VERSION 5.8 ;
BUSBITCHARS "[]" ;
DIVIDERCHAR "/" ;
UNITS
    DATABASE MICRONS 1000 ;
END UNITS

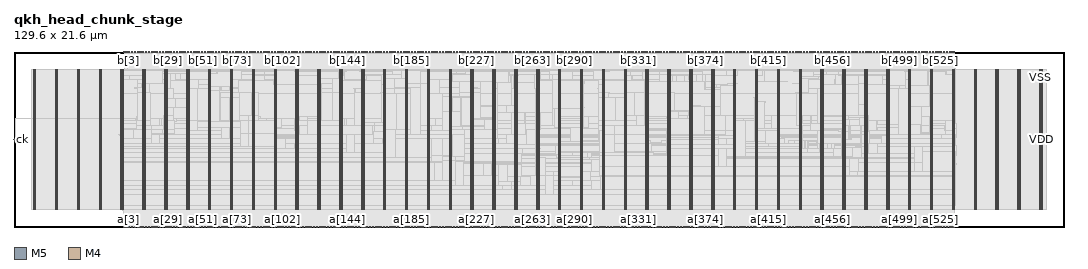
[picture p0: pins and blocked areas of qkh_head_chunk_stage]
MACRO qkh_head_chunk_stage
  FOREIGN qkh_head_chunk_stage 0 0 ;
  CLASS BLOCK ;
  SIZE 129.6 BY 21.6 ;
  PIN a[0]
    DIRECTION INPUT ;
    USE SIGNAL ;
    PORT
      LAYER M5 ;
        RECT  13.488 -0.072 13.512 0.072 ;
    END
  END a[0]
  PIN a[100]
    DIRECTION INPUT ;
    USE SIGNAL ;
    PORT
      LAYER M5 ;
        RECT  32.688 -0.072 32.712 0.072 ;
    END
  END a[100]
  PIN a[101]
    DIRECTION INPUT ;
    USE SIGNAL ;
    PORT
      LAYER M5 ;
        RECT  32.88 -0.072 32.904 0.072 ;
    END
  END a[101]
  PIN a[102]
    DIRECTION INPUT ;
    USE SIGNAL ;
    PORT
      LAYER M5 ;
        RECT  33.072 -0.072 33.096 0.072 ;
    END
  END a[102]
  PIN a[103]
    DIRECTION INPUT ;
    USE SIGNAL ;
    PORT
      LAYER M5 ;
        RECT  33.264 -0.072 33.288 0.072 ;
    END
  END a[103]
  PIN a[104]
    DIRECTION INPUT ;
    USE SIGNAL ;
    PORT
      LAYER M5 ;
        RECT  33.456 -0.072 33.48 0.072 ;
    END
  END a[104]
  PIN a[105]
    DIRECTION INPUT ;
    USE SIGNAL ;
    PORT
      LAYER M5 ;
        RECT  33.648 -0.072 33.672 0.072 ;
    END
  END a[105]
  PIN a[106]
    DIRECTION INPUT ;
    USE SIGNAL ;
    PORT
      LAYER M5 ;
        RECT  33.84 -0.072 33.864 0.072 ;
    END
  END a[106]
  PIN a[107]
    DIRECTION INPUT ;
    USE SIGNAL ;
    PORT
      LAYER M5 ;
        RECT  34.032 -0.072 34.056 0.072 ;
    END
  END a[107]
  PIN a[108]
    DIRECTION INPUT ;
    USE SIGNAL ;
    PORT
      LAYER M5 ;
        RECT  34.224 -0.072 34.248 0.072 ;
    END
  END a[108]
  PIN a[109]
    DIRECTION INPUT ;
    USE SIGNAL ;
    PORT
      LAYER M5 ;
        RECT  34.416 -0.072 34.44 0.072 ;
    END
  END a[109]
  PIN a[10]
    DIRECTION INPUT ;
    USE SIGNAL ;
    PORT
      LAYER M5 ;
        RECT  15.408 -0.072 15.432 0.072 ;
    END
  END a[10]
  PIN a[110]
    DIRECTION INPUT ;
    USE SIGNAL ;
    PORT
      LAYER M5 ;
        RECT  34.608 -0.072 34.632 0.072 ;
    END
  END a[110]
  PIN a[111]
    DIRECTION INPUT ;
    USE SIGNAL ;
    PORT
      LAYER M5 ;
        RECT  34.8 -0.072 34.824 0.072 ;
    END
  END a[111]
  PIN a[112]
    DIRECTION INPUT ;
    USE SIGNAL ;
    PORT
      LAYER M5 ;
        RECT  34.992 -0.072 35.016 0.072 ;
    END
  END a[112]
  PIN a[113]
    DIRECTION INPUT ;
    USE SIGNAL ;
    PORT
      LAYER M5 ;
        RECT  35.184 -0.072 35.208 0.072 ;
    END
  END a[113]
  PIN a[114]
    DIRECTION INPUT ;
    USE SIGNAL ;
    PORT
      LAYER M5 ;
        RECT  35.376 -0.072 35.4 0.072 ;
    END
  END a[114]
  PIN a[115]
    DIRECTION INPUT ;
    USE SIGNAL ;
    PORT
      LAYER M5 ;
        RECT  35.568 -0.072 35.592 0.072 ;
    END
  END a[115]
  PIN a[116]
    DIRECTION INPUT ;
    USE SIGNAL ;
    PORT
      LAYER M5 ;
        RECT  35.76 -0.072 35.784 0.072 ;
    END
  END a[116]
  PIN a[117]
    DIRECTION INPUT ;
    USE SIGNAL ;
    PORT
      LAYER M5 ;
        RECT  35.952 -0.072 35.976 0.072 ;
    END
  END a[117]
  PIN a[118]
    DIRECTION INPUT ;
    USE SIGNAL ;
    PORT
      LAYER M5 ;
        RECT  36.144 -0.072 36.168 0.072 ;
    END
  END a[118]
  PIN a[119]
    DIRECTION INPUT ;
    USE SIGNAL ;
    PORT
      LAYER M5 ;
        RECT  36.336 -0.072 36.36 0.072 ;
    END
  END a[119]
  PIN a[11]
    DIRECTION INPUT ;
    USE SIGNAL ;
    PORT
      LAYER M5 ;
        RECT  15.6 -0.072 15.624 0.072 ;
    END
  END a[11]
  PIN a[120]
    DIRECTION INPUT ;
    USE SIGNAL ;
    PORT
      LAYER M5 ;
        RECT  36.528 -0.072 36.552 0.072 ;
    END
  END a[120]
  PIN a[121]
    DIRECTION INPUT ;
    USE SIGNAL ;
    PORT
      LAYER M5 ;
        RECT  36.72 -0.072 36.744 0.072 ;
    END
  END a[121]
  PIN a[122]
    DIRECTION INPUT ;
    USE SIGNAL ;
    PORT
      LAYER M5 ;
        RECT  36.912 -0.072 36.936 0.072 ;
    END
  END a[122]
  PIN a[123]
    DIRECTION INPUT ;
    USE SIGNAL ;
    PORT
      LAYER M5 ;
        RECT  37.104 -0.072 37.128 0.072 ;
    END
  END a[123]
  PIN a[124]
    DIRECTION INPUT ;
    USE SIGNAL ;
    PORT
      LAYER M5 ;
        RECT  37.296 -0.072 37.32 0.072 ;
    END
  END a[124]
  PIN a[125]
    DIRECTION INPUT ;
    USE SIGNAL ;
    PORT
      LAYER M5 ;
        RECT  37.488 -0.072 37.512 0.072 ;
    END
  END a[125]
  PIN a[126]
    DIRECTION INPUT ;
    USE SIGNAL ;
    PORT
      LAYER M5 ;
        RECT  37.68 -0.072 37.704 0.072 ;
    END
  END a[126]
  PIN a[127]
    DIRECTION INPUT ;
    USE SIGNAL ;
    PORT
      LAYER M5 ;
        RECT  37.872 -0.072 37.896 0.072 ;
    END
  END a[127]
  PIN a[128]
    DIRECTION INPUT ;
    USE SIGNAL ;
    PORT
      LAYER M5 ;
        RECT  38.064 -0.072 38.088 0.072 ;
    END
  END a[128]
  PIN a[129]
    DIRECTION INPUT ;
    USE SIGNAL ;
    PORT
      LAYER M5 ;
        RECT  38.256 -0.072 38.28 0.072 ;
    END
  END a[129]
  PIN a[12]
    DIRECTION INPUT ;
    USE SIGNAL ;
    PORT
      LAYER M5 ;
        RECT  15.792 -0.072 15.816 0.072 ;
    END
  END a[12]
  PIN a[130]
    DIRECTION INPUT ;
    USE SIGNAL ;
    PORT
      LAYER M5 ;
        RECT  38.448 -0.072 38.472 0.072 ;
    END
  END a[130]
  PIN a[131]
    DIRECTION INPUT ;
    USE SIGNAL ;
    PORT
      LAYER M5 ;
        RECT  38.64 -0.072 38.664 0.072 ;
    END
  END a[131]
  PIN a[132]
    DIRECTION INPUT ;
    USE SIGNAL ;
    PORT
      LAYER M5 ;
        RECT  38.832 -0.072 38.856 0.072 ;
    END
  END a[132]
  PIN a[133]
    DIRECTION INPUT ;
    USE SIGNAL ;
    PORT
      LAYER M5 ;
        RECT  39.024 -0.072 39.048 0.072 ;
    END
  END a[133]
  PIN a[134]
    DIRECTION INPUT ;
    USE SIGNAL ;
    PORT
      LAYER M5 ;
        RECT  39.216 -0.072 39.24 0.072 ;
    END
  END a[134]
  PIN a[135]
    DIRECTION INPUT ;
    USE SIGNAL ;
    PORT
      LAYER M5 ;
        RECT  39.408 -0.072 39.432 0.072 ;
    END
  END a[135]
  PIN a[136]
    DIRECTION INPUT ;
    USE SIGNAL ;
    PORT
      LAYER M5 ;
        RECT  39.6 -0.072 39.624 0.072 ;
    END
  END a[136]
  PIN a[137]
    DIRECTION INPUT ;
    USE SIGNAL ;
    PORT
      LAYER M5 ;
        RECT  39.792 -0.072 39.816 0.072 ;
    END
  END a[137]
  PIN a[138]
    DIRECTION INPUT ;
    USE SIGNAL ;
    PORT
      LAYER M5 ;
        RECT  39.984 -0.072 40.008 0.072 ;
    END
  END a[138]
  PIN a[139]
    DIRECTION INPUT ;
    USE SIGNAL ;
    PORT
      LAYER M5 ;
        RECT  40.176 -0.072 40.2 0.072 ;
    END
  END a[139]
  PIN a[13]
    DIRECTION INPUT ;
    USE SIGNAL ;
    PORT
      LAYER M5 ;
        RECT  15.984 -0.072 16.008 0.072 ;
    END
  END a[13]
  PIN a[140]
    DIRECTION INPUT ;
    USE SIGNAL ;
    PORT
      LAYER M5 ;
        RECT  40.368 -0.072 40.392 0.072 ;
    END
  END a[140]
  PIN a[141]
    DIRECTION INPUT ;
    USE SIGNAL ;
    PORT
      LAYER M5 ;
        RECT  40.56 -0.072 40.584 0.072 ;
    END
  END a[141]
  PIN a[142]
    DIRECTION INPUT ;
    USE SIGNAL ;
    PORT
      LAYER M5 ;
        RECT  40.752 -0.072 40.776 0.072 ;
    END
  END a[142]
  PIN a[143]
    DIRECTION INPUT ;
    USE SIGNAL ;
    PORT
      LAYER M5 ;
        RECT  40.944 -0.072 40.968 0.072 ;
    END
  END a[143]
  PIN a[144]
    DIRECTION INPUT ;
    USE SIGNAL ;
    PORT
      LAYER M5 ;
        RECT  41.136 -0.072 41.16 0.072 ;
    END
  END a[144]
  PIN a[145]
    DIRECTION INPUT ;
    USE SIGNAL ;
    PORT
      LAYER M5 ;
        RECT  41.328 -0.072 41.352 0.072 ;
    END
  END a[145]
  PIN a[146]
    DIRECTION INPUT ;
    USE SIGNAL ;
    PORT
      LAYER M5 ;
        RECT  41.52 -0.072 41.544 0.072 ;
    END
  END a[146]
  PIN a[147]
    DIRECTION INPUT ;
    USE SIGNAL ;
    PORT
      LAYER M5 ;
        RECT  41.712 -0.072 41.736 0.072 ;
    END
  END a[147]
  PIN a[148]
    DIRECTION INPUT ;
    USE SIGNAL ;
    PORT
      LAYER M5 ;
        RECT  41.904 -0.072 41.928 0.072 ;
    END
  END a[148]
  PIN a[149]
    DIRECTION INPUT ;
    USE SIGNAL ;
    PORT
      LAYER M5 ;
        RECT  42.096 -0.072 42.12 0.072 ;
    END
  END a[149]
  PIN a[14]
    DIRECTION INPUT ;
    USE SIGNAL ;
    PORT
      LAYER M5 ;
        RECT  16.176 -0.072 16.2 0.072 ;
    END
  END a[14]
  PIN a[150]
    DIRECTION INPUT ;
    USE SIGNAL ;
    PORT
      LAYER M5 ;
        RECT  42.288 -0.072 42.312 0.072 ;
    END
  END a[150]
  PIN a[151]
    DIRECTION INPUT ;
    USE SIGNAL ;
    PORT
      LAYER M5 ;
        RECT  42.48 -0.072 42.504 0.072 ;
    END
  END a[151]
  PIN a[152]
    DIRECTION INPUT ;
    USE SIGNAL ;
    PORT
      LAYER M5 ;
        RECT  42.672 -0.072 42.696 0.072 ;
    END
  END a[152]
  PIN a[153]
    DIRECTION INPUT ;
    USE SIGNAL ;
    PORT
      LAYER M5 ;
        RECT  42.864 -0.072 42.888 0.072 ;
    END
  END a[153]
  PIN a[154]
    DIRECTION INPUT ;
    USE SIGNAL ;
    PORT
      LAYER M5 ;
        RECT  43.056 -0.072 43.08 0.072 ;
    END
  END a[154]
  PIN a[155]
    DIRECTION INPUT ;
    USE SIGNAL ;
    PORT
      LAYER M5 ;
        RECT  43.248 -0.072 43.272 0.072 ;
    END
  END a[155]
  PIN a[156]
    DIRECTION INPUT ;
    USE SIGNAL ;
    PORT
      LAYER M5 ;
        RECT  43.44 -0.072 43.464 0.072 ;
    END
  END a[156]
  PIN a[157]
    DIRECTION INPUT ;
    USE SIGNAL ;
    PORT
      LAYER M5 ;
        RECT  43.632 -0.072 43.656 0.072 ;
    END
  END a[157]
  PIN a[158]
    DIRECTION INPUT ;
    USE SIGNAL ;
    PORT
      LAYER M5 ;
        RECT  43.824 -0.072 43.848 0.072 ;
    END
  END a[158]
  PIN a[159]
    DIRECTION INPUT ;
    USE SIGNAL ;
    PORT
      LAYER M5 ;
        RECT  44.016 -0.072 44.04 0.072 ;
    END
  END a[159]
  PIN a[15]
    DIRECTION INPUT ;
    USE SIGNAL ;
    PORT
      LAYER M5 ;
        RECT  16.368 -0.072 16.392 0.072 ;
    END
  END a[15]
  PIN a[160]
    DIRECTION INPUT ;
    USE SIGNAL ;
    PORT
      LAYER M5 ;
        RECT  44.208 -0.072 44.232 0.072 ;
    END
  END a[160]
  PIN a[161]
    DIRECTION INPUT ;
    USE SIGNAL ;
    PORT
      LAYER M5 ;
        RECT  44.4 -0.072 44.424 0.072 ;
    END
  END a[161]
  PIN a[162]
    DIRECTION INPUT ;
    USE SIGNAL ;
    PORT
      LAYER M5 ;
        RECT  44.592 -0.072 44.616 0.072 ;
    END
  END a[162]
  PIN a[163]
    DIRECTION INPUT ;
    USE SIGNAL ;
    PORT
      LAYER M5 ;
        RECT  44.784 -0.072 44.808 0.072 ;
    END
  END a[163]
  PIN a[164]
    DIRECTION INPUT ;
    USE SIGNAL ;
    PORT
      LAYER M5 ;
        RECT  44.976 -0.072 45 0.072 ;
    END
  END a[164]
  PIN a[165]
    DIRECTION INPUT ;
    USE SIGNAL ;
    PORT
      LAYER M5 ;
        RECT  45.168 -0.072 45.192 0.072 ;
    END
  END a[165]
  PIN a[166]
    DIRECTION INPUT ;
    USE SIGNAL ;
    PORT
      LAYER M5 ;
        RECT  45.36 -0.072 45.384 0.072 ;
    END
  END a[166]
  PIN a[167]
    DIRECTION INPUT ;
    USE SIGNAL ;
    PORT
      LAYER M5 ;
        RECT  45.552 -0.072 45.576 0.072 ;
    END
  END a[167]
  PIN a[168]
    DIRECTION INPUT ;
    USE SIGNAL ;
    PORT
      LAYER M5 ;
        RECT  45.744 -0.072 45.768 0.072 ;
    END
  END a[168]
  PIN a[169]
    DIRECTION INPUT ;
    USE SIGNAL ;
    PORT
      LAYER M5 ;
        RECT  45.936 -0.072 45.96 0.072 ;
    END
  END a[169]
  PIN a[16]
    DIRECTION INPUT ;
    USE SIGNAL ;
    PORT
      LAYER M5 ;
        RECT  16.56 -0.072 16.584 0.072 ;
    END
  END a[16]
  PIN a[170]
    DIRECTION INPUT ;
    USE SIGNAL ;
    PORT
      LAYER M5 ;
        RECT  46.128 -0.072 46.152 0.072 ;
    END
  END a[170]
  PIN a[171]
    DIRECTION INPUT ;
    USE SIGNAL ;
    PORT
      LAYER M5 ;
        RECT  46.32 -0.072 46.344 0.072 ;
    END
  END a[171]
  PIN a[172]
    DIRECTION INPUT ;
    USE SIGNAL ;
    PORT
      LAYER M5 ;
        RECT  46.512 -0.072 46.536 0.072 ;
    END
  END a[172]
  PIN a[173]
    DIRECTION INPUT ;
    USE SIGNAL ;
    PORT
      LAYER M5 ;
        RECT  46.704 -0.072 46.728 0.072 ;
    END
  END a[173]
  PIN a[174]
    DIRECTION INPUT ;
    USE SIGNAL ;
    PORT
      LAYER M5 ;
        RECT  46.896 -0.072 46.92 0.072 ;
    END
  END a[174]
  PIN a[175]
    DIRECTION INPUT ;
    USE SIGNAL ;
    PORT
      LAYER M5 ;
        RECT  47.088 -0.072 47.112 0.072 ;
    END
  END a[175]
  PIN a[176]
    DIRECTION INPUT ;
    USE SIGNAL ;
    PORT
      LAYER M5 ;
        RECT  47.28 -0.072 47.304 0.072 ;
    END
  END a[176]
  PIN a[177]
    DIRECTION INPUT ;
    USE SIGNAL ;
    PORT
      LAYER M5 ;
        RECT  47.472 -0.072 47.496 0.072 ;
    END
  END a[177]
  PIN a[178]
    DIRECTION INPUT ;
    USE SIGNAL ;
    PORT
      LAYER M5 ;
        RECT  47.664 -0.072 47.688 0.072 ;
    END
  END a[178]
  PIN a[179]
    DIRECTION INPUT ;
    USE SIGNAL ;
    PORT
      LAYER M5 ;
        RECT  47.856 -0.072 47.88 0.072 ;
    END
  END a[179]
  PIN a[17]
    DIRECTION INPUT ;
    USE SIGNAL ;
    PORT
      LAYER M5 ;
        RECT  16.752 -0.072 16.776 0.072 ;
    END
  END a[17]
  PIN a[180]
    DIRECTION INPUT ;
    USE SIGNAL ;
    PORT
      LAYER M5 ;
        RECT  48.048 -0.072 48.072 0.072 ;
    END
  END a[180]
  PIN a[181]
    DIRECTION INPUT ;
    USE SIGNAL ;
    PORT
      LAYER M5 ;
        RECT  48.24 -0.072 48.264 0.072 ;
    END
  END a[181]
  PIN a[182]
    DIRECTION INPUT ;
    USE SIGNAL ;
    PORT
      LAYER M5 ;
        RECT  48.432 -0.072 48.456 0.072 ;
    END
  END a[182]
  PIN a[183]
    DIRECTION INPUT ;
    USE SIGNAL ;
    PORT
      LAYER M5 ;
        RECT  48.624 -0.072 48.648 0.072 ;
    END
  END a[183]
  PIN a[184]
    DIRECTION INPUT ;
    USE SIGNAL ;
    PORT
      LAYER M5 ;
        RECT  48.816 -0.072 48.84 0.072 ;
    END
  END a[184]
  PIN a[185]
    DIRECTION INPUT ;
    USE SIGNAL ;
    PORT
      LAYER M5 ;
        RECT  49.008 -0.072 49.032 0.072 ;
    END
  END a[185]
  PIN a[186]
    DIRECTION INPUT ;
    USE SIGNAL ;
    PORT
      LAYER M5 ;
        RECT  49.2 -0.072 49.224 0.072 ;
    END
  END a[186]
  PIN a[187]
    DIRECTION INPUT ;
    USE SIGNAL ;
    PORT
      LAYER M5 ;
        RECT  49.392 -0.072 49.416 0.072 ;
    END
  END a[187]
  PIN a[188]
    DIRECTION INPUT ;
    USE SIGNAL ;
    PORT
      LAYER M5 ;
        RECT  49.584 -0.072 49.608 0.072 ;
    END
  END a[188]
  PIN a[189]
    DIRECTION INPUT ;
    USE SIGNAL ;
    PORT
      LAYER M5 ;
        RECT  49.776 -0.072 49.8 0.072 ;
    END
  END a[189]
  PIN a[18]
    DIRECTION INPUT ;
    USE SIGNAL ;
    PORT
      LAYER M5 ;
        RECT  16.944 -0.072 16.968 0.072 ;
    END
  END a[18]
  PIN a[190]
    DIRECTION INPUT ;
    USE SIGNAL ;
    PORT
      LAYER M5 ;
        RECT  49.968 -0.072 49.992 0.072 ;
    END
  END a[190]
  PIN a[191]
    DIRECTION INPUT ;
    USE SIGNAL ;
    PORT
      LAYER M5 ;
        RECT  50.16 -0.072 50.184 0.072 ;
    END
  END a[191]
  PIN a[192]
    DIRECTION INPUT ;
    USE SIGNAL ;
    PORT
      LAYER M5 ;
        RECT  50.352 -0.072 50.376 0.072 ;
    END
  END a[192]
  PIN a[193]
    DIRECTION INPUT ;
    USE SIGNAL ;
    PORT
      LAYER M5 ;
        RECT  50.544 -0.072 50.568 0.072 ;
    END
  END a[193]
  PIN a[194]
    DIRECTION INPUT ;
    USE SIGNAL ;
    PORT
      LAYER M5 ;
        RECT  50.736 -0.072 50.76 0.072 ;
    END
  END a[194]
  PIN a[195]
    DIRECTION INPUT ;
    USE SIGNAL ;
    PORT
      LAYER M5 ;
        RECT  50.928 -0.072 50.952 0.072 ;
    END
  END a[195]
  PIN a[196]
    DIRECTION INPUT ;
    USE SIGNAL ;
    PORT
      LAYER M5 ;
        RECT  51.12 -0.072 51.144 0.072 ;
    END
  END a[196]
  PIN a[197]
    DIRECTION INPUT ;
    USE SIGNAL ;
    PORT
      LAYER M5 ;
        RECT  51.312 -0.072 51.336 0.072 ;
    END
  END a[197]
  PIN a[198]
    DIRECTION INPUT ;
    USE SIGNAL ;
    PORT
      LAYER M5 ;
        RECT  51.504 -0.072 51.528 0.072 ;
    END
  END a[198]
  PIN a[199]
    DIRECTION INPUT ;
    USE SIGNAL ;
    PORT
      LAYER M5 ;
        RECT  51.696 -0.072 51.72 0.072 ;
    END
  END a[199]
  PIN a[19]
    DIRECTION INPUT ;
    USE SIGNAL ;
    PORT
      LAYER M5 ;
        RECT  17.136 -0.072 17.16 0.072 ;
    END
  END a[19]
  PIN a[1]
    DIRECTION INPUT ;
    USE SIGNAL ;
    PORT
      LAYER M5 ;
        RECT  13.68 -0.072 13.704 0.072 ;
    END
  END a[1]
  PIN a[200]
    DIRECTION INPUT ;
    USE SIGNAL ;
    PORT
      LAYER M5 ;
        RECT  51.888 -0.072 51.912 0.072 ;
    END
  END a[200]
  PIN a[201]
    DIRECTION INPUT ;
    USE SIGNAL ;
    PORT
      LAYER M5 ;
        RECT  52.08 -0.072 52.104 0.072 ;
    END
  END a[201]
  PIN a[202]
    DIRECTION INPUT ;
    USE SIGNAL ;
    PORT
      LAYER M5 ;
        RECT  52.272 -0.072 52.296 0.072 ;
    END
  END a[202]
  PIN a[203]
    DIRECTION INPUT ;
    USE SIGNAL ;
    PORT
      LAYER M5 ;
        RECT  52.464 -0.072 52.488 0.072 ;
    END
  END a[203]
  PIN a[204]
    DIRECTION INPUT ;
    USE SIGNAL ;
    PORT
      LAYER M5 ;
        RECT  52.656 -0.072 52.68 0.072 ;
    END
  END a[204]
  PIN a[205]
    DIRECTION INPUT ;
    USE SIGNAL ;
    PORT
      LAYER M5 ;
        RECT  52.848 -0.072 52.872 0.072 ;
    END
  END a[205]
  PIN a[206]
    DIRECTION INPUT ;
    USE SIGNAL ;
    PORT
      LAYER M5 ;
        RECT  53.04 -0.072 53.064 0.072 ;
    END
  END a[206]
  PIN a[207]
    DIRECTION INPUT ;
    USE SIGNAL ;
    PORT
      LAYER M5 ;
        RECT  53.232 -0.072 53.256 0.072 ;
    END
  END a[207]
  PIN a[208]
    DIRECTION INPUT ;
    USE SIGNAL ;
    PORT
      LAYER M5 ;
        RECT  53.424 -0.072 53.448 0.072 ;
    END
  END a[208]
  PIN a[209]
    DIRECTION INPUT ;
    USE SIGNAL ;
    PORT
      LAYER M5 ;
        RECT  53.616 -0.072 53.64 0.072 ;
    END
  END a[209]
  PIN a[20]
    DIRECTION INPUT ;
    USE SIGNAL ;
    PORT
      LAYER M5 ;
        RECT  17.328 -0.072 17.352 0.072 ;
    END
  END a[20]
  PIN a[210]
    DIRECTION INPUT ;
    USE SIGNAL ;
    PORT
      LAYER M5 ;
        RECT  53.808 -0.072 53.832 0.072 ;
    END
  END a[210]
  PIN a[211]
    DIRECTION INPUT ;
    USE SIGNAL ;
    PORT
      LAYER M5 ;
        RECT  54 -0.072 54.024 0.072 ;
    END
  END a[211]
  PIN a[212]
    DIRECTION INPUT ;
    USE SIGNAL ;
    PORT
      LAYER M5 ;
        RECT  54.192 -0.072 54.216 0.072 ;
    END
  END a[212]
  PIN a[213]
    DIRECTION INPUT ;
    USE SIGNAL ;
    PORT
      LAYER M5 ;
        RECT  54.384 -0.072 54.408 0.072 ;
    END
  END a[213]
  PIN a[214]
    DIRECTION INPUT ;
    USE SIGNAL ;
    PORT
      LAYER M5 ;
        RECT  54.576 -0.072 54.6 0.072 ;
    END
  END a[214]
  PIN a[215]
    DIRECTION INPUT ;
    USE SIGNAL ;
    PORT
      LAYER M5 ;
        RECT  54.768 -0.072 54.792 0.072 ;
    END
  END a[215]
  PIN a[216]
    DIRECTION INPUT ;
    USE SIGNAL ;
    PORT
      LAYER M5 ;
        RECT  54.96 -0.072 54.984 0.072 ;
    END
  END a[216]
  PIN a[217]
    DIRECTION INPUT ;
    USE SIGNAL ;
    PORT
      LAYER M5 ;
        RECT  55.152 -0.072 55.176 0.072 ;
    END
  END a[217]
  PIN a[218]
    DIRECTION INPUT ;
    USE SIGNAL ;
    PORT
      LAYER M5 ;
        RECT  55.344 -0.072 55.368 0.072 ;
    END
  END a[218]
  PIN a[219]
    DIRECTION INPUT ;
    USE SIGNAL ;
    PORT
      LAYER M5 ;
        RECT  55.536 -0.072 55.56 0.072 ;
    END
  END a[219]
  PIN a[21]
    DIRECTION INPUT ;
    USE SIGNAL ;
    PORT
      LAYER M5 ;
        RECT  17.52 -0.072 17.544 0.072 ;
    END
  END a[21]
  PIN a[220]
    DIRECTION INPUT ;
    USE SIGNAL ;
    PORT
      LAYER M5 ;
        RECT  55.728 -0.072 55.752 0.072 ;
    END
  END a[220]
  PIN a[221]
    DIRECTION INPUT ;
    USE SIGNAL ;
    PORT
      LAYER M5 ;
        RECT  55.92 -0.072 55.944 0.072 ;
    END
  END a[221]
  PIN a[222]
    DIRECTION INPUT ;
    USE SIGNAL ;
    PORT
      LAYER M5 ;
        RECT  56.112 -0.072 56.136 0.072 ;
    END
  END a[222]
  PIN a[223]
    DIRECTION INPUT ;
    USE SIGNAL ;
    PORT
      LAYER M5 ;
        RECT  56.304 -0.072 56.328 0.072 ;
    END
  END a[223]
  PIN a[224]
    DIRECTION INPUT ;
    USE SIGNAL ;
    PORT
      LAYER M5 ;
        RECT  56.496 -0.072 56.52 0.072 ;
    END
  END a[224]
  PIN a[225]
    DIRECTION INPUT ;
    USE SIGNAL ;
    PORT
      LAYER M5 ;
        RECT  56.688 -0.072 56.712 0.072 ;
    END
  END a[225]
  PIN a[226]
    DIRECTION INPUT ;
    USE SIGNAL ;
    PORT
      LAYER M5 ;
        RECT  56.88 -0.072 56.904 0.072 ;
    END
  END a[226]
  PIN a[227]
    DIRECTION INPUT ;
    USE SIGNAL ;
    PORT
      LAYER M5 ;
        RECT  57.072 -0.072 57.096 0.072 ;
    END
  END a[227]
  PIN a[228]
    DIRECTION INPUT ;
    USE SIGNAL ;
    PORT
      LAYER M5 ;
        RECT  57.264 -0.072 57.288 0.072 ;
    END
  END a[228]
  PIN a[229]
    DIRECTION INPUT ;
    USE SIGNAL ;
    PORT
      LAYER M5 ;
        RECT  57.456 -0.072 57.48 0.072 ;
    END
  END a[229]
  PIN a[22]
    DIRECTION INPUT ;
    USE SIGNAL ;
    PORT
      LAYER M5 ;
        RECT  17.712 -0.072 17.736 0.072 ;
    END
  END a[22]
  PIN a[230]
    DIRECTION INPUT ;
    USE SIGNAL ;
    PORT
      LAYER M5 ;
        RECT  57.648 -0.072 57.672 0.072 ;
    END
  END a[230]
  PIN a[231]
    DIRECTION INPUT ;
    USE SIGNAL ;
    PORT
      LAYER M5 ;
        RECT  57.84 -0.072 57.864 0.072 ;
    END
  END a[231]
  PIN a[232]
    DIRECTION INPUT ;
    USE SIGNAL ;
    PORT
      LAYER M5 ;
        RECT  58.032 -0.072 58.056 0.072 ;
    END
  END a[232]
  PIN a[233]
    DIRECTION INPUT ;
    USE SIGNAL ;
    PORT
      LAYER M5 ;
        RECT  58.224 -0.072 58.248 0.072 ;
    END
  END a[233]
  PIN a[234]
    DIRECTION INPUT ;
    USE SIGNAL ;
    PORT
      LAYER M5 ;
        RECT  58.416 -0.072 58.44 0.072 ;
    END
  END a[234]
  PIN a[235]
    DIRECTION INPUT ;
    USE SIGNAL ;
    PORT
      LAYER M5 ;
        RECT  58.608 -0.072 58.632 0.072 ;
    END
  END a[235]
  PIN a[236]
    DIRECTION INPUT ;
    USE SIGNAL ;
    PORT
      LAYER M5 ;
        RECT  58.8 -0.072 58.824 0.072 ;
    END
  END a[236]
  PIN a[237]
    DIRECTION INPUT ;
    USE SIGNAL ;
    PORT
      LAYER M5 ;
        RECT  58.992 -0.072 59.016 0.072 ;
    END
  END a[237]
  PIN a[238]
    DIRECTION INPUT ;
    USE SIGNAL ;
    PORT
      LAYER M5 ;
        RECT  59.184 -0.072 59.208 0.072 ;
    END
  END a[238]
  PIN a[239]
    DIRECTION INPUT ;
    USE SIGNAL ;
    PORT
      LAYER M5 ;
        RECT  59.376 -0.072 59.4 0.072 ;
    END
  END a[239]
  PIN a[23]
    DIRECTION INPUT ;
    USE SIGNAL ;
    PORT
      LAYER M5 ;
        RECT  17.904 -0.072 17.928 0.072 ;
    END
  END a[23]
  PIN a[240]
    DIRECTION INPUT ;
    USE SIGNAL ;
    PORT
      LAYER M5 ;
        RECT  59.568 -0.072 59.592 0.072 ;
    END
  END a[240]
  PIN a[241]
    DIRECTION INPUT ;
    USE SIGNAL ;
    PORT
      LAYER M5 ;
        RECT  59.76 -0.072 59.784 0.072 ;
    END
  END a[241]
  PIN a[242]
    DIRECTION INPUT ;
    USE SIGNAL ;
    PORT
      LAYER M5 ;
        RECT  59.952 -0.072 59.976 0.072 ;
    END
  END a[242]
  PIN a[243]
    DIRECTION INPUT ;
    USE SIGNAL ;
    PORT
      LAYER M5 ;
        RECT  60.144 -0.072 60.168 0.072 ;
    END
  END a[243]
  PIN a[244]
    DIRECTION INPUT ;
    USE SIGNAL ;
    PORT
      LAYER M5 ;
        RECT  60.336 -0.072 60.36 0.072 ;
    END
  END a[244]
  PIN a[245]
    DIRECTION INPUT ;
    USE SIGNAL ;
    PORT
      LAYER M5 ;
        RECT  60.528 -0.072 60.552 0.072 ;
    END
  END a[245]
  PIN a[246]
    DIRECTION INPUT ;
    USE SIGNAL ;
    PORT
      LAYER M5 ;
        RECT  60.72 -0.072 60.744 0.072 ;
    END
  END a[246]
  PIN a[247]
    DIRECTION INPUT ;
    USE SIGNAL ;
    PORT
      LAYER M5 ;
        RECT  60.912 -0.072 60.936 0.072 ;
    END
  END a[247]
  PIN a[248]
    DIRECTION INPUT ;
    USE SIGNAL ;
    PORT
      LAYER M5 ;
        RECT  61.104 -0.072 61.128 0.072 ;
    END
  END a[248]
  PIN a[249]
    DIRECTION INPUT ;
    USE SIGNAL ;
    PORT
      LAYER M5 ;
        RECT  61.296 -0.072 61.32 0.072 ;
    END
  END a[249]
  PIN a[24]
    DIRECTION INPUT ;
    USE SIGNAL ;
    PORT
      LAYER M5 ;
        RECT  18.096 -0.072 18.12 0.072 ;
    END
  END a[24]
  PIN a[250]
    DIRECTION INPUT ;
    USE SIGNAL ;
    PORT
      LAYER M5 ;
        RECT  61.488 -0.072 61.512 0.072 ;
    END
  END a[250]
  PIN a[251]
    DIRECTION INPUT ;
    USE SIGNAL ;
    PORT
      LAYER M5 ;
        RECT  61.68 -0.072 61.704 0.072 ;
    END
  END a[251]
  PIN a[252]
    DIRECTION INPUT ;
    USE SIGNAL ;
    PORT
      LAYER M5 ;
        RECT  61.872 -0.072 61.896 0.072 ;
    END
  END a[252]
  PIN a[253]
    DIRECTION INPUT ;
    USE SIGNAL ;
    PORT
      LAYER M5 ;
        RECT  62.064 -0.072 62.088 0.072 ;
    END
  END a[253]
  PIN a[254]
    DIRECTION INPUT ;
    USE SIGNAL ;
    PORT
      LAYER M5 ;
        RECT  62.256 -0.072 62.28 0.072 ;
    END
  END a[254]
  PIN a[255]
    DIRECTION INPUT ;
    USE SIGNAL ;
    PORT
      LAYER M5 ;
        RECT  62.448 -0.072 62.472 0.072 ;
    END
  END a[255]
  PIN a[256]
    DIRECTION INPUT ;
    USE SIGNAL ;
    PORT
      LAYER M5 ;
        RECT  62.64 -0.072 62.664 0.072 ;
    END
  END a[256]
  PIN a[257]
    DIRECTION INPUT ;
    USE SIGNAL ;
    PORT
      LAYER M5 ;
        RECT  62.832 -0.072 62.856 0.072 ;
    END
  END a[257]
  PIN a[258]
    DIRECTION INPUT ;
    USE SIGNAL ;
    PORT
      LAYER M5 ;
        RECT  63.024 -0.072 63.048 0.072 ;
    END
  END a[258]
  PIN a[259]
    DIRECTION INPUT ;
    USE SIGNAL ;
    PORT
      LAYER M5 ;
        RECT  63.216 -0.072 63.24 0.072 ;
    END
  END a[259]
  PIN a[25]
    DIRECTION INPUT ;
    USE SIGNAL ;
    PORT
      LAYER M5 ;
        RECT  18.288 -0.072 18.312 0.072 ;
    END
  END a[25]
  PIN a[260]
    DIRECTION INPUT ;
    USE SIGNAL ;
    PORT
      LAYER M5 ;
        RECT  63.408 -0.072 63.432 0.072 ;
    END
  END a[260]
  PIN a[261]
    DIRECTION INPUT ;
    USE SIGNAL ;
    PORT
      LAYER M5 ;
        RECT  63.6 -0.072 63.624 0.072 ;
    END
  END a[261]
  PIN a[262]
    DIRECTION INPUT ;
    USE SIGNAL ;
    PORT
      LAYER M5 ;
        RECT  63.792 -0.072 63.816 0.072 ;
    END
  END a[262]
  PIN a[263]
    DIRECTION INPUT ;
    USE SIGNAL ;
    PORT
      LAYER M5 ;
        RECT  63.984 -0.072 64.008 0.072 ;
    END
  END a[263]
  PIN a[264]
    DIRECTION INPUT ;
    USE SIGNAL ;
    PORT
      LAYER M5 ;
        RECT  64.176 -0.072 64.2 0.072 ;
    END
  END a[264]
  PIN a[265]
    DIRECTION INPUT ;
    USE SIGNAL ;
    PORT
      LAYER M5 ;
        RECT  64.368 -0.072 64.392 0.072 ;
    END
  END a[265]
  PIN a[266]
    DIRECTION INPUT ;
    USE SIGNAL ;
    PORT
      LAYER M5 ;
        RECT  64.56 -0.072 64.584 0.072 ;
    END
  END a[266]
  PIN a[267]
    DIRECTION INPUT ;
    USE SIGNAL ;
    PORT
      LAYER M5 ;
        RECT  64.752 -0.072 64.776 0.072 ;
    END
  END a[267]
  PIN a[268]
    DIRECTION INPUT ;
    USE SIGNAL ;
    PORT
      LAYER M5 ;
        RECT  64.944 -0.072 64.968 0.072 ;
    END
  END a[268]
  PIN a[269]
    DIRECTION INPUT ;
    USE SIGNAL ;
    PORT
      LAYER M5 ;
        RECT  65.136 -0.072 65.16 0.072 ;
    END
  END a[269]
  PIN a[26]
    DIRECTION INPUT ;
    USE SIGNAL ;
    PORT
      LAYER M5 ;
        RECT  18.48 -0.072 18.504 0.072 ;
    END
  END a[26]
  PIN a[270]
    DIRECTION INPUT ;
    USE SIGNAL ;
    PORT
      LAYER M5 ;
        RECT  65.328 -0.072 65.352 0.072 ;
    END
  END a[270]
  PIN a[271]
    DIRECTION INPUT ;
    USE SIGNAL ;
    PORT
      LAYER M5 ;
        RECT  65.52 -0.072 65.544 0.072 ;
    END
  END a[271]
  PIN a[272]
    DIRECTION INPUT ;
    USE SIGNAL ;
    PORT
      LAYER M5 ;
        RECT  65.712 -0.072 65.736 0.072 ;
    END
  END a[272]
  PIN a[273]
    DIRECTION INPUT ;
    USE SIGNAL ;
    PORT
      LAYER M5 ;
        RECT  65.904 -0.072 65.928 0.072 ;
    END
  END a[273]
  PIN a[274]
    DIRECTION INPUT ;
    USE SIGNAL ;
    PORT
      LAYER M5 ;
        RECT  66.096 -0.072 66.12 0.072 ;
    END
  END a[274]
  PIN a[275]
    DIRECTION INPUT ;
    USE SIGNAL ;
    PORT
      LAYER M5 ;
        RECT  66.288 -0.072 66.312 0.072 ;
    END
  END a[275]
  PIN a[276]
    DIRECTION INPUT ;
    USE SIGNAL ;
    PORT
      LAYER M5 ;
        RECT  66.48 -0.072 66.504 0.072 ;
    END
  END a[276]
  PIN a[277]
    DIRECTION INPUT ;
    USE SIGNAL ;
    PORT
      LAYER M5 ;
        RECT  66.672 -0.072 66.696 0.072 ;
    END
  END a[277]
  PIN a[278]
    DIRECTION INPUT ;
    USE SIGNAL ;
    PORT
      LAYER M5 ;
        RECT  66.864 -0.072 66.888 0.072 ;
    END
  END a[278]
  PIN a[279]
    DIRECTION INPUT ;
    USE SIGNAL ;
    PORT
      LAYER M5 ;
        RECT  67.056 -0.072 67.08 0.072 ;
    END
  END a[279]
  PIN a[27]
    DIRECTION INPUT ;
    USE SIGNAL ;
    PORT
      LAYER M5 ;
        RECT  18.672 -0.072 18.696 0.072 ;
    END
  END a[27]
  PIN a[280]
    DIRECTION INPUT ;
    USE SIGNAL ;
    PORT
      LAYER M5 ;
        RECT  67.248 -0.072 67.272 0.072 ;
    END
  END a[280]
  PIN a[281]
    DIRECTION INPUT ;
    USE SIGNAL ;
    PORT
      LAYER M5 ;
        RECT  67.44 -0.072 67.464 0.072 ;
    END
  END a[281]
  PIN a[282]
    DIRECTION INPUT ;
    USE SIGNAL ;
    PORT
      LAYER M5 ;
        RECT  67.632 -0.072 67.656 0.072 ;
    END
  END a[282]
  PIN a[283]
    DIRECTION INPUT ;
    USE SIGNAL ;
    PORT
      LAYER M5 ;
        RECT  67.824 -0.072 67.848 0.072 ;
    END
  END a[283]
  PIN a[284]
    DIRECTION INPUT ;
    USE SIGNAL ;
    PORT
      LAYER M5 ;
        RECT  68.016 -0.072 68.04 0.072 ;
    END
  END a[284]
  PIN a[285]
    DIRECTION INPUT ;
    USE SIGNAL ;
    PORT
      LAYER M5 ;
        RECT  68.208 -0.072 68.232 0.072 ;
    END
  END a[285]
  PIN a[286]
    DIRECTION INPUT ;
    USE SIGNAL ;
    PORT
      LAYER M5 ;
        RECT  68.4 -0.072 68.424 0.072 ;
    END
  END a[286]
  PIN a[287]
    DIRECTION INPUT ;
    USE SIGNAL ;
    PORT
      LAYER M5 ;
        RECT  68.592 -0.072 68.616 0.072 ;
    END
  END a[287]
  PIN a[288]
    DIRECTION INPUT ;
    USE SIGNAL ;
    PORT
      LAYER M5 ;
        RECT  68.784 -0.072 68.808 0.072 ;
    END
  END a[288]
  PIN a[289]
    DIRECTION INPUT ;
    USE SIGNAL ;
    PORT
      LAYER M5 ;
        RECT  68.976 -0.072 69 0.072 ;
    END
  END a[289]
  PIN a[28]
    DIRECTION INPUT ;
    USE SIGNAL ;
    PORT
      LAYER M5 ;
        RECT  18.864 -0.072 18.888 0.072 ;
    END
  END a[28]
  PIN a[290]
    DIRECTION INPUT ;
    USE SIGNAL ;
    PORT
      LAYER M5 ;
        RECT  69.168 -0.072 69.192 0.072 ;
    END
  END a[290]
  PIN a[291]
    DIRECTION INPUT ;
    USE SIGNAL ;
    PORT
      LAYER M5 ;
        RECT  69.36 -0.072 69.384 0.072 ;
    END
  END a[291]
  PIN a[292]
    DIRECTION INPUT ;
    USE SIGNAL ;
    PORT
      LAYER M5 ;
        RECT  69.552 -0.072 69.576 0.072 ;
    END
  END a[292]
  PIN a[293]
    DIRECTION INPUT ;
    USE SIGNAL ;
    PORT
      LAYER M5 ;
        RECT  69.744 -0.072 69.768 0.072 ;
    END
  END a[293]
  PIN a[294]
    DIRECTION INPUT ;
    USE SIGNAL ;
    PORT
      LAYER M5 ;
        RECT  69.936 -0.072 69.96 0.072 ;
    END
  END a[294]
  PIN a[295]
    DIRECTION INPUT ;
    USE SIGNAL ;
    PORT
      LAYER M5 ;
        RECT  70.128 -0.072 70.152 0.072 ;
    END
  END a[295]
  PIN a[296]
    DIRECTION INPUT ;
    USE SIGNAL ;
    PORT
      LAYER M5 ;
        RECT  70.32 -0.072 70.344 0.072 ;
    END
  END a[296]
  PIN a[297]
    DIRECTION INPUT ;
    USE SIGNAL ;
    PORT
      LAYER M5 ;
        RECT  70.512 -0.072 70.536 0.072 ;
    END
  END a[297]
  PIN a[298]
    DIRECTION INPUT ;
    USE SIGNAL ;
    PORT
      LAYER M5 ;
        RECT  70.704 -0.072 70.728 0.072 ;
    END
  END a[298]
  PIN a[299]
    DIRECTION INPUT ;
    USE SIGNAL ;
    PORT
      LAYER M5 ;
        RECT  70.896 -0.072 70.92 0.072 ;
    END
  END a[299]
  PIN a[29]
    DIRECTION INPUT ;
    USE SIGNAL ;
    PORT
      LAYER M5 ;
        RECT  19.056 -0.072 19.08 0.072 ;
    END
  END a[29]
  PIN a[2]
    DIRECTION INPUT ;
    USE SIGNAL ;
    PORT
      LAYER M5 ;
        RECT  13.872 -0.072 13.896 0.072 ;
    END
  END a[2]
  PIN a[300]
    DIRECTION INPUT ;
    USE SIGNAL ;
    PORT
      LAYER M5 ;
        RECT  71.088 -0.072 71.112 0.072 ;
    END
  END a[300]
  PIN a[301]
    DIRECTION INPUT ;
    USE SIGNAL ;
    PORT
      LAYER M5 ;
        RECT  71.28 -0.072 71.304 0.072 ;
    END
  END a[301]
  PIN a[302]
    DIRECTION INPUT ;
    USE SIGNAL ;
    PORT
      LAYER M5 ;
        RECT  71.472 -0.072 71.496 0.072 ;
    END
  END a[302]
  PIN a[303]
    DIRECTION INPUT ;
    USE SIGNAL ;
    PORT
      LAYER M5 ;
        RECT  71.664 -0.072 71.688 0.072 ;
    END
  END a[303]
  PIN a[304]
    DIRECTION INPUT ;
    USE SIGNAL ;
    PORT
      LAYER M5 ;
        RECT  71.856 -0.072 71.88 0.072 ;
    END
  END a[304]
  PIN a[305]
    DIRECTION INPUT ;
    USE SIGNAL ;
    PORT
      LAYER M5 ;
        RECT  72.048 -0.072 72.072 0.072 ;
    END
  END a[305]
  PIN a[306]
    DIRECTION INPUT ;
    USE SIGNAL ;
    PORT
      LAYER M5 ;
        RECT  72.24 -0.072 72.264 0.072 ;
    END
  END a[306]
  PIN a[307]
    DIRECTION INPUT ;
    USE SIGNAL ;
    PORT
      LAYER M5 ;
        RECT  72.432 -0.072 72.456 0.072 ;
    END
  END a[307]
  PIN a[308]
    DIRECTION INPUT ;
    USE SIGNAL ;
    PORT
      LAYER M5 ;
        RECT  72.624 -0.072 72.648 0.072 ;
    END
  END a[308]
  PIN a[309]
    DIRECTION INPUT ;
    USE SIGNAL ;
    PORT
      LAYER M5 ;
        RECT  72.816 -0.072 72.84 0.072 ;
    END
  END a[309]
  PIN a[30]
    DIRECTION INPUT ;
    USE SIGNAL ;
    PORT
      LAYER M5 ;
        RECT  19.248 -0.072 19.272 0.072 ;
    END
  END a[30]
  PIN a[310]
    DIRECTION INPUT ;
    USE SIGNAL ;
    PORT
      LAYER M5 ;
        RECT  73.008 -0.072 73.032 0.072 ;
    END
  END a[310]
  PIN a[311]
    DIRECTION INPUT ;
    USE SIGNAL ;
    PORT
      LAYER M5 ;
        RECT  73.2 -0.072 73.224 0.072 ;
    END
  END a[311]
  PIN a[312]
    DIRECTION INPUT ;
    USE SIGNAL ;
    PORT
      LAYER M5 ;
        RECT  73.392 -0.072 73.416 0.072 ;
    END
  END a[312]
  PIN a[313]
    DIRECTION INPUT ;
    USE SIGNAL ;
    PORT
      LAYER M5 ;
        RECT  73.584 -0.072 73.608 0.072 ;
    END
  END a[313]
  PIN a[314]
    DIRECTION INPUT ;
    USE SIGNAL ;
    PORT
      LAYER M5 ;
        RECT  73.776 -0.072 73.8 0.072 ;
    END
  END a[314]
  PIN a[315]
    DIRECTION INPUT ;
    USE SIGNAL ;
    PORT
      LAYER M5 ;
        RECT  73.968 -0.072 73.992 0.072 ;
    END
  END a[315]
  PIN a[316]
    DIRECTION INPUT ;
    USE SIGNAL ;
    PORT
      LAYER M5 ;
        RECT  74.16 -0.072 74.184 0.072 ;
    END
  END a[316]
  PIN a[317]
    DIRECTION INPUT ;
    USE SIGNAL ;
    PORT
      LAYER M5 ;
        RECT  74.352 -0.072 74.376 0.072 ;
    END
  END a[317]
  PIN a[318]
    DIRECTION INPUT ;
    USE SIGNAL ;
    PORT
      LAYER M5 ;
        RECT  74.544 -0.072 74.568 0.072 ;
    END
  END a[318]
  PIN a[319]
    DIRECTION INPUT ;
    USE SIGNAL ;
    PORT
      LAYER M5 ;
        RECT  74.736 -0.072 74.76 0.072 ;
    END
  END a[319]
  PIN a[31]
    DIRECTION INPUT ;
    USE SIGNAL ;
    PORT
      LAYER M5 ;
        RECT  19.44 -0.072 19.464 0.072 ;
    END
  END a[31]
  PIN a[320]
    DIRECTION INPUT ;
    USE SIGNAL ;
    PORT
      LAYER M5 ;
        RECT  74.928 -0.072 74.952 0.072 ;
    END
  END a[320]
  PIN a[321]
    DIRECTION INPUT ;
    USE SIGNAL ;
    PORT
      LAYER M5 ;
        RECT  75.12 -0.072 75.144 0.072 ;
    END
  END a[321]
  PIN a[322]
    DIRECTION INPUT ;
    USE SIGNAL ;
    PORT
      LAYER M5 ;
        RECT  75.312 -0.072 75.336 0.072 ;
    END
  END a[322]
  PIN a[323]
    DIRECTION INPUT ;
    USE SIGNAL ;
    PORT
      LAYER M5 ;
        RECT  75.504 -0.072 75.528 0.072 ;
    END
  END a[323]
  PIN a[324]
    DIRECTION INPUT ;
    USE SIGNAL ;
    PORT
      LAYER M5 ;
        RECT  75.696 -0.072 75.72 0.072 ;
    END
  END a[324]
  PIN a[325]
    DIRECTION INPUT ;
    USE SIGNAL ;
    PORT
      LAYER M5 ;
        RECT  75.888 -0.072 75.912 0.072 ;
    END
  END a[325]
  PIN a[326]
    DIRECTION INPUT ;
    USE SIGNAL ;
    PORT
      LAYER M5 ;
        RECT  76.08 -0.072 76.104 0.072 ;
    END
  END a[326]
  PIN a[327]
    DIRECTION INPUT ;
    USE SIGNAL ;
    PORT
      LAYER M5 ;
        RECT  76.272 -0.072 76.296 0.072 ;
    END
  END a[327]
  PIN a[328]
    DIRECTION INPUT ;
    USE SIGNAL ;
    PORT
      LAYER M5 ;
        RECT  76.464 -0.072 76.488 0.072 ;
    END
  END a[328]
  PIN a[329]
    DIRECTION INPUT ;
    USE SIGNAL ;
    PORT
      LAYER M5 ;
        RECT  76.656 -0.072 76.68 0.072 ;
    END
  END a[329]
  PIN a[32]
    DIRECTION INPUT ;
    USE SIGNAL ;
    PORT
      LAYER M5 ;
        RECT  19.632 -0.072 19.656 0.072 ;
    END
  END a[32]
  PIN a[330]
    DIRECTION INPUT ;
    USE SIGNAL ;
    PORT
      LAYER M5 ;
        RECT  76.848 -0.072 76.872 0.072 ;
    END
  END a[330]
  PIN a[331]
    DIRECTION INPUT ;
    USE SIGNAL ;
    PORT
      LAYER M5 ;
        RECT  77.04 -0.072 77.064 0.072 ;
    END
  END a[331]
  PIN a[332]
    DIRECTION INPUT ;
    USE SIGNAL ;
    PORT
      LAYER M5 ;
        RECT  77.232 -0.072 77.256 0.072 ;
    END
  END a[332]
  PIN a[333]
    DIRECTION INPUT ;
    USE SIGNAL ;
    PORT
      LAYER M5 ;
        RECT  77.424 -0.072 77.448 0.072 ;
    END
  END a[333]
  PIN a[334]
    DIRECTION INPUT ;
    USE SIGNAL ;
    PORT
      LAYER M5 ;
        RECT  77.616 -0.072 77.64 0.072 ;
    END
  END a[334]
  PIN a[335]
    DIRECTION INPUT ;
    USE SIGNAL ;
    PORT
      LAYER M5 ;
        RECT  77.808 -0.072 77.832 0.072 ;
    END
  END a[335]
  PIN a[336]
    DIRECTION INPUT ;
    USE SIGNAL ;
    PORT
      LAYER M5 ;
        RECT  78 -0.072 78.024 0.072 ;
    END
  END a[336]
  PIN a[337]
    DIRECTION INPUT ;
    USE SIGNAL ;
    PORT
      LAYER M5 ;
        RECT  78.192 -0.072 78.216 0.072 ;
    END
  END a[337]
  PIN a[338]
    DIRECTION INPUT ;
    USE SIGNAL ;
    PORT
      LAYER M5 ;
        RECT  78.384 -0.072 78.408 0.072 ;
    END
  END a[338]
  PIN a[339]
    DIRECTION INPUT ;
    USE SIGNAL ;
    PORT
      LAYER M5 ;
        RECT  78.576 -0.072 78.6 0.072 ;
    END
  END a[339]
  PIN a[33]
    DIRECTION INPUT ;
    USE SIGNAL ;
    PORT
      LAYER M5 ;
        RECT  19.824 -0.072 19.848 0.072 ;
    END
  END a[33]
  PIN a[340]
    DIRECTION INPUT ;
    USE SIGNAL ;
    PORT
      LAYER M5 ;
        RECT  78.768 -0.072 78.792 0.072 ;
    END
  END a[340]
  PIN a[341]
    DIRECTION INPUT ;
    USE SIGNAL ;
    PORT
      LAYER M5 ;
        RECT  78.96 -0.072 78.984 0.072 ;
    END
  END a[341]
  PIN a[342]
    DIRECTION INPUT ;
    USE SIGNAL ;
    PORT
      LAYER M5 ;
        RECT  79.152 -0.072 79.176 0.072 ;
    END
  END a[342]
  PIN a[343]
    DIRECTION INPUT ;
    USE SIGNAL ;
    PORT
      LAYER M5 ;
        RECT  79.344 -0.072 79.368 0.072 ;
    END
  END a[343]
  PIN a[344]
    DIRECTION INPUT ;
    USE SIGNAL ;
    PORT
      LAYER M5 ;
        RECT  79.536 -0.072 79.56 0.072 ;
    END
  END a[344]
  PIN a[345]
    DIRECTION INPUT ;
    USE SIGNAL ;
    PORT
      LAYER M5 ;
        RECT  79.728 -0.072 79.752 0.072 ;
    END
  END a[345]
  PIN a[346]
    DIRECTION INPUT ;
    USE SIGNAL ;
    PORT
      LAYER M5 ;
        RECT  79.92 -0.072 79.944 0.072 ;
    END
  END a[346]
  PIN a[347]
    DIRECTION INPUT ;
    USE SIGNAL ;
    PORT
      LAYER M5 ;
        RECT  80.112 -0.072 80.136 0.072 ;
    END
  END a[347]
  PIN a[348]
    DIRECTION INPUT ;
    USE SIGNAL ;
    PORT
      LAYER M5 ;
        RECT  80.304 -0.072 80.328 0.072 ;
    END
  END a[348]
  PIN a[349]
    DIRECTION INPUT ;
    USE SIGNAL ;
    PORT
      LAYER M5 ;
        RECT  80.496 -0.072 80.52 0.072 ;
    END
  END a[349]
  PIN a[34]
    DIRECTION INPUT ;
    USE SIGNAL ;
    PORT
      LAYER M5 ;
        RECT  20.016 -0.072 20.04 0.072 ;
    END
  END a[34]
  PIN a[350]
    DIRECTION INPUT ;
    USE SIGNAL ;
    PORT
      LAYER M5 ;
        RECT  80.688 -0.072 80.712 0.072 ;
    END
  END a[350]
  PIN a[351]
    DIRECTION INPUT ;
    USE SIGNAL ;
    PORT
      LAYER M5 ;
        RECT  80.88 -0.072 80.904 0.072 ;
    END
  END a[351]
  PIN a[352]
    DIRECTION INPUT ;
    USE SIGNAL ;
    PORT
      LAYER M5 ;
        RECT  81.072 -0.072 81.096 0.072 ;
    END
  END a[352]
  PIN a[353]
    DIRECTION INPUT ;
    USE SIGNAL ;
    PORT
      LAYER M5 ;
        RECT  81.264 -0.072 81.288 0.072 ;
    END
  END a[353]
  PIN a[354]
    DIRECTION INPUT ;
    USE SIGNAL ;
    PORT
      LAYER M5 ;
        RECT  81.456 -0.072 81.48 0.072 ;
    END
  END a[354]
  PIN a[355]
    DIRECTION INPUT ;
    USE SIGNAL ;
    PORT
      LAYER M5 ;
        RECT  81.648 -0.072 81.672 0.072 ;
    END
  END a[355]
  PIN a[356]
    DIRECTION INPUT ;
    USE SIGNAL ;
    PORT
      LAYER M5 ;
        RECT  81.84 -0.072 81.864 0.072 ;
    END
  END a[356]
  PIN a[357]
    DIRECTION INPUT ;
    USE SIGNAL ;
    PORT
      LAYER M5 ;
        RECT  82.032 -0.072 82.056 0.072 ;
    END
  END a[357]
  PIN a[358]
    DIRECTION INPUT ;
    USE SIGNAL ;
    PORT
      LAYER M5 ;
        RECT  82.224 -0.072 82.248 0.072 ;
    END
  END a[358]
  PIN a[359]
    DIRECTION INPUT ;
    USE SIGNAL ;
    PORT
      LAYER M5 ;
        RECT  82.416 -0.072 82.44 0.072 ;
    END
  END a[359]
  PIN a[35]
    DIRECTION INPUT ;
    USE SIGNAL ;
    PORT
      LAYER M5 ;
        RECT  20.208 -0.072 20.232 0.072 ;
    END
  END a[35]
  PIN a[360]
    DIRECTION INPUT ;
    USE SIGNAL ;
    PORT
      LAYER M5 ;
        RECT  82.608 -0.072 82.632 0.072 ;
    END
  END a[360]
  PIN a[361]
    DIRECTION INPUT ;
    USE SIGNAL ;
    PORT
      LAYER M5 ;
        RECT  82.8 -0.072 82.824 0.072 ;
    END
  END a[361]
  PIN a[362]
    DIRECTION INPUT ;
    USE SIGNAL ;
    PORT
      LAYER M5 ;
        RECT  82.992 -0.072 83.016 0.072 ;
    END
  END a[362]
  PIN a[363]
    DIRECTION INPUT ;
    USE SIGNAL ;
    PORT
      LAYER M5 ;
        RECT  83.184 -0.072 83.208 0.072 ;
    END
  END a[363]
  PIN a[364]
    DIRECTION INPUT ;
    USE SIGNAL ;
    PORT
      LAYER M5 ;
        RECT  83.376 -0.072 83.4 0.072 ;
    END
  END a[364]
  PIN a[365]
    DIRECTION INPUT ;
    USE SIGNAL ;
    PORT
      LAYER M5 ;
        RECT  83.568 -0.072 83.592 0.072 ;
    END
  END a[365]
  PIN a[366]
    DIRECTION INPUT ;
    USE SIGNAL ;
    PORT
      LAYER M5 ;
        RECT  83.76 -0.072 83.784 0.072 ;
    END
  END a[366]
  PIN a[367]
    DIRECTION INPUT ;
    USE SIGNAL ;
    PORT
      LAYER M5 ;
        RECT  83.952 -0.072 83.976 0.072 ;
    END
  END a[367]
  PIN a[368]
    DIRECTION INPUT ;
    USE SIGNAL ;
    PORT
      LAYER M5 ;
        RECT  84.144 -0.072 84.168 0.072 ;
    END
  END a[368]
  PIN a[369]
    DIRECTION INPUT ;
    USE SIGNAL ;
    PORT
      LAYER M5 ;
        RECT  84.336 -0.072 84.36 0.072 ;
    END
  END a[369]
  PIN a[36]
    DIRECTION INPUT ;
    USE SIGNAL ;
    PORT
      LAYER M5 ;
        RECT  20.4 -0.072 20.424 0.072 ;
    END
  END a[36]
  PIN a[370]
    DIRECTION INPUT ;
    USE SIGNAL ;
    PORT
      LAYER M5 ;
        RECT  84.528 -0.072 84.552 0.072 ;
    END
  END a[370]
  PIN a[371]
    DIRECTION INPUT ;
    USE SIGNAL ;
    PORT
      LAYER M5 ;
        RECT  84.72 -0.072 84.744 0.072 ;
    END
  END a[371]
  PIN a[372]
    DIRECTION INPUT ;
    USE SIGNAL ;
    PORT
      LAYER M5 ;
        RECT  84.912 -0.072 84.936 0.072 ;
    END
  END a[372]
  PIN a[373]
    DIRECTION INPUT ;
    USE SIGNAL ;
    PORT
      LAYER M5 ;
        RECT  85.104 -0.072 85.128 0.072 ;
    END
  END a[373]
  PIN a[374]
    DIRECTION INPUT ;
    USE SIGNAL ;
    PORT
      LAYER M5 ;
        RECT  85.296 -0.072 85.32 0.072 ;
    END
  END a[374]
  PIN a[375]
    DIRECTION INPUT ;
    USE SIGNAL ;
    PORT
      LAYER M5 ;
        RECT  85.488 -0.072 85.512 0.072 ;
    END
  END a[375]
  PIN a[376]
    DIRECTION INPUT ;
    USE SIGNAL ;
    PORT
      LAYER M5 ;
        RECT  85.68 -0.072 85.704 0.072 ;
    END
  END a[376]
  PIN a[377]
    DIRECTION INPUT ;
    USE SIGNAL ;
    PORT
      LAYER M5 ;
        RECT  85.872 -0.072 85.896 0.072 ;
    END
  END a[377]
  PIN a[378]
    DIRECTION INPUT ;
    USE SIGNAL ;
    PORT
      LAYER M5 ;
        RECT  86.064 -0.072 86.088 0.072 ;
    END
  END a[378]
  PIN a[379]
    DIRECTION INPUT ;
    USE SIGNAL ;
    PORT
      LAYER M5 ;
        RECT  86.256 -0.072 86.28 0.072 ;
    END
  END a[379]
  PIN a[37]
    DIRECTION INPUT ;
    USE SIGNAL ;
    PORT
      LAYER M5 ;
        RECT  20.592 -0.072 20.616 0.072 ;
    END
  END a[37]
  PIN a[380]
    DIRECTION INPUT ;
    USE SIGNAL ;
    PORT
      LAYER M5 ;
        RECT  86.448 -0.072 86.472 0.072 ;
    END
  END a[380]
  PIN a[381]
    DIRECTION INPUT ;
    USE SIGNAL ;
    PORT
      LAYER M5 ;
        RECT  86.64 -0.072 86.664 0.072 ;
    END
  END a[381]
  PIN a[382]
    DIRECTION INPUT ;
    USE SIGNAL ;
    PORT
      LAYER M5 ;
        RECT  86.832 -0.072 86.856 0.072 ;
    END
  END a[382]
  PIN a[383]
    DIRECTION INPUT ;
    USE SIGNAL ;
    PORT
      LAYER M5 ;
        RECT  87.024 -0.072 87.048 0.072 ;
    END
  END a[383]
  PIN a[384]
    DIRECTION INPUT ;
    USE SIGNAL ;
    PORT
      LAYER M5 ;
        RECT  87.216 -0.072 87.24 0.072 ;
    END
  END a[384]
  PIN a[385]
    DIRECTION INPUT ;
    USE SIGNAL ;
    PORT
      LAYER M5 ;
        RECT  87.408 -0.072 87.432 0.072 ;
    END
  END a[385]
  PIN a[386]
    DIRECTION INPUT ;
    USE SIGNAL ;
    PORT
      LAYER M5 ;
        RECT  87.6 -0.072 87.624 0.072 ;
    END
  END a[386]
  PIN a[387]
    DIRECTION INPUT ;
    USE SIGNAL ;
    PORT
      LAYER M5 ;
        RECT  87.792 -0.072 87.816 0.072 ;
    END
  END a[387]
  PIN a[388]
    DIRECTION INPUT ;
    USE SIGNAL ;
    PORT
      LAYER M5 ;
        RECT  87.984 -0.072 88.008 0.072 ;
    END
  END a[388]
  PIN a[389]
    DIRECTION INPUT ;
    USE SIGNAL ;
    PORT
      LAYER M5 ;
        RECT  88.176 -0.072 88.2 0.072 ;
    END
  END a[389]
  PIN a[38]
    DIRECTION INPUT ;
    USE SIGNAL ;
    PORT
      LAYER M5 ;
        RECT  20.784 -0.072 20.808 0.072 ;
    END
  END a[38]
  PIN a[390]
    DIRECTION INPUT ;
    USE SIGNAL ;
    PORT
      LAYER M5 ;
        RECT  88.368 -0.072 88.392 0.072 ;
    END
  END a[390]
  PIN a[391]
    DIRECTION INPUT ;
    USE SIGNAL ;
    PORT
      LAYER M5 ;
        RECT  88.56 -0.072 88.584 0.072 ;
    END
  END a[391]
  PIN a[392]
    DIRECTION INPUT ;
    USE SIGNAL ;
    PORT
      LAYER M5 ;
        RECT  88.752 -0.072 88.776 0.072 ;
    END
  END a[392]
  PIN a[393]
    DIRECTION INPUT ;
    USE SIGNAL ;
    PORT
      LAYER M5 ;
        RECT  88.944 -0.072 88.968 0.072 ;
    END
  END a[393]
  PIN a[394]
    DIRECTION INPUT ;
    USE SIGNAL ;
    PORT
      LAYER M5 ;
        RECT  89.136 -0.072 89.16 0.072 ;
    END
  END a[394]
  PIN a[395]
    DIRECTION INPUT ;
    USE SIGNAL ;
    PORT
      LAYER M5 ;
        RECT  89.328 -0.072 89.352 0.072 ;
    END
  END a[395]
  PIN a[396]
    DIRECTION INPUT ;
    USE SIGNAL ;
    PORT
      LAYER M5 ;
        RECT  89.52 -0.072 89.544 0.072 ;
    END
  END a[396]
  PIN a[397]
    DIRECTION INPUT ;
    USE SIGNAL ;
    PORT
      LAYER M5 ;
        RECT  89.712 -0.072 89.736 0.072 ;
    END
  END a[397]
  PIN a[398]
    DIRECTION INPUT ;
    USE SIGNAL ;
    PORT
      LAYER M5 ;
        RECT  89.904 -0.072 89.928 0.072 ;
    END
  END a[398]
  PIN a[399]
    DIRECTION INPUT ;
    USE SIGNAL ;
    PORT
      LAYER M5 ;
        RECT  90.096 -0.072 90.12 0.072 ;
    END
  END a[399]
  PIN a[39]
    DIRECTION INPUT ;
    USE SIGNAL ;
    PORT
      LAYER M5 ;
        RECT  20.976 -0.072 21 0.072 ;
    END
  END a[39]
  PIN a[3]
    DIRECTION INPUT ;
    USE SIGNAL ;
    PORT
      LAYER M5 ;
        RECT  14.064 -0.072 14.088 0.072 ;
    END
  END a[3]
  PIN a[400]
    DIRECTION INPUT ;
    USE SIGNAL ;
    PORT
      LAYER M5 ;
        RECT  90.288 -0.072 90.312 0.072 ;
    END
  END a[400]
  PIN a[401]
    DIRECTION INPUT ;
    USE SIGNAL ;
    PORT
      LAYER M5 ;
        RECT  90.48 -0.072 90.504 0.072 ;
    END
  END a[401]
  PIN a[402]
    DIRECTION INPUT ;
    USE SIGNAL ;
    PORT
      LAYER M5 ;
        RECT  90.672 -0.072 90.696 0.072 ;
    END
  END a[402]
  PIN a[403]
    DIRECTION INPUT ;
    USE SIGNAL ;
    PORT
      LAYER M5 ;
        RECT  90.864 -0.072 90.888 0.072 ;
    END
  END a[403]
  PIN a[404]
    DIRECTION INPUT ;
    USE SIGNAL ;
    PORT
      LAYER M5 ;
        RECT  91.056 -0.072 91.08 0.072 ;
    END
  END a[404]
  PIN a[405]
    DIRECTION INPUT ;
    USE SIGNAL ;
    PORT
      LAYER M5 ;
        RECT  91.248 -0.072 91.272 0.072 ;
    END
  END a[405]
  PIN a[406]
    DIRECTION INPUT ;
    USE SIGNAL ;
    PORT
      LAYER M5 ;
        RECT  91.44 -0.072 91.464 0.072 ;
    END
  END a[406]
  PIN a[407]
    DIRECTION INPUT ;
    USE SIGNAL ;
    PORT
      LAYER M5 ;
        RECT  91.632 -0.072 91.656 0.072 ;
    END
  END a[407]
  PIN a[408]
    DIRECTION INPUT ;
    USE SIGNAL ;
    PORT
      LAYER M5 ;
        RECT  91.824 -0.072 91.848 0.072 ;
    END
  END a[408]
  PIN a[409]
    DIRECTION INPUT ;
    USE SIGNAL ;
    PORT
      LAYER M5 ;
        RECT  92.016 -0.072 92.04 0.072 ;
    END
  END a[409]
  PIN a[40]
    DIRECTION INPUT ;
    USE SIGNAL ;
    PORT
      LAYER M5 ;
        RECT  21.168 -0.072 21.192 0.072 ;
    END
  END a[40]
  PIN a[410]
    DIRECTION INPUT ;
    USE SIGNAL ;
    PORT
      LAYER M5 ;
        RECT  92.208 -0.072 92.232 0.072 ;
    END
  END a[410]
  PIN a[411]
    DIRECTION INPUT ;
    USE SIGNAL ;
    PORT
      LAYER M5 ;
        RECT  92.4 -0.072 92.424 0.072 ;
    END
  END a[411]
  PIN a[412]
    DIRECTION INPUT ;
    USE SIGNAL ;
    PORT
      LAYER M5 ;
        RECT  92.592 -0.072 92.616 0.072 ;
    END
  END a[412]
  PIN a[413]
    DIRECTION INPUT ;
    USE SIGNAL ;
    PORT
      LAYER M5 ;
        RECT  92.784 -0.072 92.808 0.072 ;
    END
  END a[413]
  PIN a[414]
    DIRECTION INPUT ;
    USE SIGNAL ;
    PORT
      LAYER M5 ;
        RECT  92.976 -0.072 93 0.072 ;
    END
  END a[414]
  PIN a[415]
    DIRECTION INPUT ;
    USE SIGNAL ;
    PORT
      LAYER M5 ;
        RECT  93.168 -0.072 93.192 0.072 ;
    END
  END a[415]
  PIN a[416]
    DIRECTION INPUT ;
    USE SIGNAL ;
    PORT
      LAYER M5 ;
        RECT  93.36 -0.072 93.384 0.072 ;
    END
  END a[416]
  PIN a[417]
    DIRECTION INPUT ;
    USE SIGNAL ;
    PORT
      LAYER M5 ;
        RECT  93.552 -0.072 93.576 0.072 ;
    END
  END a[417]
  PIN a[418]
    DIRECTION INPUT ;
    USE SIGNAL ;
    PORT
      LAYER M5 ;
        RECT  93.744 -0.072 93.768 0.072 ;
    END
  END a[418]
  PIN a[419]
    DIRECTION INPUT ;
    USE SIGNAL ;
    PORT
      LAYER M5 ;
        RECT  93.936 -0.072 93.96 0.072 ;
    END
  END a[419]
  PIN a[41]
    DIRECTION INPUT ;
    USE SIGNAL ;
    PORT
      LAYER M5 ;
        RECT  21.36 -0.072 21.384 0.072 ;
    END
  END a[41]
  PIN a[420]
    DIRECTION INPUT ;
    USE SIGNAL ;
    PORT
      LAYER M5 ;
        RECT  94.128 -0.072 94.152 0.072 ;
    END
  END a[420]
  PIN a[421]
    DIRECTION INPUT ;
    USE SIGNAL ;
    PORT
      LAYER M5 ;
        RECT  94.32 -0.072 94.344 0.072 ;
    END
  END a[421]
  PIN a[422]
    DIRECTION INPUT ;
    USE SIGNAL ;
    PORT
      LAYER M5 ;
        RECT  94.512 -0.072 94.536 0.072 ;
    END
  END a[422]
  PIN a[423]
    DIRECTION INPUT ;
    USE SIGNAL ;
    PORT
      LAYER M5 ;
        RECT  94.704 -0.072 94.728 0.072 ;
    END
  END a[423]
  PIN a[424]
    DIRECTION INPUT ;
    USE SIGNAL ;
    PORT
      LAYER M5 ;
        RECT  94.896 -0.072 94.92 0.072 ;
    END
  END a[424]
  PIN a[425]
    DIRECTION INPUT ;
    USE SIGNAL ;
    PORT
      LAYER M5 ;
        RECT  95.088 -0.072 95.112 0.072 ;
    END
  END a[425]
  PIN a[426]
    DIRECTION INPUT ;
    USE SIGNAL ;
    PORT
      LAYER M5 ;
        RECT  95.28 -0.072 95.304 0.072 ;
    END
  END a[426]
  PIN a[427]
    DIRECTION INPUT ;
    USE SIGNAL ;
    PORT
      LAYER M5 ;
        RECT  95.472 -0.072 95.496 0.072 ;
    END
  END a[427]
  PIN a[428]
    DIRECTION INPUT ;
    USE SIGNAL ;
    PORT
      LAYER M5 ;
        RECT  95.664 -0.072 95.688 0.072 ;
    END
  END a[428]
  PIN a[429]
    DIRECTION INPUT ;
    USE SIGNAL ;
    PORT
      LAYER M5 ;
        RECT  95.856 -0.072 95.88 0.072 ;
    END
  END a[429]
  PIN a[42]
    DIRECTION INPUT ;
    USE SIGNAL ;
    PORT
      LAYER M5 ;
        RECT  21.552 -0.072 21.576 0.072 ;
    END
  END a[42]
  PIN a[430]
    DIRECTION INPUT ;
    USE SIGNAL ;
    PORT
      LAYER M5 ;
        RECT  96.048 -0.072 96.072 0.072 ;
    END
  END a[430]
  PIN a[431]
    DIRECTION INPUT ;
    USE SIGNAL ;
    PORT
      LAYER M5 ;
        RECT  96.24 -0.072 96.264 0.072 ;
    END
  END a[431]
  PIN a[432]
    DIRECTION INPUT ;
    USE SIGNAL ;
    PORT
      LAYER M5 ;
        RECT  96.432 -0.072 96.456 0.072 ;
    END
  END a[432]
  PIN a[433]
    DIRECTION INPUT ;
    USE SIGNAL ;
    PORT
      LAYER M5 ;
        RECT  96.624 -0.072 96.648 0.072 ;
    END
  END a[433]
  PIN a[434]
    DIRECTION INPUT ;
    USE SIGNAL ;
    PORT
      LAYER M5 ;
        RECT  96.816 -0.072 96.84 0.072 ;
    END
  END a[434]
  PIN a[435]
    DIRECTION INPUT ;
    USE SIGNAL ;
    PORT
      LAYER M5 ;
        RECT  97.008 -0.072 97.032 0.072 ;
    END
  END a[435]
  PIN a[436]
    DIRECTION INPUT ;
    USE SIGNAL ;
    PORT
      LAYER M5 ;
        RECT  97.2 -0.072 97.224 0.072 ;
    END
  END a[436]
  PIN a[437]
    DIRECTION INPUT ;
    USE SIGNAL ;
    PORT
      LAYER M5 ;
        RECT  97.392 -0.072 97.416 0.072 ;
    END
  END a[437]
  PIN a[438]
    DIRECTION INPUT ;
    USE SIGNAL ;
    PORT
      LAYER M5 ;
        RECT  97.584 -0.072 97.608 0.072 ;
    END
  END a[438]
  PIN a[439]
    DIRECTION INPUT ;
    USE SIGNAL ;
    PORT
      LAYER M5 ;
        RECT  97.776 -0.072 97.8 0.072 ;
    END
  END a[439]
  PIN a[43]
    DIRECTION INPUT ;
    USE SIGNAL ;
    PORT
      LAYER M5 ;
        RECT  21.744 -0.072 21.768 0.072 ;
    END
  END a[43]
  PIN a[440]
    DIRECTION INPUT ;
    USE SIGNAL ;
    PORT
      LAYER M5 ;
        RECT  97.968 -0.072 97.992 0.072 ;
    END
  END a[440]
  PIN a[441]
    DIRECTION INPUT ;
    USE SIGNAL ;
    PORT
      LAYER M5 ;
        RECT  98.16 -0.072 98.184 0.072 ;
    END
  END a[441]
  PIN a[442]
    DIRECTION INPUT ;
    USE SIGNAL ;
    PORT
      LAYER M5 ;
        RECT  98.352 -0.072 98.376 0.072 ;
    END
  END a[442]
  PIN a[443]
    DIRECTION INPUT ;
    USE SIGNAL ;
    PORT
      LAYER M5 ;
        RECT  98.544 -0.072 98.568 0.072 ;
    END
  END a[443]
  PIN a[444]
    DIRECTION INPUT ;
    USE SIGNAL ;
    PORT
      LAYER M5 ;
        RECT  98.736 -0.072 98.76 0.072 ;
    END
  END a[444]
  PIN a[445]
    DIRECTION INPUT ;
    USE SIGNAL ;
    PORT
      LAYER M5 ;
        RECT  98.928 -0.072 98.952 0.072 ;
    END
  END a[445]
  PIN a[446]
    DIRECTION INPUT ;
    USE SIGNAL ;
    PORT
      LAYER M5 ;
        RECT  99.12 -0.072 99.144 0.072 ;
    END
  END a[446]
  PIN a[447]
    DIRECTION INPUT ;
    USE SIGNAL ;
    PORT
      LAYER M5 ;
        RECT  99.312 -0.072 99.336 0.072 ;
    END
  END a[447]
  PIN a[448]
    DIRECTION INPUT ;
    USE SIGNAL ;
    PORT
      LAYER M5 ;
        RECT  99.504 -0.072 99.528 0.072 ;
    END
  END a[448]
  PIN a[449]
    DIRECTION INPUT ;
    USE SIGNAL ;
    PORT
      LAYER M5 ;
        RECT  99.696 -0.072 99.72 0.072 ;
    END
  END a[449]
  PIN a[44]
    DIRECTION INPUT ;
    USE SIGNAL ;
    PORT
      LAYER M5 ;
        RECT  21.936 -0.072 21.96 0.072 ;
    END
  END a[44]
  PIN a[450]
    DIRECTION INPUT ;
    USE SIGNAL ;
    PORT
      LAYER M5 ;
        RECT  99.888 -0.072 99.912 0.072 ;
    END
  END a[450]
  PIN a[451]
    DIRECTION INPUT ;
    USE SIGNAL ;
    PORT
      LAYER M5 ;
        RECT  100.08 -0.072 100.104 0.072 ;
    END
  END a[451]
  PIN a[452]
    DIRECTION INPUT ;
    USE SIGNAL ;
    PORT
      LAYER M5 ;
        RECT  100.272 -0.072 100.296 0.072 ;
    END
  END a[452]
  PIN a[453]
    DIRECTION INPUT ;
    USE SIGNAL ;
    PORT
      LAYER M5 ;
        RECT  100.464 -0.072 100.488 0.072 ;
    END
  END a[453]
  PIN a[454]
    DIRECTION INPUT ;
    USE SIGNAL ;
    PORT
      LAYER M5 ;
        RECT  100.656 -0.072 100.68 0.072 ;
    END
  END a[454]
  PIN a[455]
    DIRECTION INPUT ;
    USE SIGNAL ;
    PORT
      LAYER M5 ;
        RECT  100.848 -0.072 100.872 0.072 ;
    END
  END a[455]
  PIN a[456]
    DIRECTION INPUT ;
    USE SIGNAL ;
    PORT
      LAYER M5 ;
        RECT  101.04 -0.072 101.064 0.072 ;
    END
  END a[456]
  PIN a[457]
    DIRECTION INPUT ;
    USE SIGNAL ;
    PORT
      LAYER M5 ;
        RECT  101.232 -0.072 101.256 0.072 ;
    END
  END a[457]
  PIN a[458]
    DIRECTION INPUT ;
    USE SIGNAL ;
    PORT
      LAYER M5 ;
        RECT  101.424 -0.072 101.448 0.072 ;
    END
  END a[458]
  PIN a[459]
    DIRECTION INPUT ;
    USE SIGNAL ;
    PORT
      LAYER M5 ;
        RECT  101.616 -0.072 101.64 0.072 ;
    END
  END a[459]
  PIN a[45]
    DIRECTION INPUT ;
    USE SIGNAL ;
    PORT
      LAYER M5 ;
        RECT  22.128 -0.072 22.152 0.072 ;
    END
  END a[45]
  PIN a[460]
    DIRECTION INPUT ;
    USE SIGNAL ;
    PORT
      LAYER M5 ;
        RECT  101.808 -0.072 101.832 0.072 ;
    END
  END a[460]
  PIN a[461]
    DIRECTION INPUT ;
    USE SIGNAL ;
    PORT
      LAYER M5 ;
        RECT  102 -0.072 102.024 0.072 ;
    END
  END a[461]
  PIN a[462]
    DIRECTION INPUT ;
    USE SIGNAL ;
    PORT
      LAYER M5 ;
        RECT  102.192 -0.072 102.216 0.072 ;
    END
  END a[462]
  PIN a[463]
    DIRECTION INPUT ;
    USE SIGNAL ;
    PORT
      LAYER M5 ;
        RECT  102.384 -0.072 102.408 0.072 ;
    END
  END a[463]
  PIN a[464]
    DIRECTION INPUT ;
    USE SIGNAL ;
    PORT
      LAYER M5 ;
        RECT  102.576 -0.072 102.6 0.072 ;
    END
  END a[464]
  PIN a[465]
    DIRECTION INPUT ;
    USE SIGNAL ;
    PORT
      LAYER M5 ;
        RECT  102.768 -0.072 102.792 0.072 ;
    END
  END a[465]
  PIN a[466]
    DIRECTION INPUT ;
    USE SIGNAL ;
    PORT
      LAYER M5 ;
        RECT  102.96 -0.072 102.984 0.072 ;
    END
  END a[466]
  PIN a[467]
    DIRECTION INPUT ;
    USE SIGNAL ;
    PORT
      LAYER M5 ;
        RECT  103.152 -0.072 103.176 0.072 ;
    END
  END a[467]
  PIN a[468]
    DIRECTION INPUT ;
    USE SIGNAL ;
    PORT
      LAYER M5 ;
        RECT  103.344 -0.072 103.368 0.072 ;
    END
  END a[468]
  PIN a[469]
    DIRECTION INPUT ;
    USE SIGNAL ;
    PORT
      LAYER M5 ;
        RECT  103.536 -0.072 103.56 0.072 ;
    END
  END a[469]
  PIN a[46]
    DIRECTION INPUT ;
    USE SIGNAL ;
    PORT
      LAYER M5 ;
        RECT  22.32 -0.072 22.344 0.072 ;
    END
  END a[46]
  PIN a[470]
    DIRECTION INPUT ;
    USE SIGNAL ;
    PORT
      LAYER M5 ;
        RECT  103.728 -0.072 103.752 0.072 ;
    END
  END a[470]
  PIN a[471]
    DIRECTION INPUT ;
    USE SIGNAL ;
    PORT
      LAYER M5 ;
        RECT  103.92 -0.072 103.944 0.072 ;
    END
  END a[471]
  PIN a[472]
    DIRECTION INPUT ;
    USE SIGNAL ;
    PORT
      LAYER M5 ;
        RECT  104.112 -0.072 104.136 0.072 ;
    END
  END a[472]
  PIN a[473]
    DIRECTION INPUT ;
    USE SIGNAL ;
    PORT
      LAYER M5 ;
        RECT  104.304 -0.072 104.328 0.072 ;
    END
  END a[473]
  PIN a[474]
    DIRECTION INPUT ;
    USE SIGNAL ;
    PORT
      LAYER M5 ;
        RECT  104.496 -0.072 104.52 0.072 ;
    END
  END a[474]
  PIN a[475]
    DIRECTION INPUT ;
    USE SIGNAL ;
    PORT
      LAYER M5 ;
        RECT  104.688 -0.072 104.712 0.072 ;
    END
  END a[475]
  PIN a[476]
    DIRECTION INPUT ;
    USE SIGNAL ;
    PORT
      LAYER M5 ;
        RECT  104.88 -0.072 104.904 0.072 ;
    END
  END a[476]
  PIN a[477]
    DIRECTION INPUT ;
    USE SIGNAL ;
    PORT
      LAYER M5 ;
        RECT  105.072 -0.072 105.096 0.072 ;
    END
  END a[477]
  PIN a[478]
    DIRECTION INPUT ;
    USE SIGNAL ;
    PORT
      LAYER M5 ;
        RECT  105.264 -0.072 105.288 0.072 ;
    END
  END a[478]
  PIN a[479]
    DIRECTION INPUT ;
    USE SIGNAL ;
    PORT
      LAYER M5 ;
        RECT  105.456 -0.072 105.48 0.072 ;
    END
  END a[479]
  PIN a[47]
    DIRECTION INPUT ;
    USE SIGNAL ;
    PORT
      LAYER M5 ;
        RECT  22.512 -0.072 22.536 0.072 ;
    END
  END a[47]
  PIN a[480]
    DIRECTION INPUT ;
    USE SIGNAL ;
    PORT
      LAYER M5 ;
        RECT  105.648 -0.072 105.672 0.072 ;
    END
  END a[480]
  PIN a[481]
    DIRECTION INPUT ;
    USE SIGNAL ;
    PORT
      LAYER M5 ;
        RECT  105.84 -0.072 105.864 0.072 ;
    END
  END a[481]
  PIN a[482]
    DIRECTION INPUT ;
    USE SIGNAL ;
    PORT
      LAYER M5 ;
        RECT  106.032 -0.072 106.056 0.072 ;
    END
  END a[482]
  PIN a[483]
    DIRECTION INPUT ;
    USE SIGNAL ;
    PORT
      LAYER M5 ;
        RECT  106.224 -0.072 106.248 0.072 ;
    END
  END a[483]
  PIN a[484]
    DIRECTION INPUT ;
    USE SIGNAL ;
    PORT
      LAYER M5 ;
        RECT  106.416 -0.072 106.44 0.072 ;
    END
  END a[484]
  PIN a[485]
    DIRECTION INPUT ;
    USE SIGNAL ;
    PORT
      LAYER M5 ;
        RECT  106.608 -0.072 106.632 0.072 ;
    END
  END a[485]
  PIN a[486]
    DIRECTION INPUT ;
    USE SIGNAL ;
    PORT
      LAYER M5 ;
        RECT  106.8 -0.072 106.824 0.072 ;
    END
  END a[486]
  PIN a[487]
    DIRECTION INPUT ;
    USE SIGNAL ;
    PORT
      LAYER M5 ;
        RECT  106.992 -0.072 107.016 0.072 ;
    END
  END a[487]
  PIN a[488]
    DIRECTION INPUT ;
    USE SIGNAL ;
    PORT
      LAYER M5 ;
        RECT  107.184 -0.072 107.208 0.072 ;
    END
  END a[488]
  PIN a[489]
    DIRECTION INPUT ;
    USE SIGNAL ;
    PORT
      LAYER M5 ;
        RECT  107.376 -0.072 107.4 0.072 ;
    END
  END a[489]
  PIN a[48]
    DIRECTION INPUT ;
    USE SIGNAL ;
    PORT
      LAYER M5 ;
        RECT  22.704 -0.072 22.728 0.072 ;
    END
  END a[48]
  PIN a[490]
    DIRECTION INPUT ;
    USE SIGNAL ;
    PORT
      LAYER M5 ;
        RECT  107.568 -0.072 107.592 0.072 ;
    END
  END a[490]
  PIN a[491]
    DIRECTION INPUT ;
    USE SIGNAL ;
    PORT
      LAYER M5 ;
        RECT  107.76 -0.072 107.784 0.072 ;
    END
  END a[491]
  PIN a[492]
    DIRECTION INPUT ;
    USE SIGNAL ;
    PORT
      LAYER M5 ;
        RECT  107.952 -0.072 107.976 0.072 ;
    END
  END a[492]
  PIN a[493]
    DIRECTION INPUT ;
    USE SIGNAL ;
    PORT
      LAYER M5 ;
        RECT  108.144 -0.072 108.168 0.072 ;
    END
  END a[493]
  PIN a[494]
    DIRECTION INPUT ;
    USE SIGNAL ;
    PORT
      LAYER M5 ;
        RECT  108.336 -0.072 108.36 0.072 ;
    END
  END a[494]
  PIN a[495]
    DIRECTION INPUT ;
    USE SIGNAL ;
    PORT
      LAYER M5 ;
        RECT  108.528 -0.072 108.552 0.072 ;
    END
  END a[495]
  PIN a[496]
    DIRECTION INPUT ;
    USE SIGNAL ;
    PORT
      LAYER M5 ;
        RECT  108.72 -0.072 108.744 0.072 ;
    END
  END a[496]
  PIN a[497]
    DIRECTION INPUT ;
    USE SIGNAL ;
    PORT
      LAYER M5 ;
        RECT  108.912 -0.072 108.936 0.072 ;
    END
  END a[497]
  PIN a[498]
    DIRECTION INPUT ;
    USE SIGNAL ;
    PORT
      LAYER M5 ;
        RECT  109.104 -0.072 109.128 0.072 ;
    END
  END a[498]
  PIN a[499]
    DIRECTION INPUT ;
    USE SIGNAL ;
    PORT
      LAYER M5 ;
        RECT  109.296 -0.072 109.32 0.072 ;
    END
  END a[499]
  PIN a[49]
    DIRECTION INPUT ;
    USE SIGNAL ;
    PORT
      LAYER M5 ;
        RECT  22.896 -0.072 22.92 0.072 ;
    END
  END a[49]
  PIN a[4]
    DIRECTION INPUT ;
    USE SIGNAL ;
    PORT
      LAYER M5 ;
        RECT  14.256 -0.072 14.28 0.072 ;
    END
  END a[4]
  PIN a[500]
    DIRECTION INPUT ;
    USE SIGNAL ;
    PORT
      LAYER M5 ;
        RECT  109.488 -0.072 109.512 0.072 ;
    END
  END a[500]
  PIN a[501]
    DIRECTION INPUT ;
    USE SIGNAL ;
    PORT
      LAYER M5 ;
        RECT  109.68 -0.072 109.704 0.072 ;
    END
  END a[501]
  PIN a[502]
    DIRECTION INPUT ;
    USE SIGNAL ;
    PORT
      LAYER M5 ;
        RECT  109.872 -0.072 109.896 0.072 ;
    END
  END a[502]
  PIN a[503]
    DIRECTION INPUT ;
    USE SIGNAL ;
    PORT
      LAYER M5 ;
        RECT  110.064 -0.072 110.088 0.072 ;
    END
  END a[503]
  PIN a[504]
    DIRECTION INPUT ;
    USE SIGNAL ;
    PORT
      LAYER M5 ;
        RECT  110.256 -0.072 110.28 0.072 ;
    END
  END a[504]
  PIN a[505]
    DIRECTION INPUT ;
    USE SIGNAL ;
    PORT
      LAYER M5 ;
        RECT  110.448 -0.072 110.472 0.072 ;
    END
  END a[505]
  PIN a[506]
    DIRECTION INPUT ;
    USE SIGNAL ;
    PORT
      LAYER M5 ;
        RECT  110.64 -0.072 110.664 0.072 ;
    END
  END a[506]
  PIN a[507]
    DIRECTION INPUT ;
    USE SIGNAL ;
    PORT
      LAYER M5 ;
        RECT  110.832 -0.072 110.856 0.072 ;
    END
  END a[507]
  PIN a[508]
    DIRECTION INPUT ;
    USE SIGNAL ;
    PORT
      LAYER M5 ;
        RECT  111.024 -0.072 111.048 0.072 ;
    END
  END a[508]
  PIN a[509]
    DIRECTION INPUT ;
    USE SIGNAL ;
    PORT
      LAYER M5 ;
        RECT  111.216 -0.072 111.24 0.072 ;
    END
  END a[509]
  PIN a[50]
    DIRECTION INPUT ;
    USE SIGNAL ;
    PORT
      LAYER M5 ;
        RECT  23.088 -0.072 23.112 0.072 ;
    END
  END a[50]
  PIN a[510]
    DIRECTION INPUT ;
    USE SIGNAL ;
    PORT
      LAYER M5 ;
        RECT  111.408 -0.072 111.432 0.072 ;
    END
  END a[510]
  PIN a[511]
    DIRECTION INPUT ;
    USE SIGNAL ;
    PORT
      LAYER M5 ;
        RECT  111.6 -0.072 111.624 0.072 ;
    END
  END a[511]
  PIN a[512]
    DIRECTION INPUT ;
    USE SIGNAL ;
    PORT
      LAYER M5 ;
        RECT  111.792 -0.072 111.816 0.072 ;
    END
  END a[512]
  PIN a[513]
    DIRECTION INPUT ;
    USE SIGNAL ;
    PORT
      LAYER M5 ;
        RECT  111.984 -0.072 112.008 0.072 ;
    END
  END a[513]
  PIN a[514]
    DIRECTION INPUT ;
    USE SIGNAL ;
    PORT
      LAYER M5 ;
        RECT  112.176 -0.072 112.2 0.072 ;
    END
  END a[514]
  PIN a[515]
    DIRECTION INPUT ;
    USE SIGNAL ;
    PORT
      LAYER M5 ;
        RECT  112.368 -0.072 112.392 0.072 ;
    END
  END a[515]
  PIN a[516]
    DIRECTION INPUT ;
    USE SIGNAL ;
    PORT
      LAYER M5 ;
        RECT  112.56 -0.072 112.584 0.072 ;
    END
  END a[516]
  PIN a[517]
    DIRECTION INPUT ;
    USE SIGNAL ;
    PORT
      LAYER M5 ;
        RECT  112.752 -0.072 112.776 0.072 ;
    END
  END a[517]
  PIN a[518]
    DIRECTION INPUT ;
    USE SIGNAL ;
    PORT
      LAYER M5 ;
        RECT  112.944 -0.072 112.968 0.072 ;
    END
  END a[518]
  PIN a[519]
    DIRECTION INPUT ;
    USE SIGNAL ;
    PORT
      LAYER M5 ;
        RECT  113.136 -0.072 113.16 0.072 ;
    END
  END a[519]
  PIN a[51]
    DIRECTION INPUT ;
    USE SIGNAL ;
    PORT
      LAYER M5 ;
        RECT  23.28 -0.072 23.304 0.072 ;
    END
  END a[51]
  PIN a[520]
    DIRECTION INPUT ;
    USE SIGNAL ;
    PORT
      LAYER M5 ;
        RECT  113.328 -0.072 113.352 0.072 ;
    END
  END a[520]
  PIN a[521]
    DIRECTION INPUT ;
    USE SIGNAL ;
    PORT
      LAYER M5 ;
        RECT  113.52 -0.072 113.544 0.072 ;
    END
  END a[521]
  PIN a[522]
    DIRECTION INPUT ;
    USE SIGNAL ;
    PORT
      LAYER M5 ;
        RECT  113.712 -0.072 113.736 0.072 ;
    END
  END a[522]
  PIN a[523]
    DIRECTION INPUT ;
    USE SIGNAL ;
    PORT
      LAYER M5 ;
        RECT  113.904 -0.072 113.928 0.072 ;
    END
  END a[523]
  PIN a[524]
    DIRECTION INPUT ;
    USE SIGNAL ;
    PORT
      LAYER M5 ;
        RECT  114.096 -0.072 114.12 0.072 ;
    END
  END a[524]
  PIN a[525]
    DIRECTION INPUT ;
    USE SIGNAL ;
    PORT
      LAYER M5 ;
        RECT  114.288 -0.072 114.312 0.072 ;
    END
  END a[525]
  PIN a[526]
    DIRECTION INPUT ;
    USE SIGNAL ;
    PORT
      LAYER M5 ;
        RECT  114.48 -0.072 114.504 0.072 ;
    END
  END a[526]
  PIN a[527]
    DIRECTION INPUT ;
    USE SIGNAL ;
    PORT
      LAYER M5 ;
        RECT  114.672 -0.072 114.696 0.072 ;
    END
  END a[527]
  PIN a[528]
    DIRECTION INPUT ;
    USE SIGNAL ;
    PORT
      LAYER M5 ;
        RECT  114.864 -0.072 114.888 0.072 ;
    END
  END a[528]
  PIN a[529]
    DIRECTION INPUT ;
    USE SIGNAL ;
    PORT
      LAYER M5 ;
        RECT  115.056 -0.072 115.08 0.072 ;
    END
  END a[529]
  PIN a[52]
    DIRECTION INPUT ;
    USE SIGNAL ;
    PORT
      LAYER M5 ;
        RECT  23.472 -0.072 23.496 0.072 ;
    END
  END a[52]
  PIN a[530]
    DIRECTION INPUT ;
    USE SIGNAL ;
    PORT
      LAYER M5 ;
        RECT  115.248 -0.072 115.272 0.072 ;
    END
  END a[530]
  PIN a[531]
    DIRECTION INPUT ;
    USE SIGNAL ;
    PORT
      LAYER M5 ;
        RECT  115.44 -0.072 115.464 0.072 ;
    END
  END a[531]
  PIN a[532]
    DIRECTION INPUT ;
    USE SIGNAL ;
    PORT
      LAYER M5 ;
        RECT  115.632 -0.072 115.656 0.072 ;
    END
  END a[532]
  PIN a[533]
    DIRECTION INPUT ;
    USE SIGNAL ;
    PORT
      LAYER M5 ;
        RECT  115.824 -0.072 115.848 0.072 ;
    END
  END a[533]
  PIN a[534]
    DIRECTION INPUT ;
    USE SIGNAL ;
    PORT
      LAYER M5 ;
        RECT  116.016 -0.072 116.04 0.072 ;
    END
  END a[534]
  PIN a[53]
    DIRECTION INPUT ;
    USE SIGNAL ;
    PORT
      LAYER M5 ;
        RECT  23.664 -0.072 23.688 0.072 ;
    END
  END a[53]
  PIN a[54]
    DIRECTION INPUT ;
    USE SIGNAL ;
    PORT
      LAYER M5 ;
        RECT  23.856 -0.072 23.88 0.072 ;
    END
  END a[54]
  PIN a[55]
    DIRECTION INPUT ;
    USE SIGNAL ;
    PORT
      LAYER M5 ;
        RECT  24.048 -0.072 24.072 0.072 ;
    END
  END a[55]
  PIN a[56]
    DIRECTION INPUT ;
    USE SIGNAL ;
    PORT
      LAYER M5 ;
        RECT  24.24 -0.072 24.264 0.072 ;
    END
  END a[56]
  PIN a[57]
    DIRECTION INPUT ;
    USE SIGNAL ;
    PORT
      LAYER M5 ;
        RECT  24.432 -0.072 24.456 0.072 ;
    END
  END a[57]
  PIN a[58]
    DIRECTION INPUT ;
    USE SIGNAL ;
    PORT
      LAYER M5 ;
        RECT  24.624 -0.072 24.648 0.072 ;
    END
  END a[58]
  PIN a[59]
    DIRECTION INPUT ;
    USE SIGNAL ;
    PORT
      LAYER M5 ;
        RECT  24.816 -0.072 24.84 0.072 ;
    END
  END a[59]
  PIN a[5]
    DIRECTION INPUT ;
    USE SIGNAL ;
    PORT
      LAYER M5 ;
        RECT  14.448 -0.072 14.472 0.072 ;
    END
  END a[5]
  PIN a[60]
    DIRECTION INPUT ;
    USE SIGNAL ;
    PORT
      LAYER M5 ;
        RECT  25.008 -0.072 25.032 0.072 ;
    END
  END a[60]
  PIN a[61]
    DIRECTION INPUT ;
    USE SIGNAL ;
    PORT
      LAYER M5 ;
        RECT  25.2 -0.072 25.224 0.072 ;
    END
  END a[61]
  PIN a[62]
    DIRECTION INPUT ;
    USE SIGNAL ;
    PORT
      LAYER M5 ;
        RECT  25.392 -0.072 25.416 0.072 ;
    END
  END a[62]
  PIN a[63]
    DIRECTION INPUT ;
    USE SIGNAL ;
    PORT
      LAYER M5 ;
        RECT  25.584 -0.072 25.608 0.072 ;
    END
  END a[63]
  PIN a[64]
    DIRECTION INPUT ;
    USE SIGNAL ;
    PORT
      LAYER M5 ;
        RECT  25.776 -0.072 25.8 0.072 ;
    END
  END a[64]
  PIN a[65]
    DIRECTION INPUT ;
    USE SIGNAL ;
    PORT
      LAYER M5 ;
        RECT  25.968 -0.072 25.992 0.072 ;
    END
  END a[65]
  PIN a[66]
    DIRECTION INPUT ;
    USE SIGNAL ;
    PORT
      LAYER M5 ;
        RECT  26.16 -0.072 26.184 0.072 ;
    END
  END a[66]
  PIN a[67]
    DIRECTION INPUT ;
    USE SIGNAL ;
    PORT
      LAYER M5 ;
        RECT  26.352 -0.072 26.376 0.072 ;
    END
  END a[67]
  PIN a[68]
    DIRECTION INPUT ;
    USE SIGNAL ;
    PORT
      LAYER M5 ;
        RECT  26.544 -0.072 26.568 0.072 ;
    END
  END a[68]
  PIN a[69]
    DIRECTION INPUT ;
    USE SIGNAL ;
    PORT
      LAYER M5 ;
        RECT  26.736 -0.072 26.76 0.072 ;
    END
  END a[69]
  PIN a[6]
    DIRECTION INPUT ;
    USE SIGNAL ;
    PORT
      LAYER M5 ;
        RECT  14.64 -0.072 14.664 0.072 ;
    END
  END a[6]
  PIN a[70]
    DIRECTION INPUT ;
    USE SIGNAL ;
    PORT
      LAYER M5 ;
        RECT  26.928 -0.072 26.952 0.072 ;
    END
  END a[70]
  PIN a[71]
    DIRECTION INPUT ;
    USE SIGNAL ;
    PORT
      LAYER M5 ;
        RECT  27.12 -0.072 27.144 0.072 ;
    END
  END a[71]
  PIN a[72]
    DIRECTION INPUT ;
    USE SIGNAL ;
    PORT
      LAYER M5 ;
        RECT  27.312 -0.072 27.336 0.072 ;
    END
  END a[72]
  PIN a[73]
    DIRECTION INPUT ;
    USE SIGNAL ;
    PORT
      LAYER M5 ;
        RECT  27.504 -0.072 27.528 0.072 ;
    END
  END a[73]
  PIN a[74]
    DIRECTION INPUT ;
    USE SIGNAL ;
    PORT
      LAYER M5 ;
        RECT  27.696 -0.072 27.72 0.072 ;
    END
  END a[74]
  PIN a[75]
    DIRECTION INPUT ;
    USE SIGNAL ;
    PORT
      LAYER M5 ;
        RECT  27.888 -0.072 27.912 0.072 ;
    END
  END a[75]
  PIN a[76]
    DIRECTION INPUT ;
    USE SIGNAL ;
    PORT
      LAYER M5 ;
        RECT  28.08 -0.072 28.104 0.072 ;
    END
  END a[76]
  PIN a[77]
    DIRECTION INPUT ;
    USE SIGNAL ;
    PORT
      LAYER M5 ;
        RECT  28.272 -0.072 28.296 0.072 ;
    END
  END a[77]
  PIN a[78]
    DIRECTION INPUT ;
    USE SIGNAL ;
    PORT
      LAYER M5 ;
        RECT  28.464 -0.072 28.488 0.072 ;
    END
  END a[78]
  PIN a[79]
    DIRECTION INPUT ;
    USE SIGNAL ;
    PORT
      LAYER M5 ;
        RECT  28.656 -0.072 28.68 0.072 ;
    END
  END a[79]
  PIN a[7]
    DIRECTION INPUT ;
    USE SIGNAL ;
    PORT
      LAYER M5 ;
        RECT  14.832 -0.072 14.856 0.072 ;
    END
  END a[7]
  PIN a[80]
    DIRECTION INPUT ;
    USE SIGNAL ;
    PORT
      LAYER M5 ;
        RECT  28.848 -0.072 28.872 0.072 ;
    END
  END a[80]
  PIN a[81]
    DIRECTION INPUT ;
    USE SIGNAL ;
    PORT
      LAYER M5 ;
        RECT  29.04 -0.072 29.064 0.072 ;
    END
  END a[81]
  PIN a[82]
    DIRECTION INPUT ;
    USE SIGNAL ;
    PORT
      LAYER M5 ;
        RECT  29.232 -0.072 29.256 0.072 ;
    END
  END a[82]
  PIN a[83]
    DIRECTION INPUT ;
    USE SIGNAL ;
    PORT
      LAYER M5 ;
        RECT  29.424 -0.072 29.448 0.072 ;
    END
  END a[83]
  PIN a[84]
    DIRECTION INPUT ;
    USE SIGNAL ;
    PORT
      LAYER M5 ;
        RECT  29.616 -0.072 29.64 0.072 ;
    END
  END a[84]
  PIN a[85]
    DIRECTION INPUT ;
    USE SIGNAL ;
    PORT
      LAYER M5 ;
        RECT  29.808 -0.072 29.832 0.072 ;
    END
  END a[85]
  PIN a[86]
    DIRECTION INPUT ;
    USE SIGNAL ;
    PORT
      LAYER M5 ;
        RECT  30 -0.072 30.024 0.072 ;
    END
  END a[86]
  PIN a[87]
    DIRECTION INPUT ;
    USE SIGNAL ;
    PORT
      LAYER M5 ;
        RECT  30.192 -0.072 30.216 0.072 ;
    END
  END a[87]
  PIN a[88]
    DIRECTION INPUT ;
    USE SIGNAL ;
    PORT
      LAYER M5 ;
        RECT  30.384 -0.072 30.408 0.072 ;
    END
  END a[88]
  PIN a[89]
    DIRECTION INPUT ;
    USE SIGNAL ;
    PORT
      LAYER M5 ;
        RECT  30.576 -0.072 30.6 0.072 ;
    END
  END a[89]
  PIN a[8]
    DIRECTION INPUT ;
    USE SIGNAL ;
    PORT
      LAYER M5 ;
        RECT  15.024 -0.072 15.048 0.072 ;
    END
  END a[8]
  PIN a[90]
    DIRECTION INPUT ;
    USE SIGNAL ;
    PORT
      LAYER M5 ;
        RECT  30.768 -0.072 30.792 0.072 ;
    END
  END a[90]
  PIN a[91]
    DIRECTION INPUT ;
    USE SIGNAL ;
    PORT
      LAYER M5 ;
        RECT  30.96 -0.072 30.984 0.072 ;
    END
  END a[91]
  PIN a[92]
    DIRECTION INPUT ;
    USE SIGNAL ;
    PORT
      LAYER M5 ;
        RECT  31.152 -0.072 31.176 0.072 ;
    END
  END a[92]
  PIN a[93]
    DIRECTION INPUT ;
    USE SIGNAL ;
    PORT
      LAYER M5 ;
        RECT  31.344 -0.072 31.368 0.072 ;
    END
  END a[93]
  PIN a[94]
    DIRECTION INPUT ;
    USE SIGNAL ;
    PORT
      LAYER M5 ;
        RECT  31.536 -0.072 31.56 0.072 ;
    END
  END a[94]
  PIN a[95]
    DIRECTION INPUT ;
    USE SIGNAL ;
    PORT
      LAYER M5 ;
        RECT  31.728 -0.072 31.752 0.072 ;
    END
  END a[95]
  PIN a[96]
    DIRECTION INPUT ;
    USE SIGNAL ;
    PORT
      LAYER M5 ;
        RECT  31.92 -0.072 31.944 0.072 ;
    END
  END a[96]
  PIN a[97]
    DIRECTION INPUT ;
    USE SIGNAL ;
    PORT
      LAYER M5 ;
        RECT  32.112 -0.072 32.136 0.072 ;
    END
  END a[97]
  PIN a[98]
    DIRECTION INPUT ;
    USE SIGNAL ;
    PORT
      LAYER M5 ;
        RECT  32.304 -0.072 32.328 0.072 ;
    END
  END a[98]
  PIN a[99]
    DIRECTION INPUT ;
    USE SIGNAL ;
    PORT
      LAYER M5 ;
        RECT  32.496 -0.072 32.52 0.072 ;
    END
  END a[99]
  PIN a[9]
    DIRECTION INPUT ;
    USE SIGNAL ;
    PORT
      LAYER M5 ;
        RECT  15.216 -0.072 15.24 0.072 ;
    END
  END a[9]
  PIN b[0]
    DIRECTION OUTPUT ;
    USE SIGNAL ;
    PORT
      LAYER M5 ;
        RECT  13.488 21.528 13.512 21.672 ;
    END
  END b[0]
  PIN b[100]
    DIRECTION OUTPUT ;
    USE SIGNAL ;
    PORT
      LAYER M5 ;
        RECT  32.688 21.528 32.712 21.672 ;
    END
  END b[100]
  PIN b[101]
    DIRECTION OUTPUT ;
    USE SIGNAL ;
    PORT
      LAYER M5 ;
        RECT  32.88 21.528 32.904 21.672 ;
    END
  END b[101]
  PIN b[102]
    DIRECTION OUTPUT ;
    USE SIGNAL ;
    PORT
      LAYER M5 ;
        RECT  33.072 21.528 33.096 21.672 ;
    END
  END b[102]
  PIN b[103]
    DIRECTION OUTPUT ;
    USE SIGNAL ;
    PORT
      LAYER M5 ;
        RECT  33.264 21.528 33.288 21.672 ;
    END
  END b[103]
  PIN b[104]
    DIRECTION OUTPUT ;
    USE SIGNAL ;
    PORT
      LAYER M5 ;
        RECT  33.456 21.528 33.48 21.672 ;
    END
  END b[104]
  PIN b[105]
    DIRECTION OUTPUT ;
    USE SIGNAL ;
    PORT
      LAYER M5 ;
        RECT  33.648 21.528 33.672 21.672 ;
    END
  END b[105]
  PIN b[106]
    DIRECTION OUTPUT ;
    USE SIGNAL ;
    PORT
      LAYER M5 ;
        RECT  33.84 21.528 33.864 21.672 ;
    END
  END b[106]
  PIN b[107]
    DIRECTION OUTPUT ;
    USE SIGNAL ;
    PORT
      LAYER M5 ;
        RECT  34.032 21.528 34.056 21.672 ;
    END
  END b[107]
  PIN b[108]
    DIRECTION OUTPUT ;
    USE SIGNAL ;
    PORT
      LAYER M5 ;
        RECT  34.224 21.528 34.248 21.672 ;
    END
  END b[108]
  PIN b[109]
    DIRECTION OUTPUT ;
    USE SIGNAL ;
    PORT
      LAYER M5 ;
        RECT  34.416 21.528 34.44 21.672 ;
    END
  END b[109]
  PIN b[10]
    DIRECTION OUTPUT ;
    USE SIGNAL ;
    PORT
      LAYER M5 ;
        RECT  15.408 21.528 15.432 21.672 ;
    END
  END b[10]
  PIN b[110]
    DIRECTION OUTPUT ;
    USE SIGNAL ;
    PORT
      LAYER M5 ;
        RECT  34.608 21.528 34.632 21.672 ;
    END
  END b[110]
  PIN b[111]
    DIRECTION OUTPUT ;
    USE SIGNAL ;
    PORT
      LAYER M5 ;
        RECT  34.8 21.528 34.824 21.672 ;
    END
  END b[111]
  PIN b[112]
    DIRECTION OUTPUT ;
    USE SIGNAL ;
    PORT
      LAYER M5 ;
        RECT  34.992 21.528 35.016 21.672 ;
    END
  END b[112]
  PIN b[113]
    DIRECTION OUTPUT ;
    USE SIGNAL ;
    PORT
      LAYER M5 ;
        RECT  35.184 21.528 35.208 21.672 ;
    END
  END b[113]
  PIN b[114]
    DIRECTION OUTPUT ;
    USE SIGNAL ;
    PORT
      LAYER M5 ;
        RECT  35.376 21.528 35.4 21.672 ;
    END
  END b[114]
  PIN b[115]
    DIRECTION OUTPUT ;
    USE SIGNAL ;
    PORT
      LAYER M5 ;
        RECT  35.568 21.528 35.592 21.672 ;
    END
  END b[115]
  PIN b[116]
    DIRECTION OUTPUT ;
    USE SIGNAL ;
    PORT
      LAYER M5 ;
        RECT  35.76 21.528 35.784 21.672 ;
    END
  END b[116]
  PIN b[117]
    DIRECTION OUTPUT ;
    USE SIGNAL ;
    PORT
      LAYER M5 ;
        RECT  35.952 21.528 35.976 21.672 ;
    END
  END b[117]
  PIN b[118]
    DIRECTION OUTPUT ;
    USE SIGNAL ;
    PORT
      LAYER M5 ;
        RECT  36.144 21.528 36.168 21.672 ;
    END
  END b[118]
  PIN b[119]
    DIRECTION OUTPUT ;
    USE SIGNAL ;
    PORT
      LAYER M5 ;
        RECT  36.336 21.528 36.36 21.672 ;
    END
  END b[119]
  PIN b[11]
    DIRECTION OUTPUT ;
    USE SIGNAL ;
    PORT
      LAYER M5 ;
        RECT  15.6 21.528 15.624 21.672 ;
    END
  END b[11]
  PIN b[120]
    DIRECTION OUTPUT ;
    USE SIGNAL ;
    PORT
      LAYER M5 ;
        RECT  36.528 21.528 36.552 21.672 ;
    END
  END b[120]
  PIN b[121]
    DIRECTION OUTPUT ;
    USE SIGNAL ;
    PORT
      LAYER M5 ;
        RECT  36.72 21.528 36.744 21.672 ;
    END
  END b[121]
  PIN b[122]
    DIRECTION OUTPUT ;
    USE SIGNAL ;
    PORT
      LAYER M5 ;
        RECT  36.912 21.528 36.936 21.672 ;
    END
  END b[122]
  PIN b[123]
    DIRECTION OUTPUT ;
    USE SIGNAL ;
    PORT
      LAYER M5 ;
        RECT  37.104 21.528 37.128 21.672 ;
    END
  END b[123]
  PIN b[124]
    DIRECTION OUTPUT ;
    USE SIGNAL ;
    PORT
      LAYER M5 ;
        RECT  37.296 21.528 37.32 21.672 ;
    END
  END b[124]
  PIN b[125]
    DIRECTION OUTPUT ;
    USE SIGNAL ;
    PORT
      LAYER M5 ;
        RECT  37.488 21.528 37.512 21.672 ;
    END
  END b[125]
  PIN b[126]
    DIRECTION OUTPUT ;
    USE SIGNAL ;
    PORT
      LAYER M5 ;
        RECT  37.68 21.528 37.704 21.672 ;
    END
  END b[126]
  PIN b[127]
    DIRECTION OUTPUT ;
    USE SIGNAL ;
    PORT
      LAYER M5 ;
        RECT  37.872 21.528 37.896 21.672 ;
    END
  END b[127]
  PIN b[128]
    DIRECTION OUTPUT ;
    USE SIGNAL ;
    PORT
      LAYER M5 ;
        RECT  38.064 21.528 38.088 21.672 ;
    END
  END b[128]
  PIN b[129]
    DIRECTION OUTPUT ;
    USE SIGNAL ;
    PORT
      LAYER M5 ;
        RECT  38.256 21.528 38.28 21.672 ;
    END
  END b[129]
  PIN b[12]
    DIRECTION OUTPUT ;
    USE SIGNAL ;
    PORT
      LAYER M5 ;
        RECT  15.792 21.528 15.816 21.672 ;
    END
  END b[12]
  PIN b[130]
    DIRECTION OUTPUT ;
    USE SIGNAL ;
    PORT
      LAYER M5 ;
        RECT  38.448 21.528 38.472 21.672 ;
    END
  END b[130]
  PIN b[131]
    DIRECTION OUTPUT ;
    USE SIGNAL ;
    PORT
      LAYER M5 ;
        RECT  38.64 21.528 38.664 21.672 ;
    END
  END b[131]
  PIN b[132]
    DIRECTION OUTPUT ;
    USE SIGNAL ;
    PORT
      LAYER M5 ;
        RECT  38.832 21.528 38.856 21.672 ;
    END
  END b[132]
  PIN b[133]
    DIRECTION OUTPUT ;
    USE SIGNAL ;
    PORT
      LAYER M5 ;
        RECT  39.024 21.528 39.048 21.672 ;
    END
  END b[133]
  PIN b[134]
    DIRECTION OUTPUT ;
    USE SIGNAL ;
    PORT
      LAYER M5 ;
        RECT  39.216 21.528 39.24 21.672 ;
    END
  END b[134]
  PIN b[135]
    DIRECTION OUTPUT ;
    USE SIGNAL ;
    PORT
      LAYER M5 ;
        RECT  39.408 21.528 39.432 21.672 ;
    END
  END b[135]
  PIN b[136]
    DIRECTION OUTPUT ;
    USE SIGNAL ;
    PORT
      LAYER M5 ;
        RECT  39.6 21.528 39.624 21.672 ;
    END
  END b[136]
  PIN b[137]
    DIRECTION OUTPUT ;
    USE SIGNAL ;
    PORT
      LAYER M5 ;
        RECT  39.792 21.528 39.816 21.672 ;
    END
  END b[137]
  PIN b[138]
    DIRECTION OUTPUT ;
    USE SIGNAL ;
    PORT
      LAYER M5 ;
        RECT  39.984 21.528 40.008 21.672 ;
    END
  END b[138]
  PIN b[139]
    DIRECTION OUTPUT ;
    USE SIGNAL ;
    PORT
      LAYER M5 ;
        RECT  40.176 21.528 40.2 21.672 ;
    END
  END b[139]
  PIN b[13]
    DIRECTION OUTPUT ;
    USE SIGNAL ;
    PORT
      LAYER M5 ;
        RECT  15.984 21.528 16.008 21.672 ;
    END
  END b[13]
  PIN b[140]
    DIRECTION OUTPUT ;
    USE SIGNAL ;
    PORT
      LAYER M5 ;
        RECT  40.368 21.528 40.392 21.672 ;
    END
  END b[140]
  PIN b[141]
    DIRECTION OUTPUT ;
    USE SIGNAL ;
    PORT
      LAYER M5 ;
        RECT  40.56 21.528 40.584 21.672 ;
    END
  END b[141]
  PIN b[142]
    DIRECTION OUTPUT ;
    USE SIGNAL ;
    PORT
      LAYER M5 ;
        RECT  40.752 21.528 40.776 21.672 ;
    END
  END b[142]
  PIN b[143]
    DIRECTION OUTPUT ;
    USE SIGNAL ;
    PORT
      LAYER M5 ;
        RECT  40.944 21.528 40.968 21.672 ;
    END
  END b[143]
  PIN b[144]
    DIRECTION OUTPUT ;
    USE SIGNAL ;
    PORT
      LAYER M5 ;
        RECT  41.136 21.528 41.16 21.672 ;
    END
  END b[144]
  PIN b[145]
    DIRECTION OUTPUT ;
    USE SIGNAL ;
    PORT
      LAYER M5 ;
        RECT  41.328 21.528 41.352 21.672 ;
    END
  END b[145]
  PIN b[146]
    DIRECTION OUTPUT ;
    USE SIGNAL ;
    PORT
      LAYER M5 ;
        RECT  41.52 21.528 41.544 21.672 ;
    END
  END b[146]
  PIN b[147]
    DIRECTION OUTPUT ;
    USE SIGNAL ;
    PORT
      LAYER M5 ;
        RECT  41.712 21.528 41.736 21.672 ;
    END
  END b[147]
  PIN b[148]
    DIRECTION OUTPUT ;
    USE SIGNAL ;
    PORT
      LAYER M5 ;
        RECT  41.904 21.528 41.928 21.672 ;
    END
  END b[148]
  PIN b[149]
    DIRECTION OUTPUT ;
    USE SIGNAL ;
    PORT
      LAYER M5 ;
        RECT  42.096 21.528 42.12 21.672 ;
    END
  END b[149]
  PIN b[14]
    DIRECTION OUTPUT ;
    USE SIGNAL ;
    PORT
      LAYER M5 ;
        RECT  16.176 21.528 16.2 21.672 ;
    END
  END b[14]
  PIN b[150]
    DIRECTION OUTPUT ;
    USE SIGNAL ;
    PORT
      LAYER M5 ;
        RECT  42.288 21.528 42.312 21.672 ;
    END
  END b[150]
  PIN b[151]
    DIRECTION OUTPUT ;
    USE SIGNAL ;
    PORT
      LAYER M5 ;
        RECT  42.48 21.528 42.504 21.672 ;
    END
  END b[151]
  PIN b[152]
    DIRECTION OUTPUT ;
    USE SIGNAL ;
    PORT
      LAYER M5 ;
        RECT  42.672 21.528 42.696 21.672 ;
    END
  END b[152]
  PIN b[153]
    DIRECTION OUTPUT ;
    USE SIGNAL ;
    PORT
      LAYER M5 ;
        RECT  42.864 21.528 42.888 21.672 ;
    END
  END b[153]
  PIN b[154]
    DIRECTION OUTPUT ;
    USE SIGNAL ;
    PORT
      LAYER M5 ;
        RECT  43.056 21.528 43.08 21.672 ;
    END
  END b[154]
  PIN b[155]
    DIRECTION OUTPUT ;
    USE SIGNAL ;
    PORT
      LAYER M5 ;
        RECT  43.248 21.528 43.272 21.672 ;
    END
  END b[155]
  PIN b[156]
    DIRECTION OUTPUT ;
    USE SIGNAL ;
    PORT
      LAYER M5 ;
        RECT  43.44 21.528 43.464 21.672 ;
    END
  END b[156]
  PIN b[157]
    DIRECTION OUTPUT ;
    USE SIGNAL ;
    PORT
      LAYER M5 ;
        RECT  43.632 21.528 43.656 21.672 ;
    END
  END b[157]
  PIN b[158]
    DIRECTION OUTPUT ;
    USE SIGNAL ;
    PORT
      LAYER M5 ;
        RECT  43.824 21.528 43.848 21.672 ;
    END
  END b[158]
  PIN b[159]
    DIRECTION OUTPUT ;
    USE SIGNAL ;
    PORT
      LAYER M5 ;
        RECT  44.016 21.528 44.04 21.672 ;
    END
  END b[159]
  PIN b[15]
    DIRECTION OUTPUT ;
    USE SIGNAL ;
    PORT
      LAYER M5 ;
        RECT  16.368 21.528 16.392 21.672 ;
    END
  END b[15]
  PIN b[160]
    DIRECTION OUTPUT ;
    USE SIGNAL ;
    PORT
      LAYER M5 ;
        RECT  44.208 21.528 44.232 21.672 ;
    END
  END b[160]
  PIN b[161]
    DIRECTION OUTPUT ;
    USE SIGNAL ;
    PORT
      LAYER M5 ;
        RECT  44.4 21.528 44.424 21.672 ;
    END
  END b[161]
  PIN b[162]
    DIRECTION OUTPUT ;
    USE SIGNAL ;
    PORT
      LAYER M5 ;
        RECT  44.592 21.528 44.616 21.672 ;
    END
  END b[162]
  PIN b[163]
    DIRECTION OUTPUT ;
    USE SIGNAL ;
    PORT
      LAYER M5 ;
        RECT  44.784 21.528 44.808 21.672 ;
    END
  END b[163]
  PIN b[164]
    DIRECTION OUTPUT ;
    USE SIGNAL ;
    PORT
      LAYER M5 ;
        RECT  44.976 21.528 45 21.672 ;
    END
  END b[164]
  PIN b[165]
    DIRECTION OUTPUT ;
    USE SIGNAL ;
    PORT
      LAYER M5 ;
        RECT  45.168 21.528 45.192 21.672 ;
    END
  END b[165]
  PIN b[166]
    DIRECTION OUTPUT ;
    USE SIGNAL ;
    PORT
      LAYER M5 ;
        RECT  45.36 21.528 45.384 21.672 ;
    END
  END b[166]
  PIN b[167]
    DIRECTION OUTPUT ;
    USE SIGNAL ;
    PORT
      LAYER M5 ;
        RECT  45.552 21.528 45.576 21.672 ;
    END
  END b[167]
  PIN b[168]
    DIRECTION OUTPUT ;
    USE SIGNAL ;
    PORT
      LAYER M5 ;
        RECT  45.744 21.528 45.768 21.672 ;
    END
  END b[168]
  PIN b[169]
    DIRECTION OUTPUT ;
    USE SIGNAL ;
    PORT
      LAYER M5 ;
        RECT  45.936 21.528 45.96 21.672 ;
    END
  END b[169]
  PIN b[16]
    DIRECTION OUTPUT ;
    USE SIGNAL ;
    PORT
      LAYER M5 ;
        RECT  16.56 21.528 16.584 21.672 ;
    END
  END b[16]
  PIN b[170]
    DIRECTION OUTPUT ;
    USE SIGNAL ;
    PORT
      LAYER M5 ;
        RECT  46.128 21.528 46.152 21.672 ;
    END
  END b[170]
  PIN b[171]
    DIRECTION OUTPUT ;
    USE SIGNAL ;
    PORT
      LAYER M5 ;
        RECT  46.32 21.528 46.344 21.672 ;
    END
  END b[171]
  PIN b[172]
    DIRECTION OUTPUT ;
    USE SIGNAL ;
    PORT
      LAYER M5 ;
        RECT  46.512 21.528 46.536 21.672 ;
    END
  END b[172]
  PIN b[173]
    DIRECTION OUTPUT ;
    USE SIGNAL ;
    PORT
      LAYER M5 ;
        RECT  46.704 21.528 46.728 21.672 ;
    END
  END b[173]
  PIN b[174]
    DIRECTION OUTPUT ;
    USE SIGNAL ;
    PORT
      LAYER M5 ;
        RECT  46.896 21.528 46.92 21.672 ;
    END
  END b[174]
  PIN b[175]
    DIRECTION OUTPUT ;
    USE SIGNAL ;
    PORT
      LAYER M5 ;
        RECT  47.088 21.528 47.112 21.672 ;
    END
  END b[175]
  PIN b[176]
    DIRECTION OUTPUT ;
    USE SIGNAL ;
    PORT
      LAYER M5 ;
        RECT  47.28 21.528 47.304 21.672 ;
    END
  END b[176]
  PIN b[177]
    DIRECTION OUTPUT ;
    USE SIGNAL ;
    PORT
      LAYER M5 ;
        RECT  47.472 21.528 47.496 21.672 ;
    END
  END b[177]
  PIN b[178]
    DIRECTION OUTPUT ;
    USE SIGNAL ;
    PORT
      LAYER M5 ;
        RECT  47.664 21.528 47.688 21.672 ;
    END
  END b[178]
  PIN b[179]
    DIRECTION OUTPUT ;
    USE SIGNAL ;
    PORT
      LAYER M5 ;
        RECT  47.856 21.528 47.88 21.672 ;
    END
  END b[179]
  PIN b[17]
    DIRECTION OUTPUT ;
    USE SIGNAL ;
    PORT
      LAYER M5 ;
        RECT  16.752 21.528 16.776 21.672 ;
    END
  END b[17]
  PIN b[180]
    DIRECTION OUTPUT ;
    USE SIGNAL ;
    PORT
      LAYER M5 ;
        RECT  48.048 21.528 48.072 21.672 ;
    END
  END b[180]
  PIN b[181]
    DIRECTION OUTPUT ;
    USE SIGNAL ;
    PORT
      LAYER M5 ;
        RECT  48.24 21.528 48.264 21.672 ;
    END
  END b[181]
  PIN b[182]
    DIRECTION OUTPUT ;
    USE SIGNAL ;
    PORT
      LAYER M5 ;
        RECT  48.432 21.528 48.456 21.672 ;
    END
  END b[182]
  PIN b[183]
    DIRECTION OUTPUT ;
    USE SIGNAL ;
    PORT
      LAYER M5 ;
        RECT  48.624 21.528 48.648 21.672 ;
    END
  END b[183]
  PIN b[184]
    DIRECTION OUTPUT ;
    USE SIGNAL ;
    PORT
      LAYER M5 ;
        RECT  48.816 21.528 48.84 21.672 ;
    END
  END b[184]
  PIN b[185]
    DIRECTION OUTPUT ;
    USE SIGNAL ;
    PORT
      LAYER M5 ;
        RECT  49.008 21.528 49.032 21.672 ;
    END
  END b[185]
  PIN b[186]
    DIRECTION OUTPUT ;
    USE SIGNAL ;
    PORT
      LAYER M5 ;
        RECT  49.2 21.528 49.224 21.672 ;
    END
  END b[186]
  PIN b[187]
    DIRECTION OUTPUT ;
    USE SIGNAL ;
    PORT
      LAYER M5 ;
        RECT  49.392 21.528 49.416 21.672 ;
    END
  END b[187]
  PIN b[188]
    DIRECTION OUTPUT ;
    USE SIGNAL ;
    PORT
      LAYER M5 ;
        RECT  49.584 21.528 49.608 21.672 ;
    END
  END b[188]
  PIN b[189]
    DIRECTION OUTPUT ;
    USE SIGNAL ;
    PORT
      LAYER M5 ;
        RECT  49.776 21.528 49.8 21.672 ;
    END
  END b[189]
  PIN b[18]
    DIRECTION OUTPUT ;
    USE SIGNAL ;
    PORT
      LAYER M5 ;
        RECT  16.944 21.528 16.968 21.672 ;
    END
  END b[18]
  PIN b[190]
    DIRECTION OUTPUT ;
    USE SIGNAL ;
    PORT
      LAYER M5 ;
        RECT  49.968 21.528 49.992 21.672 ;
    END
  END b[190]
  PIN b[191]
    DIRECTION OUTPUT ;
    USE SIGNAL ;
    PORT
      LAYER M5 ;
        RECT  50.16 21.528 50.184 21.672 ;
    END
  END b[191]
  PIN b[192]
    DIRECTION OUTPUT ;
    USE SIGNAL ;
    PORT
      LAYER M5 ;
        RECT  50.352 21.528 50.376 21.672 ;
    END
  END b[192]
  PIN b[193]
    DIRECTION OUTPUT ;
    USE SIGNAL ;
    PORT
      LAYER M5 ;
        RECT  50.544 21.528 50.568 21.672 ;
    END
  END b[193]
  PIN b[194]
    DIRECTION OUTPUT ;
    USE SIGNAL ;
    PORT
      LAYER M5 ;
        RECT  50.736 21.528 50.76 21.672 ;
    END
  END b[194]
  PIN b[195]
    DIRECTION OUTPUT ;
    USE SIGNAL ;
    PORT
      LAYER M5 ;
        RECT  50.928 21.528 50.952 21.672 ;
    END
  END b[195]
  PIN b[196]
    DIRECTION OUTPUT ;
    USE SIGNAL ;
    PORT
      LAYER M5 ;
        RECT  51.12 21.528 51.144 21.672 ;
    END
  END b[196]
  PIN b[197]
    DIRECTION OUTPUT ;
    USE SIGNAL ;
    PORT
      LAYER M5 ;
        RECT  51.312 21.528 51.336 21.672 ;
    END
  END b[197]
  PIN b[198]
    DIRECTION OUTPUT ;
    USE SIGNAL ;
    PORT
      LAYER M5 ;
        RECT  51.504 21.528 51.528 21.672 ;
    END
  END b[198]
  PIN b[199]
    DIRECTION OUTPUT ;
    USE SIGNAL ;
    PORT
      LAYER M5 ;
        RECT  51.696 21.528 51.72 21.672 ;
    END
  END b[199]
  PIN b[19]
    DIRECTION OUTPUT ;
    USE SIGNAL ;
    PORT
      LAYER M5 ;
        RECT  17.136 21.528 17.16 21.672 ;
    END
  END b[19]
  PIN b[1]
    DIRECTION OUTPUT ;
    USE SIGNAL ;
    PORT
      LAYER M5 ;
        RECT  13.68 21.528 13.704 21.672 ;
    END
  END b[1]
  PIN b[200]
    DIRECTION OUTPUT ;
    USE SIGNAL ;
    PORT
      LAYER M5 ;
        RECT  51.888 21.528 51.912 21.672 ;
    END
  END b[200]
  PIN b[201]
    DIRECTION OUTPUT ;
    USE SIGNAL ;
    PORT
      LAYER M5 ;
        RECT  52.08 21.528 52.104 21.672 ;
    END
  END b[201]
  PIN b[202]
    DIRECTION OUTPUT ;
    USE SIGNAL ;
    PORT
      LAYER M5 ;
        RECT  52.272 21.528 52.296 21.672 ;
    END
  END b[202]
  PIN b[203]
    DIRECTION OUTPUT ;
    USE SIGNAL ;
    PORT
      LAYER M5 ;
        RECT  52.464 21.528 52.488 21.672 ;
    END
  END b[203]
  PIN b[204]
    DIRECTION OUTPUT ;
    USE SIGNAL ;
    PORT
      LAYER M5 ;
        RECT  52.656 21.528 52.68 21.672 ;
    END
  END b[204]
  PIN b[205]
    DIRECTION OUTPUT ;
    USE SIGNAL ;
    PORT
      LAYER M5 ;
        RECT  52.848 21.528 52.872 21.672 ;
    END
  END b[205]
  PIN b[206]
    DIRECTION OUTPUT ;
    USE SIGNAL ;
    PORT
      LAYER M5 ;
        RECT  53.04 21.528 53.064 21.672 ;
    END
  END b[206]
  PIN b[207]
    DIRECTION OUTPUT ;
    USE SIGNAL ;
    PORT
      LAYER M5 ;
        RECT  53.232 21.528 53.256 21.672 ;
    END
  END b[207]
  PIN b[208]
    DIRECTION OUTPUT ;
    USE SIGNAL ;
    PORT
      LAYER M5 ;
        RECT  53.424 21.528 53.448 21.672 ;
    END
  END b[208]
  PIN b[209]
    DIRECTION OUTPUT ;
    USE SIGNAL ;
    PORT
      LAYER M5 ;
        RECT  53.616 21.528 53.64 21.672 ;
    END
  END b[209]
  PIN b[20]
    DIRECTION OUTPUT ;
    USE SIGNAL ;
    PORT
      LAYER M5 ;
        RECT  17.328 21.528 17.352 21.672 ;
    END
  END b[20]
  PIN b[210]
    DIRECTION OUTPUT ;
    USE SIGNAL ;
    PORT
      LAYER M5 ;
        RECT  53.808 21.528 53.832 21.672 ;
    END
  END b[210]
  PIN b[211]
    DIRECTION OUTPUT ;
    USE SIGNAL ;
    PORT
      LAYER M5 ;
        RECT  54 21.528 54.024 21.672 ;
    END
  END b[211]
  PIN b[212]
    DIRECTION OUTPUT ;
    USE SIGNAL ;
    PORT
      LAYER M5 ;
        RECT  54.192 21.528 54.216 21.672 ;
    END
  END b[212]
  PIN b[213]
    DIRECTION OUTPUT ;
    USE SIGNAL ;
    PORT
      LAYER M5 ;
        RECT  54.384 21.528 54.408 21.672 ;
    END
  END b[213]
  PIN b[214]
    DIRECTION OUTPUT ;
    USE SIGNAL ;
    PORT
      LAYER M5 ;
        RECT  54.576 21.528 54.6 21.672 ;
    END
  END b[214]
  PIN b[215]
    DIRECTION OUTPUT ;
    USE SIGNAL ;
    PORT
      LAYER M5 ;
        RECT  54.768 21.528 54.792 21.672 ;
    END
  END b[215]
  PIN b[216]
    DIRECTION OUTPUT ;
    USE SIGNAL ;
    PORT
      LAYER M5 ;
        RECT  54.96 21.528 54.984 21.672 ;
    END
  END b[216]
  PIN b[217]
    DIRECTION OUTPUT ;
    USE SIGNAL ;
    PORT
      LAYER M5 ;
        RECT  55.152 21.528 55.176 21.672 ;
    END
  END b[217]
  PIN b[218]
    DIRECTION OUTPUT ;
    USE SIGNAL ;
    PORT
      LAYER M5 ;
        RECT  55.344 21.528 55.368 21.672 ;
    END
  END b[218]
  PIN b[219]
    DIRECTION OUTPUT ;
    USE SIGNAL ;
    PORT
      LAYER M5 ;
        RECT  55.536 21.528 55.56 21.672 ;
    END
  END b[219]
  PIN b[21]
    DIRECTION OUTPUT ;
    USE SIGNAL ;
    PORT
      LAYER M5 ;
        RECT  17.52 21.528 17.544 21.672 ;
    END
  END b[21]
  PIN b[220]
    DIRECTION OUTPUT ;
    USE SIGNAL ;
    PORT
      LAYER M5 ;
        RECT  55.728 21.528 55.752 21.672 ;
    END
  END b[220]
  PIN b[221]
    DIRECTION OUTPUT ;
    USE SIGNAL ;
    PORT
      LAYER M5 ;
        RECT  55.92 21.528 55.944 21.672 ;
    END
  END b[221]
  PIN b[222]
    DIRECTION OUTPUT ;
    USE SIGNAL ;
    PORT
      LAYER M5 ;
        RECT  56.112 21.528 56.136 21.672 ;
    END
  END b[222]
  PIN b[223]
    DIRECTION OUTPUT ;
    USE SIGNAL ;
    PORT
      LAYER M5 ;
        RECT  56.304 21.528 56.328 21.672 ;
    END
  END b[223]
  PIN b[224]
    DIRECTION OUTPUT ;
    USE SIGNAL ;
    PORT
      LAYER M5 ;
        RECT  56.496 21.528 56.52 21.672 ;
    END
  END b[224]
  PIN b[225]
    DIRECTION OUTPUT ;
    USE SIGNAL ;
    PORT
      LAYER M5 ;
        RECT  56.688 21.528 56.712 21.672 ;
    END
  END b[225]
  PIN b[226]
    DIRECTION OUTPUT ;
    USE SIGNAL ;
    PORT
      LAYER M5 ;
        RECT  56.88 21.528 56.904 21.672 ;
    END
  END b[226]
  PIN b[227]
    DIRECTION OUTPUT ;
    USE SIGNAL ;
    PORT
      LAYER M5 ;
        RECT  57.072 21.528 57.096 21.672 ;
    END
  END b[227]
  PIN b[228]
    DIRECTION OUTPUT ;
    USE SIGNAL ;
    PORT
      LAYER M5 ;
        RECT  57.264 21.528 57.288 21.672 ;
    END
  END b[228]
  PIN b[229]
    DIRECTION OUTPUT ;
    USE SIGNAL ;
    PORT
      LAYER M5 ;
        RECT  57.456 21.528 57.48 21.672 ;
    END
  END b[229]
  PIN b[22]
    DIRECTION OUTPUT ;
    USE SIGNAL ;
    PORT
      LAYER M5 ;
        RECT  17.712 21.528 17.736 21.672 ;
    END
  END b[22]
  PIN b[230]
    DIRECTION OUTPUT ;
    USE SIGNAL ;
    PORT
      LAYER M5 ;
        RECT  57.648 21.528 57.672 21.672 ;
    END
  END b[230]
  PIN b[231]
    DIRECTION OUTPUT ;
    USE SIGNAL ;
    PORT
      LAYER M5 ;
        RECT  57.84 21.528 57.864 21.672 ;
    END
  END b[231]
  PIN b[232]
    DIRECTION OUTPUT ;
    USE SIGNAL ;
    PORT
      LAYER M5 ;
        RECT  58.032 21.528 58.056 21.672 ;
    END
  END b[232]
  PIN b[233]
    DIRECTION OUTPUT ;
    USE SIGNAL ;
    PORT
      LAYER M5 ;
        RECT  58.224 21.528 58.248 21.672 ;
    END
  END b[233]
  PIN b[234]
    DIRECTION OUTPUT ;
    USE SIGNAL ;
    PORT
      LAYER M5 ;
        RECT  58.416 21.528 58.44 21.672 ;
    END
  END b[234]
  PIN b[235]
    DIRECTION OUTPUT ;
    USE SIGNAL ;
    PORT
      LAYER M5 ;
        RECT  58.608 21.528 58.632 21.672 ;
    END
  END b[235]
  PIN b[236]
    DIRECTION OUTPUT ;
    USE SIGNAL ;
    PORT
      LAYER M5 ;
        RECT  58.8 21.528 58.824 21.672 ;
    END
  END b[236]
  PIN b[237]
    DIRECTION OUTPUT ;
    USE SIGNAL ;
    PORT
      LAYER M5 ;
        RECT  58.992 21.528 59.016 21.672 ;
    END
  END b[237]
  PIN b[238]
    DIRECTION OUTPUT ;
    USE SIGNAL ;
    PORT
      LAYER M5 ;
        RECT  59.184 21.528 59.208 21.672 ;
    END
  END b[238]
  PIN b[239]
    DIRECTION OUTPUT ;
    USE SIGNAL ;
    PORT
      LAYER M5 ;
        RECT  59.376 21.528 59.4 21.672 ;
    END
  END b[239]
  PIN b[23]
    DIRECTION OUTPUT ;
    USE SIGNAL ;
    PORT
      LAYER M5 ;
        RECT  17.904 21.528 17.928 21.672 ;
    END
  END b[23]
  PIN b[240]
    DIRECTION OUTPUT ;
    USE SIGNAL ;
    PORT
      LAYER M5 ;
        RECT  59.568 21.528 59.592 21.672 ;
    END
  END b[240]
  PIN b[241]
    DIRECTION OUTPUT ;
    USE SIGNAL ;
    PORT
      LAYER M5 ;
        RECT  59.76 21.528 59.784 21.672 ;
    END
  END b[241]
  PIN b[242]
    DIRECTION OUTPUT ;
    USE SIGNAL ;
    PORT
      LAYER M5 ;
        RECT  59.952 21.528 59.976 21.672 ;
    END
  END b[242]
  PIN b[243]
    DIRECTION OUTPUT ;
    USE SIGNAL ;
    PORT
      LAYER M5 ;
        RECT  60.144 21.528 60.168 21.672 ;
    END
  END b[243]
  PIN b[244]
    DIRECTION OUTPUT ;
    USE SIGNAL ;
    PORT
      LAYER M5 ;
        RECT  60.336 21.528 60.36 21.672 ;
    END
  END b[244]
  PIN b[245]
    DIRECTION OUTPUT ;
    USE SIGNAL ;
    PORT
      LAYER M5 ;
        RECT  60.528 21.528 60.552 21.672 ;
    END
  END b[245]
  PIN b[246]
    DIRECTION OUTPUT ;
    USE SIGNAL ;
    PORT
      LAYER M5 ;
        RECT  60.72 21.528 60.744 21.672 ;
    END
  END b[246]
  PIN b[247]
    DIRECTION OUTPUT ;
    USE SIGNAL ;
    PORT
      LAYER M5 ;
        RECT  60.912 21.528 60.936 21.672 ;
    END
  END b[247]
  PIN b[248]
    DIRECTION OUTPUT ;
    USE SIGNAL ;
    PORT
      LAYER M5 ;
        RECT  61.104 21.528 61.128 21.672 ;
    END
  END b[248]
  PIN b[249]
    DIRECTION OUTPUT ;
    USE SIGNAL ;
    PORT
      LAYER M5 ;
        RECT  61.296 21.528 61.32 21.672 ;
    END
  END b[249]
  PIN b[24]
    DIRECTION OUTPUT ;
    USE SIGNAL ;
    PORT
      LAYER M5 ;
        RECT  18.096 21.528 18.12 21.672 ;
    END
  END b[24]
  PIN b[250]
    DIRECTION OUTPUT ;
    USE SIGNAL ;
    PORT
      LAYER M5 ;
        RECT  61.488 21.528 61.512 21.672 ;
    END
  END b[250]
  PIN b[251]
    DIRECTION OUTPUT ;
    USE SIGNAL ;
    PORT
      LAYER M5 ;
        RECT  61.68 21.528 61.704 21.672 ;
    END
  END b[251]
  PIN b[252]
    DIRECTION OUTPUT ;
    USE SIGNAL ;
    PORT
      LAYER M5 ;
        RECT  61.872 21.528 61.896 21.672 ;
    END
  END b[252]
  PIN b[253]
    DIRECTION OUTPUT ;
    USE SIGNAL ;
    PORT
      LAYER M5 ;
        RECT  62.064 21.528 62.088 21.672 ;
    END
  END b[253]
  PIN b[254]
    DIRECTION OUTPUT ;
    USE SIGNAL ;
    PORT
      LAYER M5 ;
        RECT  62.256 21.528 62.28 21.672 ;
    END
  END b[254]
  PIN b[255]
    DIRECTION OUTPUT ;
    USE SIGNAL ;
    PORT
      LAYER M5 ;
        RECT  62.448 21.528 62.472 21.672 ;
    END
  END b[255]
  PIN b[256]
    DIRECTION OUTPUT ;
    USE SIGNAL ;
    PORT
      LAYER M5 ;
        RECT  62.64 21.528 62.664 21.672 ;
    END
  END b[256]
  PIN b[257]
    DIRECTION OUTPUT ;
    USE SIGNAL ;
    PORT
      LAYER M5 ;
        RECT  62.832 21.528 62.856 21.672 ;
    END
  END b[257]
  PIN b[258]
    DIRECTION OUTPUT ;
    USE SIGNAL ;
    PORT
      LAYER M5 ;
        RECT  63.024 21.528 63.048 21.672 ;
    END
  END b[258]
  PIN b[259]
    DIRECTION OUTPUT ;
    USE SIGNAL ;
    PORT
      LAYER M5 ;
        RECT  63.216 21.528 63.24 21.672 ;
    END
  END b[259]
  PIN b[25]
    DIRECTION OUTPUT ;
    USE SIGNAL ;
    PORT
      LAYER M5 ;
        RECT  18.288 21.528 18.312 21.672 ;
    END
  END b[25]
  PIN b[260]
    DIRECTION OUTPUT ;
    USE SIGNAL ;
    PORT
      LAYER M5 ;
        RECT  63.408 21.528 63.432 21.672 ;
    END
  END b[260]
  PIN b[261]
    DIRECTION OUTPUT ;
    USE SIGNAL ;
    PORT
      LAYER M5 ;
        RECT  63.6 21.528 63.624 21.672 ;
    END
  END b[261]
  PIN b[262]
    DIRECTION OUTPUT ;
    USE SIGNAL ;
    PORT
      LAYER M5 ;
        RECT  63.792 21.528 63.816 21.672 ;
    END
  END b[262]
  PIN b[263]
    DIRECTION OUTPUT ;
    USE SIGNAL ;
    PORT
      LAYER M5 ;
        RECT  63.984 21.528 64.008 21.672 ;
    END
  END b[263]
  PIN b[264]
    DIRECTION OUTPUT ;
    USE SIGNAL ;
    PORT
      LAYER M5 ;
        RECT  64.176 21.528 64.2 21.672 ;
    END
  END b[264]
  PIN b[265]
    DIRECTION OUTPUT ;
    USE SIGNAL ;
    PORT
      LAYER M5 ;
        RECT  64.368 21.528 64.392 21.672 ;
    END
  END b[265]
  PIN b[266]
    DIRECTION OUTPUT ;
    USE SIGNAL ;
    PORT
      LAYER M5 ;
        RECT  64.56 21.528 64.584 21.672 ;
    END
  END b[266]
  PIN b[267]
    DIRECTION OUTPUT ;
    USE SIGNAL ;
    PORT
      LAYER M5 ;
        RECT  64.752 21.528 64.776 21.672 ;
    END
  END b[267]
  PIN b[268]
    DIRECTION OUTPUT ;
    USE SIGNAL ;
    PORT
      LAYER M5 ;
        RECT  64.944 21.528 64.968 21.672 ;
    END
  END b[268]
  PIN b[269]
    DIRECTION OUTPUT ;
    USE SIGNAL ;
    PORT
      LAYER M5 ;
        RECT  65.136 21.528 65.16 21.672 ;
    END
  END b[269]
  PIN b[26]
    DIRECTION OUTPUT ;
    USE SIGNAL ;
    PORT
      LAYER M5 ;
        RECT  18.48 21.528 18.504 21.672 ;
    END
  END b[26]
  PIN b[270]
    DIRECTION OUTPUT ;
    USE SIGNAL ;
    PORT
      LAYER M5 ;
        RECT  65.328 21.528 65.352 21.672 ;
    END
  END b[270]
  PIN b[271]
    DIRECTION OUTPUT ;
    USE SIGNAL ;
    PORT
      LAYER M5 ;
        RECT  65.52 21.528 65.544 21.672 ;
    END
  END b[271]
  PIN b[272]
    DIRECTION OUTPUT ;
    USE SIGNAL ;
    PORT
      LAYER M5 ;
        RECT  65.712 21.528 65.736 21.672 ;
    END
  END b[272]
  PIN b[273]
    DIRECTION OUTPUT ;
    USE SIGNAL ;
    PORT
      LAYER M5 ;
        RECT  65.904 21.528 65.928 21.672 ;
    END
  END b[273]
  PIN b[274]
    DIRECTION OUTPUT ;
    USE SIGNAL ;
    PORT
      LAYER M5 ;
        RECT  66.096 21.528 66.12 21.672 ;
    END
  END b[274]
  PIN b[275]
    DIRECTION OUTPUT ;
    USE SIGNAL ;
    PORT
      LAYER M5 ;
        RECT  66.288 21.528 66.312 21.672 ;
    END
  END b[275]
  PIN b[276]
    DIRECTION OUTPUT ;
    USE SIGNAL ;
    PORT
      LAYER M5 ;
        RECT  66.48 21.528 66.504 21.672 ;
    END
  END b[276]
  PIN b[277]
    DIRECTION OUTPUT ;
    USE SIGNAL ;
    PORT
      LAYER M5 ;
        RECT  66.672 21.528 66.696 21.672 ;
    END
  END b[277]
  PIN b[278]
    DIRECTION OUTPUT ;
    USE SIGNAL ;
    PORT
      LAYER M5 ;
        RECT  66.864 21.528 66.888 21.672 ;
    END
  END b[278]
  PIN b[279]
    DIRECTION OUTPUT ;
    USE SIGNAL ;
    PORT
      LAYER M5 ;
        RECT  67.056 21.528 67.08 21.672 ;
    END
  END b[279]
  PIN b[27]
    DIRECTION OUTPUT ;
    USE SIGNAL ;
    PORT
      LAYER M5 ;
        RECT  18.672 21.528 18.696 21.672 ;
    END
  END b[27]
  PIN b[280]
    DIRECTION OUTPUT ;
    USE SIGNAL ;
    PORT
      LAYER M5 ;
        RECT  67.248 21.528 67.272 21.672 ;
    END
  END b[280]
  PIN b[281]
    DIRECTION OUTPUT ;
    USE SIGNAL ;
    PORT
      LAYER M5 ;
        RECT  67.44 21.528 67.464 21.672 ;
    END
  END b[281]
  PIN b[282]
    DIRECTION OUTPUT ;
    USE SIGNAL ;
    PORT
      LAYER M5 ;
        RECT  67.632 21.528 67.656 21.672 ;
    END
  END b[282]
  PIN b[283]
    DIRECTION OUTPUT ;
    USE SIGNAL ;
    PORT
      LAYER M5 ;
        RECT  67.824 21.528 67.848 21.672 ;
    END
  END b[283]
  PIN b[284]
    DIRECTION OUTPUT ;
    USE SIGNAL ;
    PORT
      LAYER M5 ;
        RECT  68.016 21.528 68.04 21.672 ;
    END
  END b[284]
  PIN b[285]
    DIRECTION OUTPUT ;
    USE SIGNAL ;
    PORT
      LAYER M5 ;
        RECT  68.208 21.528 68.232 21.672 ;
    END
  END b[285]
  PIN b[286]
    DIRECTION OUTPUT ;
    USE SIGNAL ;
    PORT
      LAYER M5 ;
        RECT  68.4 21.528 68.424 21.672 ;
    END
  END b[286]
  PIN b[287]
    DIRECTION OUTPUT ;
    USE SIGNAL ;
    PORT
      LAYER M5 ;
        RECT  68.592 21.528 68.616 21.672 ;
    END
  END b[287]
  PIN b[288]
    DIRECTION OUTPUT ;
    USE SIGNAL ;
    PORT
      LAYER M5 ;
        RECT  68.784 21.528 68.808 21.672 ;
    END
  END b[288]
  PIN b[289]
    DIRECTION OUTPUT ;
    USE SIGNAL ;
    PORT
      LAYER M5 ;
        RECT  68.976 21.528 69 21.672 ;
    END
  END b[289]
  PIN b[28]
    DIRECTION OUTPUT ;
    USE SIGNAL ;
    PORT
      LAYER M5 ;
        RECT  18.864 21.528 18.888 21.672 ;
    END
  END b[28]
  PIN b[290]
    DIRECTION OUTPUT ;
    USE SIGNAL ;
    PORT
      LAYER M5 ;
        RECT  69.168 21.528 69.192 21.672 ;
    END
  END b[290]
  PIN b[291]
    DIRECTION OUTPUT ;
    USE SIGNAL ;
    PORT
      LAYER M5 ;
        RECT  69.36 21.528 69.384 21.672 ;
    END
  END b[291]
  PIN b[292]
    DIRECTION OUTPUT ;
    USE SIGNAL ;
    PORT
      LAYER M5 ;
        RECT  69.552 21.528 69.576 21.672 ;
    END
  END b[292]
  PIN b[293]
    DIRECTION OUTPUT ;
    USE SIGNAL ;
    PORT
      LAYER M5 ;
        RECT  69.744 21.528 69.768 21.672 ;
    END
  END b[293]
  PIN b[294]
    DIRECTION OUTPUT ;
    USE SIGNAL ;
    PORT
      LAYER M5 ;
        RECT  69.936 21.528 69.96 21.672 ;
    END
  END b[294]
  PIN b[295]
    DIRECTION OUTPUT ;
    USE SIGNAL ;
    PORT
      LAYER M5 ;
        RECT  70.128 21.528 70.152 21.672 ;
    END
  END b[295]
  PIN b[296]
    DIRECTION OUTPUT ;
    USE SIGNAL ;
    PORT
      LAYER M5 ;
        RECT  70.32 21.528 70.344 21.672 ;
    END
  END b[296]
  PIN b[297]
    DIRECTION OUTPUT ;
    USE SIGNAL ;
    PORT
      LAYER M5 ;
        RECT  70.512 21.528 70.536 21.672 ;
    END
  END b[297]
  PIN b[298]
    DIRECTION OUTPUT ;
    USE SIGNAL ;
    PORT
      LAYER M5 ;
        RECT  70.704 21.528 70.728 21.672 ;
    END
  END b[298]
  PIN b[299]
    DIRECTION OUTPUT ;
    USE SIGNAL ;
    PORT
      LAYER M5 ;
        RECT  70.896 21.528 70.92 21.672 ;
    END
  END b[299]
  PIN b[29]
    DIRECTION OUTPUT ;
    USE SIGNAL ;
    PORT
      LAYER M5 ;
        RECT  19.056 21.528 19.08 21.672 ;
    END
  END b[29]
  PIN b[2]
    DIRECTION OUTPUT ;
    USE SIGNAL ;
    PORT
      LAYER M5 ;
        RECT  13.872 21.528 13.896 21.672 ;
    END
  END b[2]
  PIN b[300]
    DIRECTION OUTPUT ;
    USE SIGNAL ;
    PORT
      LAYER M5 ;
        RECT  71.088 21.528 71.112 21.672 ;
    END
  END b[300]
  PIN b[301]
    DIRECTION OUTPUT ;
    USE SIGNAL ;
    PORT
      LAYER M5 ;
        RECT  71.28 21.528 71.304 21.672 ;
    END
  END b[301]
  PIN b[302]
    DIRECTION OUTPUT ;
    USE SIGNAL ;
    PORT
      LAYER M5 ;
        RECT  71.472 21.528 71.496 21.672 ;
    END
  END b[302]
  PIN b[303]
    DIRECTION OUTPUT ;
    USE SIGNAL ;
    PORT
      LAYER M5 ;
        RECT  71.664 21.528 71.688 21.672 ;
    END
  END b[303]
  PIN b[304]
    DIRECTION OUTPUT ;
    USE SIGNAL ;
    PORT
      LAYER M5 ;
        RECT  71.856 21.528 71.88 21.672 ;
    END
  END b[304]
  PIN b[305]
    DIRECTION OUTPUT ;
    USE SIGNAL ;
    PORT
      LAYER M5 ;
        RECT  72.048 21.528 72.072 21.672 ;
    END
  END b[305]
  PIN b[306]
    DIRECTION OUTPUT ;
    USE SIGNAL ;
    PORT
      LAYER M5 ;
        RECT  72.24 21.528 72.264 21.672 ;
    END
  END b[306]
  PIN b[307]
    DIRECTION OUTPUT ;
    USE SIGNAL ;
    PORT
      LAYER M5 ;
        RECT  72.432 21.528 72.456 21.672 ;
    END
  END b[307]
  PIN b[308]
    DIRECTION OUTPUT ;
    USE SIGNAL ;
    PORT
      LAYER M5 ;
        RECT  72.624 21.528 72.648 21.672 ;
    END
  END b[308]
  PIN b[309]
    DIRECTION OUTPUT ;
    USE SIGNAL ;
    PORT
      LAYER M5 ;
        RECT  72.816 21.528 72.84 21.672 ;
    END
  END b[309]
  PIN b[30]
    DIRECTION OUTPUT ;
    USE SIGNAL ;
    PORT
      LAYER M5 ;
        RECT  19.248 21.528 19.272 21.672 ;
    END
  END b[30]
  PIN b[310]
    DIRECTION OUTPUT ;
    USE SIGNAL ;
    PORT
      LAYER M5 ;
        RECT  73.008 21.528 73.032 21.672 ;
    END
  END b[310]
  PIN b[311]
    DIRECTION OUTPUT ;
    USE SIGNAL ;
    PORT
      LAYER M5 ;
        RECT  73.2 21.528 73.224 21.672 ;
    END
  END b[311]
  PIN b[312]
    DIRECTION OUTPUT ;
    USE SIGNAL ;
    PORT
      LAYER M5 ;
        RECT  73.392 21.528 73.416 21.672 ;
    END
  END b[312]
  PIN b[313]
    DIRECTION OUTPUT ;
    USE SIGNAL ;
    PORT
      LAYER M5 ;
        RECT  73.584 21.528 73.608 21.672 ;
    END
  END b[313]
  PIN b[314]
    DIRECTION OUTPUT ;
    USE SIGNAL ;
    PORT
      LAYER M5 ;
        RECT  73.776 21.528 73.8 21.672 ;
    END
  END b[314]
  PIN b[315]
    DIRECTION OUTPUT ;
    USE SIGNAL ;
    PORT
      LAYER M5 ;
        RECT  73.968 21.528 73.992 21.672 ;
    END
  END b[315]
  PIN b[316]
    DIRECTION OUTPUT ;
    USE SIGNAL ;
    PORT
      LAYER M5 ;
        RECT  74.16 21.528 74.184 21.672 ;
    END
  END b[316]
  PIN b[317]
    DIRECTION OUTPUT ;
    USE SIGNAL ;
    PORT
      LAYER M5 ;
        RECT  74.352 21.528 74.376 21.672 ;
    END
  END b[317]
  PIN b[318]
    DIRECTION OUTPUT ;
    USE SIGNAL ;
    PORT
      LAYER M5 ;
        RECT  74.544 21.528 74.568 21.672 ;
    END
  END b[318]
  PIN b[319]
    DIRECTION OUTPUT ;
    USE SIGNAL ;
    PORT
      LAYER M5 ;
        RECT  74.736 21.528 74.76 21.672 ;
    END
  END b[319]
  PIN b[31]
    DIRECTION OUTPUT ;
    USE SIGNAL ;
    PORT
      LAYER M5 ;
        RECT  19.44 21.528 19.464 21.672 ;
    END
  END b[31]
  PIN b[320]
    DIRECTION OUTPUT ;
    USE SIGNAL ;
    PORT
      LAYER M5 ;
        RECT  74.928 21.528 74.952 21.672 ;
    END
  END b[320]
  PIN b[321]
    DIRECTION OUTPUT ;
    USE SIGNAL ;
    PORT
      LAYER M5 ;
        RECT  75.12 21.528 75.144 21.672 ;
    END
  END b[321]
  PIN b[322]
    DIRECTION OUTPUT ;
    USE SIGNAL ;
    PORT
      LAYER M5 ;
        RECT  75.312 21.528 75.336 21.672 ;
    END
  END b[322]
  PIN b[323]
    DIRECTION OUTPUT ;
    USE SIGNAL ;
    PORT
      LAYER M5 ;
        RECT  75.504 21.528 75.528 21.672 ;
    END
  END b[323]
  PIN b[324]
    DIRECTION OUTPUT ;
    USE SIGNAL ;
    PORT
      LAYER M5 ;
        RECT  75.696 21.528 75.72 21.672 ;
    END
  END b[324]
  PIN b[325]
    DIRECTION OUTPUT ;
    USE SIGNAL ;
    PORT
      LAYER M5 ;
        RECT  75.888 21.528 75.912 21.672 ;
    END
  END b[325]
  PIN b[326]
    DIRECTION OUTPUT ;
    USE SIGNAL ;
    PORT
      LAYER M5 ;
        RECT  76.08 21.528 76.104 21.672 ;
    END
  END b[326]
  PIN b[327]
    DIRECTION OUTPUT ;
    USE SIGNAL ;
    PORT
      LAYER M5 ;
        RECT  76.272 21.528 76.296 21.672 ;
    END
  END b[327]
  PIN b[328]
    DIRECTION OUTPUT ;
    USE SIGNAL ;
    PORT
      LAYER M5 ;
        RECT  76.464 21.528 76.488 21.672 ;
    END
  END b[328]
  PIN b[329]
    DIRECTION OUTPUT ;
    USE SIGNAL ;
    PORT
      LAYER M5 ;
        RECT  76.656 21.528 76.68 21.672 ;
    END
  END b[329]
  PIN b[32]
    DIRECTION OUTPUT ;
    USE SIGNAL ;
    PORT
      LAYER M5 ;
        RECT  19.632 21.528 19.656 21.672 ;
    END
  END b[32]
  PIN b[330]
    DIRECTION OUTPUT ;
    USE SIGNAL ;
    PORT
      LAYER M5 ;
        RECT  76.848 21.528 76.872 21.672 ;
    END
  END b[330]
  PIN b[331]
    DIRECTION OUTPUT ;
    USE SIGNAL ;
    PORT
      LAYER M5 ;
        RECT  77.04 21.528 77.064 21.672 ;
    END
  END b[331]
  PIN b[332]
    DIRECTION OUTPUT ;
    USE SIGNAL ;
    PORT
      LAYER M5 ;
        RECT  77.232 21.528 77.256 21.672 ;
    END
  END b[332]
  PIN b[333]
    DIRECTION OUTPUT ;
    USE SIGNAL ;
    PORT
      LAYER M5 ;
        RECT  77.424 21.528 77.448 21.672 ;
    END
  END b[333]
  PIN b[334]
    DIRECTION OUTPUT ;
    USE SIGNAL ;
    PORT
      LAYER M5 ;
        RECT  77.616 21.528 77.64 21.672 ;
    END
  END b[334]
  PIN b[335]
    DIRECTION OUTPUT ;
    USE SIGNAL ;
    PORT
      LAYER M5 ;
        RECT  77.808 21.528 77.832 21.672 ;
    END
  END b[335]
  PIN b[336]
    DIRECTION OUTPUT ;
    USE SIGNAL ;
    PORT
      LAYER M5 ;
        RECT  78 21.528 78.024 21.672 ;
    END
  END b[336]
  PIN b[337]
    DIRECTION OUTPUT ;
    USE SIGNAL ;
    PORT
      LAYER M5 ;
        RECT  78.192 21.528 78.216 21.672 ;
    END
  END b[337]
  PIN b[338]
    DIRECTION OUTPUT ;
    USE SIGNAL ;
    PORT
      LAYER M5 ;
        RECT  78.384 21.528 78.408 21.672 ;
    END
  END b[338]
  PIN b[339]
    DIRECTION OUTPUT ;
    USE SIGNAL ;
    PORT
      LAYER M5 ;
        RECT  78.576 21.528 78.6 21.672 ;
    END
  END b[339]
  PIN b[33]
    DIRECTION OUTPUT ;
    USE SIGNAL ;
    PORT
      LAYER M5 ;
        RECT  19.824 21.528 19.848 21.672 ;
    END
  END b[33]
  PIN b[340]
    DIRECTION OUTPUT ;
    USE SIGNAL ;
    PORT
      LAYER M5 ;
        RECT  78.768 21.528 78.792 21.672 ;
    END
  END b[340]
  PIN b[341]
    DIRECTION OUTPUT ;
    USE SIGNAL ;
    PORT
      LAYER M5 ;
        RECT  78.96 21.528 78.984 21.672 ;
    END
  END b[341]
  PIN b[342]
    DIRECTION OUTPUT ;
    USE SIGNAL ;
    PORT
      LAYER M5 ;
        RECT  79.152 21.528 79.176 21.672 ;
    END
  END b[342]
  PIN b[343]
    DIRECTION OUTPUT ;
    USE SIGNAL ;
    PORT
      LAYER M5 ;
        RECT  79.344 21.528 79.368 21.672 ;
    END
  END b[343]
  PIN b[344]
    DIRECTION OUTPUT ;
    USE SIGNAL ;
    PORT
      LAYER M5 ;
        RECT  79.536 21.528 79.56 21.672 ;
    END
  END b[344]
  PIN b[345]
    DIRECTION OUTPUT ;
    USE SIGNAL ;
    PORT
      LAYER M5 ;
        RECT  79.728 21.528 79.752 21.672 ;
    END
  END b[345]
  PIN b[346]
    DIRECTION OUTPUT ;
    USE SIGNAL ;
    PORT
      LAYER M5 ;
        RECT  79.92 21.528 79.944 21.672 ;
    END
  END b[346]
  PIN b[347]
    DIRECTION OUTPUT ;
    USE SIGNAL ;
    PORT
      LAYER M5 ;
        RECT  80.112 21.528 80.136 21.672 ;
    END
  END b[347]
  PIN b[348]
    DIRECTION OUTPUT ;
    USE SIGNAL ;
    PORT
      LAYER M5 ;
        RECT  80.304 21.528 80.328 21.672 ;
    END
  END b[348]
  PIN b[349]
    DIRECTION OUTPUT ;
    USE SIGNAL ;
    PORT
      LAYER M5 ;
        RECT  80.496 21.528 80.52 21.672 ;
    END
  END b[349]
  PIN b[34]
    DIRECTION OUTPUT ;
    USE SIGNAL ;
    PORT
      LAYER M5 ;
        RECT  20.016 21.528 20.04 21.672 ;
    END
  END b[34]
  PIN b[350]
    DIRECTION OUTPUT ;
    USE SIGNAL ;
    PORT
      LAYER M5 ;
        RECT  80.688 21.528 80.712 21.672 ;
    END
  END b[350]
  PIN b[351]
    DIRECTION OUTPUT ;
    USE SIGNAL ;
    PORT
      LAYER M5 ;
        RECT  80.88 21.528 80.904 21.672 ;
    END
  END b[351]
  PIN b[352]
    DIRECTION OUTPUT ;
    USE SIGNAL ;
    PORT
      LAYER M5 ;
        RECT  81.072 21.528 81.096 21.672 ;
    END
  END b[352]
  PIN b[353]
    DIRECTION OUTPUT ;
    USE SIGNAL ;
    PORT
      LAYER M5 ;
        RECT  81.264 21.528 81.288 21.672 ;
    END
  END b[353]
  PIN b[354]
    DIRECTION OUTPUT ;
    USE SIGNAL ;
    PORT
      LAYER M5 ;
        RECT  81.456 21.528 81.48 21.672 ;
    END
  END b[354]
  PIN b[355]
    DIRECTION OUTPUT ;
    USE SIGNAL ;
    PORT
      LAYER M5 ;
        RECT  81.648 21.528 81.672 21.672 ;
    END
  END b[355]
  PIN b[356]
    DIRECTION OUTPUT ;
    USE SIGNAL ;
    PORT
      LAYER M5 ;
        RECT  81.84 21.528 81.864 21.672 ;
    END
  END b[356]
  PIN b[357]
    DIRECTION OUTPUT ;
    USE SIGNAL ;
    PORT
      LAYER M5 ;
        RECT  82.032 21.528 82.056 21.672 ;
    END
  END b[357]
  PIN b[358]
    DIRECTION OUTPUT ;
    USE SIGNAL ;
    PORT
      LAYER M5 ;
        RECT  82.224 21.528 82.248 21.672 ;
    END
  END b[358]
  PIN b[359]
    DIRECTION OUTPUT ;
    USE SIGNAL ;
    PORT
      LAYER M5 ;
        RECT  82.416 21.528 82.44 21.672 ;
    END
  END b[359]
  PIN b[35]
    DIRECTION OUTPUT ;
    USE SIGNAL ;
    PORT
      LAYER M5 ;
        RECT  20.208 21.528 20.232 21.672 ;
    END
  END b[35]
  PIN b[360]
    DIRECTION OUTPUT ;
    USE SIGNAL ;
    PORT
      LAYER M5 ;
        RECT  82.608 21.528 82.632 21.672 ;
    END
  END b[360]
  PIN b[361]
    DIRECTION OUTPUT ;
    USE SIGNAL ;
    PORT
      LAYER M5 ;
        RECT  82.8 21.528 82.824 21.672 ;
    END
  END b[361]
  PIN b[362]
    DIRECTION OUTPUT ;
    USE SIGNAL ;
    PORT
      LAYER M5 ;
        RECT  82.992 21.528 83.016 21.672 ;
    END
  END b[362]
  PIN b[363]
    DIRECTION OUTPUT ;
    USE SIGNAL ;
    PORT
      LAYER M5 ;
        RECT  83.184 21.528 83.208 21.672 ;
    END
  END b[363]
  PIN b[364]
    DIRECTION OUTPUT ;
    USE SIGNAL ;
    PORT
      LAYER M5 ;
        RECT  83.376 21.528 83.4 21.672 ;
    END
  END b[364]
  PIN b[365]
    DIRECTION OUTPUT ;
    USE SIGNAL ;
    PORT
      LAYER M5 ;
        RECT  83.568 21.528 83.592 21.672 ;
    END
  END b[365]
  PIN b[366]
    DIRECTION OUTPUT ;
    USE SIGNAL ;
    PORT
      LAYER M5 ;
        RECT  83.76 21.528 83.784 21.672 ;
    END
  END b[366]
  PIN b[367]
    DIRECTION OUTPUT ;
    USE SIGNAL ;
    PORT
      LAYER M5 ;
        RECT  83.952 21.528 83.976 21.672 ;
    END
  END b[367]
  PIN b[368]
    DIRECTION OUTPUT ;
    USE SIGNAL ;
    PORT
      LAYER M5 ;
        RECT  84.144 21.528 84.168 21.672 ;
    END
  END b[368]
  PIN b[369]
    DIRECTION OUTPUT ;
    USE SIGNAL ;
    PORT
      LAYER M5 ;
        RECT  84.336 21.528 84.36 21.672 ;
    END
  END b[369]
  PIN b[36]
    DIRECTION OUTPUT ;
    USE SIGNAL ;
    PORT
      LAYER M5 ;
        RECT  20.4 21.528 20.424 21.672 ;
    END
  END b[36]
  PIN b[370]
    DIRECTION OUTPUT ;
    USE SIGNAL ;
    PORT
      LAYER M5 ;
        RECT  84.528 21.528 84.552 21.672 ;
    END
  END b[370]
  PIN b[371]
    DIRECTION OUTPUT ;
    USE SIGNAL ;
    PORT
      LAYER M5 ;
        RECT  84.72 21.528 84.744 21.672 ;
    END
  END b[371]
  PIN b[372]
    DIRECTION OUTPUT ;
    USE SIGNAL ;
    PORT
      LAYER M5 ;
        RECT  84.912 21.528 84.936 21.672 ;
    END
  END b[372]
  PIN b[373]
    DIRECTION OUTPUT ;
    USE SIGNAL ;
    PORT
      LAYER M5 ;
        RECT  85.104 21.528 85.128 21.672 ;
    END
  END b[373]
  PIN b[374]
    DIRECTION OUTPUT ;
    USE SIGNAL ;
    PORT
      LAYER M5 ;
        RECT  85.296 21.528 85.32 21.672 ;
    END
  END b[374]
  PIN b[375]
    DIRECTION OUTPUT ;
    USE SIGNAL ;
    PORT
      LAYER M5 ;
        RECT  85.488 21.528 85.512 21.672 ;
    END
  END b[375]
  PIN b[376]
    DIRECTION OUTPUT ;
    USE SIGNAL ;
    PORT
      LAYER M5 ;
        RECT  85.68 21.528 85.704 21.672 ;
    END
  END b[376]
  PIN b[377]
    DIRECTION OUTPUT ;
    USE SIGNAL ;
    PORT
      LAYER M5 ;
        RECT  85.872 21.528 85.896 21.672 ;
    END
  END b[377]
  PIN b[378]
    DIRECTION OUTPUT ;
    USE SIGNAL ;
    PORT
      LAYER M5 ;
        RECT  86.064 21.528 86.088 21.672 ;
    END
  END b[378]
  PIN b[379]
    DIRECTION OUTPUT ;
    USE SIGNAL ;
    PORT
      LAYER M5 ;
        RECT  86.256 21.528 86.28 21.672 ;
    END
  END b[379]
  PIN b[37]
    DIRECTION OUTPUT ;
    USE SIGNAL ;
    PORT
      LAYER M5 ;
        RECT  20.592 21.528 20.616 21.672 ;
    END
  END b[37]
  PIN b[380]
    DIRECTION OUTPUT ;
    USE SIGNAL ;
    PORT
      LAYER M5 ;
        RECT  86.448 21.528 86.472 21.672 ;
    END
  END b[380]
  PIN b[381]
    DIRECTION OUTPUT ;
    USE SIGNAL ;
    PORT
      LAYER M5 ;
        RECT  86.64 21.528 86.664 21.672 ;
    END
  END b[381]
  PIN b[382]
    DIRECTION OUTPUT ;
    USE SIGNAL ;
    PORT
      LAYER M5 ;
        RECT  86.832 21.528 86.856 21.672 ;
    END
  END b[382]
  PIN b[383]
    DIRECTION OUTPUT ;
    USE SIGNAL ;
    PORT
      LAYER M5 ;
        RECT  87.024 21.528 87.048 21.672 ;
    END
  END b[383]
  PIN b[384]
    DIRECTION OUTPUT ;
    USE SIGNAL ;
    PORT
      LAYER M5 ;
        RECT  87.216 21.528 87.24 21.672 ;
    END
  END b[384]
  PIN b[385]
    DIRECTION OUTPUT ;
    USE SIGNAL ;
    PORT
      LAYER M5 ;
        RECT  87.408 21.528 87.432 21.672 ;
    END
  END b[385]
  PIN b[386]
    DIRECTION OUTPUT ;
    USE SIGNAL ;
    PORT
      LAYER M5 ;
        RECT  87.6 21.528 87.624 21.672 ;
    END
  END b[386]
  PIN b[387]
    DIRECTION OUTPUT ;
    USE SIGNAL ;
    PORT
      LAYER M5 ;
        RECT  87.792 21.528 87.816 21.672 ;
    END
  END b[387]
  PIN b[388]
    DIRECTION OUTPUT ;
    USE SIGNAL ;
    PORT
      LAYER M5 ;
        RECT  87.984 21.528 88.008 21.672 ;
    END
  END b[388]
  PIN b[389]
    DIRECTION OUTPUT ;
    USE SIGNAL ;
    PORT
      LAYER M5 ;
        RECT  88.176 21.528 88.2 21.672 ;
    END
  END b[389]
  PIN b[38]
    DIRECTION OUTPUT ;
    USE SIGNAL ;
    PORT
      LAYER M5 ;
        RECT  20.784 21.528 20.808 21.672 ;
    END
  END b[38]
  PIN b[390]
    DIRECTION OUTPUT ;
    USE SIGNAL ;
    PORT
      LAYER M5 ;
        RECT  88.368 21.528 88.392 21.672 ;
    END
  END b[390]
  PIN b[391]
    DIRECTION OUTPUT ;
    USE SIGNAL ;
    PORT
      LAYER M5 ;
        RECT  88.56 21.528 88.584 21.672 ;
    END
  END b[391]
  PIN b[392]
    DIRECTION OUTPUT ;
    USE SIGNAL ;
    PORT
      LAYER M5 ;
        RECT  88.752 21.528 88.776 21.672 ;
    END
  END b[392]
  PIN b[393]
    DIRECTION OUTPUT ;
    USE SIGNAL ;
    PORT
      LAYER M5 ;
        RECT  88.944 21.528 88.968 21.672 ;
    END
  END b[393]
  PIN b[394]
    DIRECTION OUTPUT ;
    USE SIGNAL ;
    PORT
      LAYER M5 ;
        RECT  89.136 21.528 89.16 21.672 ;
    END
  END b[394]
  PIN b[395]
    DIRECTION OUTPUT ;
    USE SIGNAL ;
    PORT
      LAYER M5 ;
        RECT  89.328 21.528 89.352 21.672 ;
    END
  END b[395]
  PIN b[396]
    DIRECTION OUTPUT ;
    USE SIGNAL ;
    PORT
      LAYER M5 ;
        RECT  89.52 21.528 89.544 21.672 ;
    END
  END b[396]
  PIN b[397]
    DIRECTION OUTPUT ;
    USE SIGNAL ;
    PORT
      LAYER M5 ;
        RECT  89.712 21.528 89.736 21.672 ;
    END
  END b[397]
  PIN b[398]
    DIRECTION OUTPUT ;
    USE SIGNAL ;
    PORT
      LAYER M5 ;
        RECT  89.904 21.528 89.928 21.672 ;
    END
  END b[398]
  PIN b[399]
    DIRECTION OUTPUT ;
    USE SIGNAL ;
    PORT
      LAYER M5 ;
        RECT  90.096 21.528 90.12 21.672 ;
    END
  END b[399]
  PIN b[39]
    DIRECTION OUTPUT ;
    USE SIGNAL ;
    PORT
      LAYER M5 ;
        RECT  20.976 21.528 21 21.672 ;
    END
  END b[39]
  PIN b[3]
    DIRECTION OUTPUT ;
    USE SIGNAL ;
    PORT
      LAYER M5 ;
        RECT  14.064 21.528 14.088 21.672 ;
    END
  END b[3]
  PIN b[400]
    DIRECTION OUTPUT ;
    USE SIGNAL ;
    PORT
      LAYER M5 ;
        RECT  90.288 21.528 90.312 21.672 ;
    END
  END b[400]
  PIN b[401]
    DIRECTION OUTPUT ;
    USE SIGNAL ;
    PORT
      LAYER M5 ;
        RECT  90.48 21.528 90.504 21.672 ;
    END
  END b[401]
  PIN b[402]
    DIRECTION OUTPUT ;
    USE SIGNAL ;
    PORT
      LAYER M5 ;
        RECT  90.672 21.528 90.696 21.672 ;
    END
  END b[402]
  PIN b[403]
    DIRECTION OUTPUT ;
    USE SIGNAL ;
    PORT
      LAYER M5 ;
        RECT  90.864 21.528 90.888 21.672 ;
    END
  END b[403]
  PIN b[404]
    DIRECTION OUTPUT ;
    USE SIGNAL ;
    PORT
      LAYER M5 ;
        RECT  91.056 21.528 91.08 21.672 ;
    END
  END b[404]
  PIN b[405]
    DIRECTION OUTPUT ;
    USE SIGNAL ;
    PORT
      LAYER M5 ;
        RECT  91.248 21.528 91.272 21.672 ;
    END
  END b[405]
  PIN b[406]
    DIRECTION OUTPUT ;
    USE SIGNAL ;
    PORT
      LAYER M5 ;
        RECT  91.44 21.528 91.464 21.672 ;
    END
  END b[406]
  PIN b[407]
    DIRECTION OUTPUT ;
    USE SIGNAL ;
    PORT
      LAYER M5 ;
        RECT  91.632 21.528 91.656 21.672 ;
    END
  END b[407]
  PIN b[408]
    DIRECTION OUTPUT ;
    USE SIGNAL ;
    PORT
      LAYER M5 ;
        RECT  91.824 21.528 91.848 21.672 ;
    END
  END b[408]
  PIN b[409]
    DIRECTION OUTPUT ;
    USE SIGNAL ;
    PORT
      LAYER M5 ;
        RECT  92.016 21.528 92.04 21.672 ;
    END
  END b[409]
  PIN b[40]
    DIRECTION OUTPUT ;
    USE SIGNAL ;
    PORT
      LAYER M5 ;
        RECT  21.168 21.528 21.192 21.672 ;
    END
  END b[40]
  PIN b[410]
    DIRECTION OUTPUT ;
    USE SIGNAL ;
    PORT
      LAYER M5 ;
        RECT  92.208 21.528 92.232 21.672 ;
    END
  END b[410]
  PIN b[411]
    DIRECTION OUTPUT ;
    USE SIGNAL ;
    PORT
      LAYER M5 ;
        RECT  92.4 21.528 92.424 21.672 ;
    END
  END b[411]
  PIN b[412]
    DIRECTION OUTPUT ;
    USE SIGNAL ;
    PORT
      LAYER M5 ;
        RECT  92.592 21.528 92.616 21.672 ;
    END
  END b[412]
  PIN b[413]
    DIRECTION OUTPUT ;
    USE SIGNAL ;
    PORT
      LAYER M5 ;
        RECT  92.784 21.528 92.808 21.672 ;
    END
  END b[413]
  PIN b[414]
    DIRECTION OUTPUT ;
    USE SIGNAL ;
    PORT
      LAYER M5 ;
        RECT  92.976 21.528 93 21.672 ;
    END
  END b[414]
  PIN b[415]
    DIRECTION OUTPUT ;
    USE SIGNAL ;
    PORT
      LAYER M5 ;
        RECT  93.168 21.528 93.192 21.672 ;
    END
  END b[415]
  PIN b[416]
    DIRECTION OUTPUT ;
    USE SIGNAL ;
    PORT
      LAYER M5 ;
        RECT  93.36 21.528 93.384 21.672 ;
    END
  END b[416]
  PIN b[417]
    DIRECTION OUTPUT ;
    USE SIGNAL ;
    PORT
      LAYER M5 ;
        RECT  93.552 21.528 93.576 21.672 ;
    END
  END b[417]
  PIN b[418]
    DIRECTION OUTPUT ;
    USE SIGNAL ;
    PORT
      LAYER M5 ;
        RECT  93.744 21.528 93.768 21.672 ;
    END
  END b[418]
  PIN b[419]
    DIRECTION OUTPUT ;
    USE SIGNAL ;
    PORT
      LAYER M5 ;
        RECT  93.936 21.528 93.96 21.672 ;
    END
  END b[419]
  PIN b[41]
    DIRECTION OUTPUT ;
    USE SIGNAL ;
    PORT
      LAYER M5 ;
        RECT  21.36 21.528 21.384 21.672 ;
    END
  END b[41]
  PIN b[420]
    DIRECTION OUTPUT ;
    USE SIGNAL ;
    PORT
      LAYER M5 ;
        RECT  94.128 21.528 94.152 21.672 ;
    END
  END b[420]
  PIN b[421]
    DIRECTION OUTPUT ;
    USE SIGNAL ;
    PORT
      LAYER M5 ;
        RECT  94.32 21.528 94.344 21.672 ;
    END
  END b[421]
  PIN b[422]
    DIRECTION OUTPUT ;
    USE SIGNAL ;
    PORT
      LAYER M5 ;
        RECT  94.512 21.528 94.536 21.672 ;
    END
  END b[422]
  PIN b[423]
    DIRECTION OUTPUT ;
    USE SIGNAL ;
    PORT
      LAYER M5 ;
        RECT  94.704 21.528 94.728 21.672 ;
    END
  END b[423]
  PIN b[424]
    DIRECTION OUTPUT ;
    USE SIGNAL ;
    PORT
      LAYER M5 ;
        RECT  94.896 21.528 94.92 21.672 ;
    END
  END b[424]
  PIN b[425]
    DIRECTION OUTPUT ;
    USE SIGNAL ;
    PORT
      LAYER M5 ;
        RECT  95.088 21.528 95.112 21.672 ;
    END
  END b[425]
  PIN b[426]
    DIRECTION OUTPUT ;
    USE SIGNAL ;
    PORT
      LAYER M5 ;
        RECT  95.28 21.528 95.304 21.672 ;
    END
  END b[426]
  PIN b[427]
    DIRECTION OUTPUT ;
    USE SIGNAL ;
    PORT
      LAYER M5 ;
        RECT  95.472 21.528 95.496 21.672 ;
    END
  END b[427]
  PIN b[428]
    DIRECTION OUTPUT ;
    USE SIGNAL ;
    PORT
      LAYER M5 ;
        RECT  95.664 21.528 95.688 21.672 ;
    END
  END b[428]
  PIN b[429]
    DIRECTION OUTPUT ;
    USE SIGNAL ;
    PORT
      LAYER M5 ;
        RECT  95.856 21.528 95.88 21.672 ;
    END
  END b[429]
  PIN b[42]
    DIRECTION OUTPUT ;
    USE SIGNAL ;
    PORT
      LAYER M5 ;
        RECT  21.552 21.528 21.576 21.672 ;
    END
  END b[42]
  PIN b[430]
    DIRECTION OUTPUT ;
    USE SIGNAL ;
    PORT
      LAYER M5 ;
        RECT  96.048 21.528 96.072 21.672 ;
    END
  END b[430]
  PIN b[431]
    DIRECTION OUTPUT ;
    USE SIGNAL ;
    PORT
      LAYER M5 ;
        RECT  96.24 21.528 96.264 21.672 ;
    END
  END b[431]
  PIN b[432]
    DIRECTION OUTPUT ;
    USE SIGNAL ;
    PORT
      LAYER M5 ;
        RECT  96.432 21.528 96.456 21.672 ;
    END
  END b[432]
  PIN b[433]
    DIRECTION OUTPUT ;
    USE SIGNAL ;
    PORT
      LAYER M5 ;
        RECT  96.624 21.528 96.648 21.672 ;
    END
  END b[433]
  PIN b[434]
    DIRECTION OUTPUT ;
    USE SIGNAL ;
    PORT
      LAYER M5 ;
        RECT  96.816 21.528 96.84 21.672 ;
    END
  END b[434]
  PIN b[435]
    DIRECTION OUTPUT ;
    USE SIGNAL ;
    PORT
      LAYER M5 ;
        RECT  97.008 21.528 97.032 21.672 ;
    END
  END b[435]
  PIN b[436]
    DIRECTION OUTPUT ;
    USE SIGNAL ;
    PORT
      LAYER M5 ;
        RECT  97.2 21.528 97.224 21.672 ;
    END
  END b[436]
  PIN b[437]
    DIRECTION OUTPUT ;
    USE SIGNAL ;
    PORT
      LAYER M5 ;
        RECT  97.392 21.528 97.416 21.672 ;
    END
  END b[437]
  PIN b[438]
    DIRECTION OUTPUT ;
    USE SIGNAL ;
    PORT
      LAYER M5 ;
        RECT  97.584 21.528 97.608 21.672 ;
    END
  END b[438]
  PIN b[439]
    DIRECTION OUTPUT ;
    USE SIGNAL ;
    PORT
      LAYER M5 ;
        RECT  97.776 21.528 97.8 21.672 ;
    END
  END b[439]
  PIN b[43]
    DIRECTION OUTPUT ;
    USE SIGNAL ;
    PORT
      LAYER M5 ;
        RECT  21.744 21.528 21.768 21.672 ;
    END
  END b[43]
  PIN b[440]
    DIRECTION OUTPUT ;
    USE SIGNAL ;
    PORT
      LAYER M5 ;
        RECT  97.968 21.528 97.992 21.672 ;
    END
  END b[440]
  PIN b[441]
    DIRECTION OUTPUT ;
    USE SIGNAL ;
    PORT
      LAYER M5 ;
        RECT  98.16 21.528 98.184 21.672 ;
    END
  END b[441]
  PIN b[442]
    DIRECTION OUTPUT ;
    USE SIGNAL ;
    PORT
      LAYER M5 ;
        RECT  98.352 21.528 98.376 21.672 ;
    END
  END b[442]
  PIN b[443]
    DIRECTION OUTPUT ;
    USE SIGNAL ;
    PORT
      LAYER M5 ;
        RECT  98.544 21.528 98.568 21.672 ;
    END
  END b[443]
  PIN b[444]
    DIRECTION OUTPUT ;
    USE SIGNAL ;
    PORT
      LAYER M5 ;
        RECT  98.736 21.528 98.76 21.672 ;
    END
  END b[444]
  PIN b[445]
    DIRECTION OUTPUT ;
    USE SIGNAL ;
    PORT
      LAYER M5 ;
        RECT  98.928 21.528 98.952 21.672 ;
    END
  END b[445]
  PIN b[446]
    DIRECTION OUTPUT ;
    USE SIGNAL ;
    PORT
      LAYER M5 ;
        RECT  99.12 21.528 99.144 21.672 ;
    END
  END b[446]
  PIN b[447]
    DIRECTION OUTPUT ;
    USE SIGNAL ;
    PORT
      LAYER M5 ;
        RECT  99.312 21.528 99.336 21.672 ;
    END
  END b[447]
  PIN b[448]
    DIRECTION OUTPUT ;
    USE SIGNAL ;
    PORT
      LAYER M5 ;
        RECT  99.504 21.528 99.528 21.672 ;
    END
  END b[448]
  PIN b[449]
    DIRECTION OUTPUT ;
    USE SIGNAL ;
    PORT
      LAYER M5 ;
        RECT  99.696 21.528 99.72 21.672 ;
    END
  END b[449]
  PIN b[44]
    DIRECTION OUTPUT ;
    USE SIGNAL ;
    PORT
      LAYER M5 ;
        RECT  21.936 21.528 21.96 21.672 ;
    END
  END b[44]
  PIN b[450]
    DIRECTION OUTPUT ;
    USE SIGNAL ;
    PORT
      LAYER M5 ;
        RECT  99.888 21.528 99.912 21.672 ;
    END
  END b[450]
  PIN b[451]
    DIRECTION OUTPUT ;
    USE SIGNAL ;
    PORT
      LAYER M5 ;
        RECT  100.08 21.528 100.104 21.672 ;
    END
  END b[451]
  PIN b[452]
    DIRECTION OUTPUT ;
    USE SIGNAL ;
    PORT
      LAYER M5 ;
        RECT  100.272 21.528 100.296 21.672 ;
    END
  END b[452]
  PIN b[453]
    DIRECTION OUTPUT ;
    USE SIGNAL ;
    PORT
      LAYER M5 ;
        RECT  100.464 21.528 100.488 21.672 ;
    END
  END b[453]
  PIN b[454]
    DIRECTION OUTPUT ;
    USE SIGNAL ;
    PORT
      LAYER M5 ;
        RECT  100.656 21.528 100.68 21.672 ;
    END
  END b[454]
  PIN b[455]
    DIRECTION OUTPUT ;
    USE SIGNAL ;
    PORT
      LAYER M5 ;
        RECT  100.848 21.528 100.872 21.672 ;
    END
  END b[455]
  PIN b[456]
    DIRECTION OUTPUT ;
    USE SIGNAL ;
    PORT
      LAYER M5 ;
        RECT  101.04 21.528 101.064 21.672 ;
    END
  END b[456]
  PIN b[457]
    DIRECTION OUTPUT ;
    USE SIGNAL ;
    PORT
      LAYER M5 ;
        RECT  101.232 21.528 101.256 21.672 ;
    END
  END b[457]
  PIN b[458]
    DIRECTION OUTPUT ;
    USE SIGNAL ;
    PORT
      LAYER M5 ;
        RECT  101.424 21.528 101.448 21.672 ;
    END
  END b[458]
  PIN b[459]
    DIRECTION OUTPUT ;
    USE SIGNAL ;
    PORT
      LAYER M5 ;
        RECT  101.616 21.528 101.64 21.672 ;
    END
  END b[459]
  PIN b[45]
    DIRECTION OUTPUT ;
    USE SIGNAL ;
    PORT
      LAYER M5 ;
        RECT  22.128 21.528 22.152 21.672 ;
    END
  END b[45]
  PIN b[460]
    DIRECTION OUTPUT ;
    USE SIGNAL ;
    PORT
      LAYER M5 ;
        RECT  101.808 21.528 101.832 21.672 ;
    END
  END b[460]
  PIN b[461]
    DIRECTION OUTPUT ;
    USE SIGNAL ;
    PORT
      LAYER M5 ;
        RECT  102 21.528 102.024 21.672 ;
    END
  END b[461]
  PIN b[462]
    DIRECTION OUTPUT ;
    USE SIGNAL ;
    PORT
      LAYER M5 ;
        RECT  102.192 21.528 102.216 21.672 ;
    END
  END b[462]
  PIN b[463]
    DIRECTION OUTPUT ;
    USE SIGNAL ;
    PORT
      LAYER M5 ;
        RECT  102.384 21.528 102.408 21.672 ;
    END
  END b[463]
  PIN b[464]
    DIRECTION OUTPUT ;
    USE SIGNAL ;
    PORT
      LAYER M5 ;
        RECT  102.576 21.528 102.6 21.672 ;
    END
  END b[464]
  PIN b[465]
    DIRECTION OUTPUT ;
    USE SIGNAL ;
    PORT
      LAYER M5 ;
        RECT  102.768 21.528 102.792 21.672 ;
    END
  END b[465]
  PIN b[466]
    DIRECTION OUTPUT ;
    USE SIGNAL ;
    PORT
      LAYER M5 ;
        RECT  102.96 21.528 102.984 21.672 ;
    END
  END b[466]
  PIN b[467]
    DIRECTION OUTPUT ;
    USE SIGNAL ;
    PORT
      LAYER M5 ;
        RECT  103.152 21.528 103.176 21.672 ;
    END
  END b[467]
  PIN b[468]
    DIRECTION OUTPUT ;
    USE SIGNAL ;
    PORT
      LAYER M5 ;
        RECT  103.344 21.528 103.368 21.672 ;
    END
  END b[468]
  PIN b[469]
    DIRECTION OUTPUT ;
    USE SIGNAL ;
    PORT
      LAYER M5 ;
        RECT  103.536 21.528 103.56 21.672 ;
    END
  END b[469]
  PIN b[46]
    DIRECTION OUTPUT ;
    USE SIGNAL ;
    PORT
      LAYER M5 ;
        RECT  22.32 21.528 22.344 21.672 ;
    END
  END b[46]
  PIN b[470]
    DIRECTION OUTPUT ;
    USE SIGNAL ;
    PORT
      LAYER M5 ;
        RECT  103.728 21.528 103.752 21.672 ;
    END
  END b[470]
  PIN b[471]
    DIRECTION OUTPUT ;
    USE SIGNAL ;
    PORT
      LAYER M5 ;
        RECT  103.92 21.528 103.944 21.672 ;
    END
  END b[471]
  PIN b[472]
    DIRECTION OUTPUT ;
    USE SIGNAL ;
    PORT
      LAYER M5 ;
        RECT  104.112 21.528 104.136 21.672 ;
    END
  END b[472]
  PIN b[473]
    DIRECTION OUTPUT ;
    USE SIGNAL ;
    PORT
      LAYER M5 ;
        RECT  104.304 21.528 104.328 21.672 ;
    END
  END b[473]
  PIN b[474]
    DIRECTION OUTPUT ;
    USE SIGNAL ;
    PORT
      LAYER M5 ;
        RECT  104.496 21.528 104.52 21.672 ;
    END
  END b[474]
  PIN b[475]
    DIRECTION OUTPUT ;
    USE SIGNAL ;
    PORT
      LAYER M5 ;
        RECT  104.688 21.528 104.712 21.672 ;
    END
  END b[475]
  PIN b[476]
    DIRECTION OUTPUT ;
    USE SIGNAL ;
    PORT
      LAYER M5 ;
        RECT  104.88 21.528 104.904 21.672 ;
    END
  END b[476]
  PIN b[477]
    DIRECTION OUTPUT ;
    USE SIGNAL ;
    PORT
      LAYER M5 ;
        RECT  105.072 21.528 105.096 21.672 ;
    END
  END b[477]
  PIN b[478]
    DIRECTION OUTPUT ;
    USE SIGNAL ;
    PORT
      LAYER M5 ;
        RECT  105.264 21.528 105.288 21.672 ;
    END
  END b[478]
  PIN b[479]
    DIRECTION OUTPUT ;
    USE SIGNAL ;
    PORT
      LAYER M5 ;
        RECT  105.456 21.528 105.48 21.672 ;
    END
  END b[479]
  PIN b[47]
    DIRECTION OUTPUT ;
    USE SIGNAL ;
    PORT
      LAYER M5 ;
        RECT  22.512 21.528 22.536 21.672 ;
    END
  END b[47]
  PIN b[480]
    DIRECTION OUTPUT ;
    USE SIGNAL ;
    PORT
      LAYER M5 ;
        RECT  105.648 21.528 105.672 21.672 ;
    END
  END b[480]
  PIN b[481]
    DIRECTION OUTPUT ;
    USE SIGNAL ;
    PORT
      LAYER M5 ;
        RECT  105.84 21.528 105.864 21.672 ;
    END
  END b[481]
  PIN b[482]
    DIRECTION OUTPUT ;
    USE SIGNAL ;
    PORT
      LAYER M5 ;
        RECT  106.032 21.528 106.056 21.672 ;
    END
  END b[482]
  PIN b[483]
    DIRECTION OUTPUT ;
    USE SIGNAL ;
    PORT
      LAYER M5 ;
        RECT  106.224 21.528 106.248 21.672 ;
    END
  END b[483]
  PIN b[484]
    DIRECTION OUTPUT ;
    USE SIGNAL ;
    PORT
      LAYER M5 ;
        RECT  106.416 21.528 106.44 21.672 ;
    END
  END b[484]
  PIN b[485]
    DIRECTION OUTPUT ;
    USE SIGNAL ;
    PORT
      LAYER M5 ;
        RECT  106.608 21.528 106.632 21.672 ;
    END
  END b[485]
  PIN b[486]
    DIRECTION OUTPUT ;
    USE SIGNAL ;
    PORT
      LAYER M5 ;
        RECT  106.8 21.528 106.824 21.672 ;
    END
  END b[486]
  PIN b[487]
    DIRECTION OUTPUT ;
    USE SIGNAL ;
    PORT
      LAYER M5 ;
        RECT  106.992 21.528 107.016 21.672 ;
    END
  END b[487]
  PIN b[488]
    DIRECTION OUTPUT ;
    USE SIGNAL ;
    PORT
      LAYER M5 ;
        RECT  107.184 21.528 107.208 21.672 ;
    END
  END b[488]
  PIN b[489]
    DIRECTION OUTPUT ;
    USE SIGNAL ;
    PORT
      LAYER M5 ;
        RECT  107.376 21.528 107.4 21.672 ;
    END
  END b[489]
  PIN b[48]
    DIRECTION OUTPUT ;
    USE SIGNAL ;
    PORT
      LAYER M5 ;
        RECT  22.704 21.528 22.728 21.672 ;
    END
  END b[48]
  PIN b[490]
    DIRECTION OUTPUT ;
    USE SIGNAL ;
    PORT
      LAYER M5 ;
        RECT  107.568 21.528 107.592 21.672 ;
    END
  END b[490]
  PIN b[491]
    DIRECTION OUTPUT ;
    USE SIGNAL ;
    PORT
      LAYER M5 ;
        RECT  107.76 21.528 107.784 21.672 ;
    END
  END b[491]
  PIN b[492]
    DIRECTION OUTPUT ;
    USE SIGNAL ;
    PORT
      LAYER M5 ;
        RECT  107.952 21.528 107.976 21.672 ;
    END
  END b[492]
  PIN b[493]
    DIRECTION OUTPUT ;
    USE SIGNAL ;
    PORT
      LAYER M5 ;
        RECT  108.144 21.528 108.168 21.672 ;
    END
  END b[493]
  PIN b[494]
    DIRECTION OUTPUT ;
    USE SIGNAL ;
    PORT
      LAYER M5 ;
        RECT  108.336 21.528 108.36 21.672 ;
    END
  END b[494]
  PIN b[495]
    DIRECTION OUTPUT ;
    USE SIGNAL ;
    PORT
      LAYER M5 ;
        RECT  108.528 21.528 108.552 21.672 ;
    END
  END b[495]
  PIN b[496]
    DIRECTION OUTPUT ;
    USE SIGNAL ;
    PORT
      LAYER M5 ;
        RECT  108.72 21.528 108.744 21.672 ;
    END
  END b[496]
  PIN b[497]
    DIRECTION OUTPUT ;
    USE SIGNAL ;
    PORT
      LAYER M5 ;
        RECT  108.912 21.528 108.936 21.672 ;
    END
  END b[497]
  PIN b[498]
    DIRECTION OUTPUT ;
    USE SIGNAL ;
    PORT
      LAYER M5 ;
        RECT  109.104 21.528 109.128 21.672 ;
    END
  END b[498]
  PIN b[499]
    DIRECTION OUTPUT ;
    USE SIGNAL ;
    PORT
      LAYER M5 ;
        RECT  109.296 21.528 109.32 21.672 ;
    END
  END b[499]
  PIN b[49]
    DIRECTION OUTPUT ;
    USE SIGNAL ;
    PORT
      LAYER M5 ;
        RECT  22.896 21.528 22.92 21.672 ;
    END
  END b[49]
  PIN b[4]
    DIRECTION OUTPUT ;
    USE SIGNAL ;
    PORT
      LAYER M5 ;
        RECT  14.256 21.528 14.28 21.672 ;
    END
  END b[4]
  PIN b[500]
    DIRECTION OUTPUT ;
    USE SIGNAL ;
    PORT
      LAYER M5 ;
        RECT  109.488 21.528 109.512 21.672 ;
    END
  END b[500]
  PIN b[501]
    DIRECTION OUTPUT ;
    USE SIGNAL ;
    PORT
      LAYER M5 ;
        RECT  109.68 21.528 109.704 21.672 ;
    END
  END b[501]
  PIN b[502]
    DIRECTION OUTPUT ;
    USE SIGNAL ;
    PORT
      LAYER M5 ;
        RECT  109.872 21.528 109.896 21.672 ;
    END
  END b[502]
  PIN b[503]
    DIRECTION OUTPUT ;
    USE SIGNAL ;
    PORT
      LAYER M5 ;
        RECT  110.064 21.528 110.088 21.672 ;
    END
  END b[503]
  PIN b[504]
    DIRECTION OUTPUT ;
    USE SIGNAL ;
    PORT
      LAYER M5 ;
        RECT  110.256 21.528 110.28 21.672 ;
    END
  END b[504]
  PIN b[505]
    DIRECTION OUTPUT ;
    USE SIGNAL ;
    PORT
      LAYER M5 ;
        RECT  110.448 21.528 110.472 21.672 ;
    END
  END b[505]
  PIN b[506]
    DIRECTION OUTPUT ;
    USE SIGNAL ;
    PORT
      LAYER M5 ;
        RECT  110.64 21.528 110.664 21.672 ;
    END
  END b[506]
  PIN b[507]
    DIRECTION OUTPUT ;
    USE SIGNAL ;
    PORT
      LAYER M5 ;
        RECT  110.832 21.528 110.856 21.672 ;
    END
  END b[507]
  PIN b[508]
    DIRECTION OUTPUT ;
    USE SIGNAL ;
    PORT
      LAYER M5 ;
        RECT  111.024 21.528 111.048 21.672 ;
    END
  END b[508]
  PIN b[509]
    DIRECTION OUTPUT ;
    USE SIGNAL ;
    PORT
      LAYER M5 ;
        RECT  111.216 21.528 111.24 21.672 ;
    END
  END b[509]
  PIN b[50]
    DIRECTION OUTPUT ;
    USE SIGNAL ;
    PORT
      LAYER M5 ;
        RECT  23.088 21.528 23.112 21.672 ;
    END
  END b[50]
  PIN b[510]
    DIRECTION OUTPUT ;
    USE SIGNAL ;
    PORT
      LAYER M5 ;
        RECT  111.408 21.528 111.432 21.672 ;
    END
  END b[510]
  PIN b[511]
    DIRECTION OUTPUT ;
    USE SIGNAL ;
    PORT
      LAYER M5 ;
        RECT  111.6 21.528 111.624 21.672 ;
    END
  END b[511]
  PIN b[512]
    DIRECTION OUTPUT ;
    USE SIGNAL ;
    PORT
      LAYER M5 ;
        RECT  111.792 21.528 111.816 21.672 ;
    END
  END b[512]
  PIN b[513]
    DIRECTION OUTPUT ;
    USE SIGNAL ;
    PORT
      LAYER M5 ;
        RECT  111.984 21.528 112.008 21.672 ;
    END
  END b[513]
  PIN b[514]
    DIRECTION OUTPUT ;
    USE SIGNAL ;
    PORT
      LAYER M5 ;
        RECT  112.176 21.528 112.2 21.672 ;
    END
  END b[514]
  PIN b[515]
    DIRECTION OUTPUT ;
    USE SIGNAL ;
    PORT
      LAYER M5 ;
        RECT  112.368 21.528 112.392 21.672 ;
    END
  END b[515]
  PIN b[516]
    DIRECTION OUTPUT ;
    USE SIGNAL ;
    PORT
      LAYER M5 ;
        RECT  112.56 21.528 112.584 21.672 ;
    END
  END b[516]
  PIN b[517]
    DIRECTION OUTPUT ;
    USE SIGNAL ;
    PORT
      LAYER M5 ;
        RECT  112.752 21.528 112.776 21.672 ;
    END
  END b[517]
  PIN b[518]
    DIRECTION OUTPUT ;
    USE SIGNAL ;
    PORT
      LAYER M5 ;
        RECT  112.944 21.528 112.968 21.672 ;
    END
  END b[518]
  PIN b[519]
    DIRECTION OUTPUT ;
    USE SIGNAL ;
    PORT
      LAYER M5 ;
        RECT  113.136 21.528 113.16 21.672 ;
    END
  END b[519]
  PIN b[51]
    DIRECTION OUTPUT ;
    USE SIGNAL ;
    PORT
      LAYER M5 ;
        RECT  23.28 21.528 23.304 21.672 ;
    END
  END b[51]
  PIN b[520]
    DIRECTION OUTPUT ;
    USE SIGNAL ;
    PORT
      LAYER M5 ;
        RECT  113.328 21.528 113.352 21.672 ;
    END
  END b[520]
  PIN b[521]
    DIRECTION OUTPUT ;
    USE SIGNAL ;
    PORT
      LAYER M5 ;
        RECT  113.52 21.528 113.544 21.672 ;
    END
  END b[521]
  PIN b[522]
    DIRECTION OUTPUT ;
    USE SIGNAL ;
    PORT
      LAYER M5 ;
        RECT  113.712 21.528 113.736 21.672 ;
    END
  END b[522]
  PIN b[523]
    DIRECTION OUTPUT ;
    USE SIGNAL ;
    PORT
      LAYER M5 ;
        RECT  113.904 21.528 113.928 21.672 ;
    END
  END b[523]
  PIN b[524]
    DIRECTION OUTPUT ;
    USE SIGNAL ;
    PORT
      LAYER M5 ;
        RECT  114.096 21.528 114.12 21.672 ;
    END
  END b[524]
  PIN b[525]
    DIRECTION OUTPUT ;
    USE SIGNAL ;
    PORT
      LAYER M5 ;
        RECT  114.288 21.528 114.312 21.672 ;
    END
  END b[525]
  PIN b[526]
    DIRECTION OUTPUT ;
    USE SIGNAL ;
    PORT
      LAYER M5 ;
        RECT  114.48 21.528 114.504 21.672 ;
    END
  END b[526]
  PIN b[527]
    DIRECTION OUTPUT ;
    USE SIGNAL ;
    PORT
      LAYER M5 ;
        RECT  114.672 21.528 114.696 21.672 ;
    END
  END b[527]
  PIN b[528]
    DIRECTION OUTPUT ;
    USE SIGNAL ;
    PORT
      LAYER M5 ;
        RECT  114.864 21.528 114.888 21.672 ;
    END
  END b[528]
  PIN b[529]
    DIRECTION OUTPUT ;
    USE SIGNAL ;
    PORT
      LAYER M5 ;
        RECT  115.056 21.528 115.08 21.672 ;
    END
  END b[529]
  PIN b[52]
    DIRECTION OUTPUT ;
    USE SIGNAL ;
    PORT
      LAYER M5 ;
        RECT  23.472 21.528 23.496 21.672 ;
    END
  END b[52]
  PIN b[530]
    DIRECTION OUTPUT ;
    USE SIGNAL ;
    PORT
      LAYER M5 ;
        RECT  115.248 21.528 115.272 21.672 ;
    END
  END b[530]
  PIN b[531]
    DIRECTION OUTPUT ;
    USE SIGNAL ;
    PORT
      LAYER M5 ;
        RECT  115.44 21.528 115.464 21.672 ;
    END
  END b[531]
  PIN b[532]
    DIRECTION OUTPUT ;
    USE SIGNAL ;
    PORT
      LAYER M5 ;
        RECT  115.632 21.528 115.656 21.672 ;
    END
  END b[532]
  PIN b[533]
    DIRECTION OUTPUT ;
    USE SIGNAL ;
    PORT
      LAYER M5 ;
        RECT  115.824 21.528 115.848 21.672 ;
    END
  END b[533]
  PIN b[534]
    DIRECTION OUTPUT ;
    USE SIGNAL ;
    PORT
      LAYER M5 ;
        RECT  116.016 21.528 116.04 21.672 ;
    END
  END b[534]
  PIN b[53]
    DIRECTION OUTPUT ;
    USE SIGNAL ;
    PORT
      LAYER M5 ;
        RECT  23.664 21.528 23.688 21.672 ;
    END
  END b[53]
  PIN b[54]
    DIRECTION OUTPUT ;
    USE SIGNAL ;
    PORT
      LAYER M5 ;
        RECT  23.856 21.528 23.88 21.672 ;
    END
  END b[54]
  PIN b[55]
    DIRECTION OUTPUT ;
    USE SIGNAL ;
    PORT
      LAYER M5 ;
        RECT  24.048 21.528 24.072 21.672 ;
    END
  END b[55]
  PIN b[56]
    DIRECTION OUTPUT ;
    USE SIGNAL ;
    PORT
      LAYER M5 ;
        RECT  24.24 21.528 24.264 21.672 ;
    END
  END b[56]
  PIN b[57]
    DIRECTION OUTPUT ;
    USE SIGNAL ;
    PORT
      LAYER M5 ;
        RECT  24.432 21.528 24.456 21.672 ;
    END
  END b[57]
  PIN b[58]
    DIRECTION OUTPUT ;
    USE SIGNAL ;
    PORT
      LAYER M5 ;
        RECT  24.624 21.528 24.648 21.672 ;
    END
  END b[58]
  PIN b[59]
    DIRECTION OUTPUT ;
    USE SIGNAL ;
    PORT
      LAYER M5 ;
        RECT  24.816 21.528 24.84 21.672 ;
    END
  END b[59]
  PIN b[5]
    DIRECTION OUTPUT ;
    USE SIGNAL ;
    PORT
      LAYER M5 ;
        RECT  14.448 21.528 14.472 21.672 ;
    END
  END b[5]
  PIN b[60]
    DIRECTION OUTPUT ;
    USE SIGNAL ;
    PORT
      LAYER M5 ;
        RECT  25.008 21.528 25.032 21.672 ;
    END
  END b[60]
  PIN b[61]
    DIRECTION OUTPUT ;
    USE SIGNAL ;
    PORT
      LAYER M5 ;
        RECT  25.2 21.528 25.224 21.672 ;
    END
  END b[61]
  PIN b[62]
    DIRECTION OUTPUT ;
    USE SIGNAL ;
    PORT
      LAYER M5 ;
        RECT  25.392 21.528 25.416 21.672 ;
    END
  END b[62]
  PIN b[63]
    DIRECTION OUTPUT ;
    USE SIGNAL ;
    PORT
      LAYER M5 ;
        RECT  25.584 21.528 25.608 21.672 ;
    END
  END b[63]
  PIN b[64]
    DIRECTION OUTPUT ;
    USE SIGNAL ;
    PORT
      LAYER M5 ;
        RECT  25.776 21.528 25.8 21.672 ;
    END
  END b[64]
  PIN b[65]
    DIRECTION OUTPUT ;
    USE SIGNAL ;
    PORT
      LAYER M5 ;
        RECT  25.968 21.528 25.992 21.672 ;
    END
  END b[65]
  PIN b[66]
    DIRECTION OUTPUT ;
    USE SIGNAL ;
    PORT
      LAYER M5 ;
        RECT  26.16 21.528 26.184 21.672 ;
    END
  END b[66]
  PIN b[67]
    DIRECTION OUTPUT ;
    USE SIGNAL ;
    PORT
      LAYER M5 ;
        RECT  26.352 21.528 26.376 21.672 ;
    END
  END b[67]
  PIN b[68]
    DIRECTION OUTPUT ;
    USE SIGNAL ;
    PORT
      LAYER M5 ;
        RECT  26.544 21.528 26.568 21.672 ;
    END
  END b[68]
  PIN b[69]
    DIRECTION OUTPUT ;
    USE SIGNAL ;
    PORT
      LAYER M5 ;
        RECT  26.736 21.528 26.76 21.672 ;
    END
  END b[69]
  PIN b[6]
    DIRECTION OUTPUT ;
    USE SIGNAL ;
    PORT
      LAYER M5 ;
        RECT  14.64 21.528 14.664 21.672 ;
    END
  END b[6]
  PIN b[70]
    DIRECTION OUTPUT ;
    USE SIGNAL ;
    PORT
      LAYER M5 ;
        RECT  26.928 21.528 26.952 21.672 ;
    END
  END b[70]
  PIN b[71]
    DIRECTION OUTPUT ;
    USE SIGNAL ;
    PORT
      LAYER M5 ;
        RECT  27.12 21.528 27.144 21.672 ;
    END
  END b[71]
  PIN b[72]
    DIRECTION OUTPUT ;
    USE SIGNAL ;
    PORT
      LAYER M5 ;
        RECT  27.312 21.528 27.336 21.672 ;
    END
  END b[72]
  PIN b[73]
    DIRECTION OUTPUT ;
    USE SIGNAL ;
    PORT
      LAYER M5 ;
        RECT  27.504 21.528 27.528 21.672 ;
    END
  END b[73]
  PIN b[74]
    DIRECTION OUTPUT ;
    USE SIGNAL ;
    PORT
      LAYER M5 ;
        RECT  27.696 21.528 27.72 21.672 ;
    END
  END b[74]
  PIN b[75]
    DIRECTION OUTPUT ;
    USE SIGNAL ;
    PORT
      LAYER M5 ;
        RECT  27.888 21.528 27.912 21.672 ;
    END
  END b[75]
  PIN b[76]
    DIRECTION OUTPUT ;
    USE SIGNAL ;
    PORT
      LAYER M5 ;
        RECT  28.08 21.528 28.104 21.672 ;
    END
  END b[76]
  PIN b[77]
    DIRECTION OUTPUT ;
    USE SIGNAL ;
    PORT
      LAYER M5 ;
        RECT  28.272 21.528 28.296 21.672 ;
    END
  END b[77]
  PIN b[78]
    DIRECTION OUTPUT ;
    USE SIGNAL ;
    PORT
      LAYER M5 ;
        RECT  28.464 21.528 28.488 21.672 ;
    END
  END b[78]
  PIN b[79]
    DIRECTION OUTPUT ;
    USE SIGNAL ;
    PORT
      LAYER M5 ;
        RECT  28.656 21.528 28.68 21.672 ;
    END
  END b[79]
  PIN b[7]
    DIRECTION OUTPUT ;
    USE SIGNAL ;
    PORT
      LAYER M5 ;
        RECT  14.832 21.528 14.856 21.672 ;
    END
  END b[7]
  PIN b[80]
    DIRECTION OUTPUT ;
    USE SIGNAL ;
    PORT
      LAYER M5 ;
        RECT  28.848 21.528 28.872 21.672 ;
    END
  END b[80]
  PIN b[81]
    DIRECTION OUTPUT ;
    USE SIGNAL ;
    PORT
      LAYER M5 ;
        RECT  29.04 21.528 29.064 21.672 ;
    END
  END b[81]
  PIN b[82]
    DIRECTION OUTPUT ;
    USE SIGNAL ;
    PORT
      LAYER M5 ;
        RECT  29.232 21.528 29.256 21.672 ;
    END
  END b[82]
  PIN b[83]
    DIRECTION OUTPUT ;
    USE SIGNAL ;
    PORT
      LAYER M5 ;
        RECT  29.424 21.528 29.448 21.672 ;
    END
  END b[83]
  PIN b[84]
    DIRECTION OUTPUT ;
    USE SIGNAL ;
    PORT
      LAYER M5 ;
        RECT  29.616 21.528 29.64 21.672 ;
    END
  END b[84]
  PIN b[85]
    DIRECTION OUTPUT ;
    USE SIGNAL ;
    PORT
      LAYER M5 ;
        RECT  29.808 21.528 29.832 21.672 ;
    END
  END b[85]
  PIN b[86]
    DIRECTION OUTPUT ;
    USE SIGNAL ;
    PORT
      LAYER M5 ;
        RECT  30 21.528 30.024 21.672 ;
    END
  END b[86]
  PIN b[87]
    DIRECTION OUTPUT ;
    USE SIGNAL ;
    PORT
      LAYER M5 ;
        RECT  30.192 21.528 30.216 21.672 ;
    END
  END b[87]
  PIN b[88]
    DIRECTION OUTPUT ;
    USE SIGNAL ;
    PORT
      LAYER M5 ;
        RECT  30.384 21.528 30.408 21.672 ;
    END
  END b[88]
  PIN b[89]
    DIRECTION OUTPUT ;
    USE SIGNAL ;
    PORT
      LAYER M5 ;
        RECT  30.576 21.528 30.6 21.672 ;
    END
  END b[89]
  PIN b[8]
    DIRECTION OUTPUT ;
    USE SIGNAL ;
    PORT
      LAYER M5 ;
        RECT  15.024 21.528 15.048 21.672 ;
    END
  END b[8]
  PIN b[90]
    DIRECTION OUTPUT ;
    USE SIGNAL ;
    PORT
      LAYER M5 ;
        RECT  30.768 21.528 30.792 21.672 ;
    END
  END b[90]
  PIN b[91]
    DIRECTION OUTPUT ;
    USE SIGNAL ;
    PORT
      LAYER M5 ;
        RECT  30.96 21.528 30.984 21.672 ;
    END
  END b[91]
  PIN b[92]
    DIRECTION OUTPUT ;
    USE SIGNAL ;
    PORT
      LAYER M5 ;
        RECT  31.152 21.528 31.176 21.672 ;
    END
  END b[92]
  PIN b[93]
    DIRECTION OUTPUT ;
    USE SIGNAL ;
    PORT
      LAYER M5 ;
        RECT  31.344 21.528 31.368 21.672 ;
    END
  END b[93]
  PIN b[94]
    DIRECTION OUTPUT ;
    USE SIGNAL ;
    PORT
      LAYER M5 ;
        RECT  31.536 21.528 31.56 21.672 ;
    END
  END b[94]
  PIN b[95]
    DIRECTION OUTPUT ;
    USE SIGNAL ;
    PORT
      LAYER M5 ;
        RECT  31.728 21.528 31.752 21.672 ;
    END
  END b[95]
  PIN b[96]
    DIRECTION OUTPUT ;
    USE SIGNAL ;
    PORT
      LAYER M5 ;
        RECT  31.92 21.528 31.944 21.672 ;
    END
  END b[96]
  PIN b[97]
    DIRECTION OUTPUT ;
    USE SIGNAL ;
    PORT
      LAYER M5 ;
        RECT  32.112 21.528 32.136 21.672 ;
    END
  END b[97]
  PIN b[98]
    DIRECTION OUTPUT ;
    USE SIGNAL ;
    PORT
      LAYER M5 ;
        RECT  32.304 21.528 32.328 21.672 ;
    END
  END b[98]
  PIN b[99]
    DIRECTION OUTPUT ;
    USE SIGNAL ;
    PORT
      LAYER M5 ;
        RECT  32.496 21.528 32.52 21.672 ;
    END
  END b[99]
  PIN b[9]
    DIRECTION OUTPUT ;
    USE SIGNAL ;
    PORT
      LAYER M5 ;
        RECT  15.216 21.528 15.24 21.672 ;
    END
  END b[9]
  PIN ck
    DIRECTION INPUT ;
    USE SIGNAL ;
    PORT
      LAYER M4 ;
        RECT  -0.072 10.8 0.072 10.824 ;
    END
    PORT
      LAYER M4 ;
        RECT  0.06 10.8 0.227 10.824 ;
    END
  END ck
  PIN VDD
    DIRECTION INOUT ;
    USE POWER ;
    PORT
      LAYER M5 ;
        RECT  126.792 2.151 126.912 19.449 ;
        RECT  124.092 2.151 124.212 19.449 ;
        RECT  121.392 2.151 121.512 19.449 ;
        RECT  118.692 2.151 118.812 19.449 ;
        RECT  115.992 2.151 116.112 19.449 ;
        RECT  113.292 2.151 113.412 19.449 ;
        RECT  110.592 2.151 110.712 19.449 ;
        RECT  107.892 2.151 108.012 19.449 ;
        RECT  105.192 2.151 105.312 19.449 ;
        RECT  102.492 2.151 102.612 19.449 ;
        RECT  99.792 2.151 99.912 19.449 ;
        RECT  97.092 2.151 97.212 19.449 ;
        RECT  94.392 2.151 94.512 19.449 ;
        RECT  91.692 2.151 91.812 19.449 ;
        RECT  88.992 2.151 89.112 19.449 ;
        RECT  86.292 2.151 86.412 19.449 ;
        RECT  83.592 2.151 83.712 19.449 ;
        RECT  80.892 2.151 81.012 19.449 ;
        RECT  78.192 2.151 78.312 19.449 ;
        RECT  75.492 2.151 75.612 19.449 ;
        RECT  72.792 2.151 72.912 19.449 ;
        RECT  70.092 2.151 70.212 19.449 ;
        RECT  67.392 2.151 67.512 19.449 ;
        RECT  64.692 2.151 64.812 19.449 ;
        RECT  61.992 2.151 62.112 19.449 ;
        RECT  59.292 2.151 59.412 19.449 ;
        RECT  56.592 2.151 56.712 19.449 ;
        RECT  53.892 2.151 54.012 19.449 ;
        RECT  51.192 2.151 51.312 19.449 ;
        RECT  48.492 2.151 48.612 19.449 ;
        RECT  45.792 2.151 45.912 19.449 ;
        RECT  43.092 2.151 43.212 19.449 ;
        RECT  40.392 2.151 40.512 19.449 ;
        RECT  37.692 2.151 37.812 19.449 ;
        RECT  34.992 2.151 35.112 19.449 ;
        RECT  32.292 2.151 32.412 19.449 ;
        RECT  29.592 2.151 29.712 19.449 ;
        RECT  26.892 2.151 27.012 19.449 ;
        RECT  24.192 2.151 24.312 19.449 ;
        RECT  21.492 2.151 21.612 19.449 ;
        RECT  18.792 2.151 18.912 19.449 ;
        RECT  16.092 2.151 16.212 19.449 ;
        RECT  13.392 2.151 13.512 19.449 ;
        RECT  10.692 2.151 10.812 19.449 ;
        RECT  7.992 2.151 8.112 19.449 ;
        RECT  5.292 2.151 5.412 19.449 ;
        RECT  2.592 2.151 2.712 19.449 ;
    END
  END VDD
  PIN VSS
    DIRECTION INOUT ;
    USE GROUND ;
    PORT
      LAYER M5 ;
        RECT  126.6 2.137 126.72 19.463 ;
        RECT  123.9 2.137 124.02 19.463 ;
        RECT  121.2 2.137 121.32 19.463 ;
        RECT  118.5 2.137 118.62 19.463 ;
        RECT  115.8 2.137 115.92 19.463 ;
        RECT  113.1 2.137 113.22 19.463 ;
        RECT  110.4 2.137 110.52 19.463 ;
        RECT  107.7 2.137 107.82 19.463 ;
        RECT  105 2.137 105.12 19.463 ;
        RECT  102.3 2.137 102.42 19.463 ;
        RECT  99.6 2.137 99.72 19.463 ;
        RECT  96.9 2.137 97.02 19.463 ;
        RECT  94.2 2.137 94.32 19.463 ;
        RECT  91.5 2.137 91.62 19.463 ;
        RECT  88.8 2.137 88.92 19.463 ;
        RECT  86.1 2.137 86.22 19.463 ;
        RECT  83.4 2.137 83.52 19.463 ;
        RECT  80.7 2.137 80.82 19.463 ;
        RECT  78 2.137 78.12 19.463 ;
        RECT  75.3 2.137 75.42 19.463 ;
        RECT  72.6 2.137 72.72 19.463 ;
        RECT  69.9 2.137 70.02 19.463 ;
        RECT  67.2 2.137 67.32 19.463 ;
        RECT  64.5 2.137 64.62 19.463 ;
        RECT  61.8 2.137 61.92 19.463 ;
        RECT  59.1 2.137 59.22 19.463 ;
        RECT  56.4 2.137 56.52 19.463 ;
        RECT  53.7 2.137 53.82 19.463 ;
        RECT  51 2.137 51.12 19.463 ;
        RECT  48.3 2.137 48.42 19.463 ;
        RECT  45.6 2.137 45.72 19.463 ;
        RECT  42.9 2.137 43.02 19.463 ;
        RECT  40.2 2.137 40.32 19.463 ;
        RECT  37.5 2.137 37.62 19.463 ;
        RECT  34.8 2.137 34.92 19.463 ;
        RECT  32.1 2.137 32.22 19.463 ;
        RECT  29.4 2.137 29.52 19.463 ;
        RECT  26.7 2.137 26.82 19.463 ;
        RECT  24 2.137 24.12 19.463 ;
        RECT  21.3 2.137 21.42 19.463 ;
        RECT  18.6 2.137 18.72 19.463 ;
        RECT  15.9 2.137 16.02 19.463 ;
        RECT  13.2 2.137 13.32 19.463 ;
        RECT  10.5 2.137 10.62 19.463 ;
        RECT  7.8 2.137 7.92 19.463 ;
        RECT  5.1 2.137 5.22 19.463 ;
        RECT  2.4 2.137 2.52 19.463 ;
    END
  END VSS
  # OT_OBS_CLOSED layer=M5 d_um=1.536 added=194
  OBS
    LAYER RVTN ;
     RECT  2.16 2.16 127.44 2.295 ;
     RECT  2.16 2.565 127.44 2.835 ;
     RECT  2.16 3.105 127.44 3.375 ;
     RECT  2.16 3.645 127.44 3.915 ;
     RECT  2.16 4.185 127.44 4.455 ;
     RECT  2.16 4.725 127.44 4.995 ;
     RECT  2.16 5.265 127.44 5.535 ;
     RECT  2.16 5.805 127.44 6.075 ;
     RECT  2.16 6.345 127.44 6.615 ;
     RECT  2.16 6.885 127.44 7.155 ;
     RECT  2.16 7.425 127.44 7.695 ;
     RECT  2.16 7.965 127.44 8.235 ;
     RECT  2.16 8.505 127.44 8.775 ;
     RECT  2.16 9.045 127.44 9.315 ;
     RECT  2.16 9.585 127.44 9.855 ;
     RECT  2.16 10.125 127.44 10.395 ;
     RECT  2.16 10.665 127.44 10.935 ;
     RECT  2.16 11.205 127.44 11.475 ;
     RECT  2.16 11.745 127.44 12.015 ;
     RECT  2.16 12.285 127.44 12.555 ;
     RECT  2.16 12.825 127.44 13.095 ;
     RECT  2.16 13.365 127.44 13.635 ;
     RECT  2.16 13.905 127.44 14.175 ;
     RECT  2.16 14.445 127.44 14.715 ;
     RECT  2.16 14.985 127.44 15.255 ;
     RECT  2.16 15.525 127.44 15.795 ;
     RECT  2.16 16.065 127.44 16.335 ;
     RECT  2.16 16.605 127.44 16.875 ;
     RECT  2.16 17.145 127.44 17.415 ;
     RECT  2.16 17.685 127.44 17.955 ;
     RECT  2.16 18.225 127.44 18.495 ;
     RECT  2.16 18.765 127.44 19.035 ;
     RECT  2.16 19.305 127.44 19.44 ;
    LAYER RVTP ;
     RECT  2.16 2.295 127.44 2.565 ;
     RECT  2.16 2.835 127.44 3.105 ;
     RECT  2.16 3.375 127.44 3.645 ;
     RECT  2.16 3.915 127.44 4.185 ;
     RECT  2.16 4.455 127.44 4.725 ;
     RECT  2.16 4.995 127.44 5.265 ;
     RECT  2.16 5.535 127.44 5.805 ;
     RECT  2.16 6.075 127.44 6.345 ;
     RECT  2.16 6.615 127.44 6.885 ;
     RECT  2.16 7.155 127.44 7.425 ;
     RECT  2.16 7.695 127.44 7.965 ;
     RECT  2.16 8.235 127.44 8.505 ;
     RECT  2.16 8.775 127.44 9.045 ;
     RECT  2.16 9.315 127.44 9.585 ;
     RECT  2.16 9.855 127.44 10.125 ;
     RECT  2.16 10.395 127.44 10.665 ;
     RECT  2.16 10.935 127.44 11.205 ;
     RECT  2.16 11.475 127.44 11.745 ;
     RECT  2.16 12.015 127.44 12.285 ;
     RECT  2.16 12.555 127.44 12.825 ;
     RECT  2.16 13.095 127.44 13.365 ;
     RECT  2.16 13.635 127.44 13.905 ;
     RECT  2.16 14.175 127.44 14.445 ;
     RECT  2.16 14.715 127.44 14.985 ;
     RECT  2.16 15.255 127.44 15.525 ;
     RECT  2.16 15.795 127.44 16.065 ;
     RECT  2.16 16.335 127.44 16.605 ;
     RECT  2.16 16.875 127.44 17.145 ;
     RECT  2.16 17.415 127.44 17.685 ;
     RECT  2.16 17.955 127.44 18.225 ;
     RECT  2.16 18.495 127.44 18.765 ;
     RECT  2.16 19.035 127.44 19.305 ;
    LAYER M1 ;
     RECT  2.16 2.151 127.44 19.449 ;
    LAYER M2 ;
     RECT  2.16 2.151 83.227 19.449 ;
     RECT  83.227 2.106 83.759 19.449 ;
     RECT  83.759 2.151 127.44 19.449 ;
    LAYER M3 ;
     RECT  26.928 1.723 27.306 2.011 ;
     RECT  31.392 1.723 34.794 2.011 ;
     RECT  39.996 1.723 40.014 2.011 ;
     RECT  40.896 1.723 42.102 2.011 ;
     RECT  43.596 1.723 45.954 2.011 ;
     RECT  51.48 1.723 52.218 2.011 ;
     RECT  56.844 1.723 56.862 2.011 ;
     RECT  60.336 1.723 61.326 2.011 ;
     RECT  62.568 1.723 62.586 2.011 ;
     RECT  63.36 1.723 64.494 2.011 ;
     RECT  67.356 1.723 70.506 2.011 ;
     RECT  71.424 1.723 72.306 2.011 ;
     RECT  74.7 1.723 74.718 2.011 ;
     RECT  75.996 1.723 80.19 2.011 ;
     RECT  81.144 1.723 84.006 2.011 ;
     RECT  84.96 1.723 85.518 2.011 ;
     RECT  86.652 1.723 88.182 2.011 ;
     RECT  88.956 1.723 89.73 2.011 ;
     RECT  90.54 1.723 91.242 2.011 ;
     RECT  91.98 1.723 92.61 2.011 ;
     RECT  99.432 1.723 99.45 2.011 ;
     RECT  100.368 1.723 100.638 2.011 ;
     RECT  110.124 1.723 110.142 2.011 ;
     RECT  110.952 1.723 110.97 2.011 ;
     RECT  114.66 1.723 115.29 2.011 ;
     RECT  29.304 1.723 29.574 2.059 ;
     RECT  13.356 2.011 13.374 2.143 ;
     RECT  16.164 1.723 16.182 2.143 ;
     RECT  17.316 1.723 17.91 2.143 ;
     RECT  18.864 1.723 18.882 2.143 ;
     RECT  26.856 2.011 27.306 2.143 ;
     RECT  49.608 1.723 50.382 2.143 ;
     RECT  51.336 2.011 52.218 2.143 ;
     RECT  55.368 1.723 55.782 2.143 ;
     RECT  56.556 2.011 56.862 2.143 ;
     RECT  58.5 1.723 58.518 2.143 ;
     RECT  59.436 2.011 59.454 2.143 ;
     RECT  101.592 1.723 101.61 2.143 ;
     RECT  113.256 1.723 113.274 2.143 ;
     RECT  15.915 2.143 16.182 2.191 ;
     RECT  17.316 2.143 18.882 2.191 ;
     RECT  19.908 1.723 20.466 2.191 ;
     RECT  21.276 1.723 22.734 2.191 ;
     RECT  23.976 1.723 25.434 2.191 ;
     RECT  26.715 2.143 27.306 2.191 ;
     RECT  39.24 1.723 39.258 2.191 ;
     RECT  39.996 2.011 42.102 2.191 ;
     RECT  42.84 2.011 45.954 2.191 ;
     RECT  46.908 1.723 46.926 2.191 ;
     RECT  47.808 1.723 48.798 2.191 ;
     RECT  49.608 2.143 52.218 2.191 ;
     RECT  55.368 2.143 56.862 2.191 ;
     RECT  57.636 1.723 57.654 2.191 ;
     RECT  58.5 2.143 59.454 2.191 ;
     RECT  60.336 2.011 62.586 2.191 ;
     RECT  63.36 2.011 64.854 2.191 ;
     RECT  73.62 1.723 73.638 2.191 ;
     RECT  84.96 2.011 89.73 2.191 ;
     RECT  90.54 2.011 92.61 2.191 ;
     RECT  98.316 1.723 98.334 2.191 ;
     RECT  99.432 2.011 100.638 2.191 ;
     RECT  103.32 1.723 103.95 2.191 ;
     RECT  104.724 1.723 108.306 2.191 ;
     RECT  110.124 2.011 110.97 2.191 ;
     RECT  26.715 2.191 27.45 2.237 ;
     RECT  65.7 1.723 66.294 2.251 ;
     RECT  67.176 2.011 70.506 2.251 ;
     RECT  71.424 2.011 72.774 2.251 ;
     RECT  74.7 2.011 84.006 2.251 ;
     RECT  93.78 1.723 95.346 2.251 ;
     RECT  112.068 1.723 112.086 2.251 ;
     RECT  113.115 2.143 113.274 2.251 ;
     RECT  26.715 2.237 27.306 2.255 ;
     RECT  55.368 2.191 59.454 2.255 ;
     RECT  28.26 1.723 28.278 2.263 ;
     RECT  53.208 1.723 54.198 2.263 ;
     RECT  96.804 1.723 97.182 2.263 ;
     RECT  19.908 2.191 22.842 2.285 ;
     RECT  13.215 2.143 13.374 2.299 ;
     RECT  15.915 2.191 16.398 2.299 ;
     RECT  17.316 2.191 19.026 2.299 ;
     RECT  19.908 2.285 22.122 2.299 ;
     RECT  23.976 2.191 25.542 2.299 ;
     RECT  26.715 2.255 27.27 2.299 ;
     RECT  28.26 2.263 28.494 2.299 ;
     RECT  29.304 2.059 29.718 2.299 ;
     RECT  31.392 2.011 34.974 2.299 ;
     RECT  35.928 1.723 38.286 2.299 ;
     RECT  39.24 2.191 46.062 2.299 ;
     RECT  46.908 2.191 47.07 2.299 ;
     RECT  47.808 2.191 52.398 2.299 ;
     RECT  53.208 2.263 54.27 2.299 ;
     RECT  55.368 2.255 57.006 2.299 ;
     RECT  57.924 2.255 59.454 2.299 ;
     RECT  60.336 2.191 64.854 2.299 ;
     RECT  65.7 2.251 72.774 2.299 ;
     RECT  73.62 2.191 73.854 2.299 ;
     RECT  74.7 2.251 84.222 2.299 ;
     RECT  84.96 2.191 92.718 2.299 ;
     RECT  93.78 2.251 95.562 2.299 ;
     RECT  96.804 2.263 97.254 2.299 ;
     RECT  98.316 2.191 98.442 2.299 ;
     RECT  99.432 2.191 100.818 2.299 ;
     RECT  101.592 2.143 102.405 2.299 ;
     RECT  103.32 2.191 108.45 2.299 ;
     RECT  109.26 1.723 109.278 2.299 ;
     RECT  110.124 2.191 111.078 2.299 ;
     RECT  112.068 2.251 112.302 2.299 ;
     RECT  113.115 2.251 113.49 2.299 ;
     RECT  114.66 2.011 115.974 2.299 ;
     RECT  2.415 2.143 2.505 2.413 ;
     RECT  5.115 2.143 5.205 2.413 ;
     RECT  7.815 2.143 7.905 2.413 ;
     RECT  10.515 2.143 10.605 2.413 ;
     RECT  99.18 2.299 115.974 2.413 ;
     RECT  118.515 2.143 118.605 2.413 ;
     RECT  121.215 2.143 121.305 2.413 ;
     RECT  123.915 2.143 124.005 2.413 ;
     RECT  126.615 2.143 126.705 2.413 ;
     RECT  39.24 2.299 57.006 2.525 ;
     RECT  57.924 2.299 98.442 2.525 ;
     RECT  28.26 2.299 38.43 2.641 ;
     RECT  39.24 2.525 46.818 2.641 ;
     RECT  99.18 2.413 116.097 2.641 ;
     RECT  13.215 2.299 22.122 2.717 ;
     RECT  28.26 2.641 46.818 2.717 ;
     RECT  47.7 2.525 57.006 2.717 ;
     RECT  58.068 2.525 98.442 2.717 ;
     RECT  99.18 2.641 116.226 2.717 ;
     RECT  50.184 2.717 57.006 2.765 ;
     RECT  58.068 2.717 72.954 2.765 ;
     RECT  73.8 2.717 98.442 2.765 ;
     RECT  73.8 2.765 90.738 2.768 ;
     RECT  13.215 2.717 19.314 2.795 ;
     RECT  20.16 2.717 22.122 2.795 ;
     RECT  33.192 2.717 46.818 2.795 ;
     RECT  47.7 2.717 49.086 2.795 ;
     RECT  50.184 2.765 52.65 2.795 ;
     RECT  53.424 2.765 57.006 2.795 ;
     RECT  58.068 2.765 65.646 2.795 ;
     RECT  66.456 2.765 72.954 2.795 ;
     RECT  73.8 2.768 90.594 2.795 ;
     RECT  20.268 2.795 22.122 2.813 ;
     RECT  42.876 2.795 46.818 2.813 ;
     RECT  68.22 2.795 69.138 2.813 ;
     RECT  69.876 2.795 72.954 2.813 ;
     RECT  73.8 2.795 75.798 2.813 ;
     RECT  102.276 2.717 116.097 2.813 ;
     RECT  13.215 2.795 16.866 2.861 ;
     RECT  17.64 2.795 19.314 2.861 ;
     RECT  20.376 2.813 22.122 2.861 ;
     RECT  22.86 2.299 27.27 2.861 ;
     RECT  28.26 2.717 32.397 2.861 ;
     RECT  33.3 2.795 38.862 2.861 ;
     RECT  39.6 2.795 42.066 2.861 ;
     RECT  42.915 2.813 46.818 2.861 ;
     RECT  47.736 2.795 49.086 2.861 ;
     RECT  50.4 2.795 52.65 2.861 ;
     RECT  53.604 2.795 54.27 2.861 ;
     RECT  55.116 2.795 57.006 2.861 ;
     RECT  58.104 2.795 65.502 2.861 ;
     RECT  69.915 2.813 72.897 2.861 ;
     RECT  74.16 2.813 75.798 2.861 ;
     RECT  76.716 2.795 90.45 2.861 ;
     RECT  91.515 2.765 98.442 2.861 ;
     RECT  99.18 2.717 101.394 2.861 ;
     RECT  102.315 2.813 113.85 2.861 ;
     RECT  114.624 2.813 116.097 2.861 ;
     RECT  28.26 2.861 30.51 2.875 ;
     RECT  99.18 2.861 100.35 2.875 ;
     RECT  88.812 2.861 90.45 2.939 ;
     RECT  53.715 2.861 54.27 3.005 ;
     RECT  61.632 2.861 62.097 3.005 ;
     RECT  14.22 2.861 14.85 3.065 ;
     RECT  15.624 2.861 16.866 3.065 ;
     RECT  18.288 2.861 18.897 3.065 ;
     RECT  20.556 2.861 22.122 3.065 ;
     RECT  22.86 2.861 24.786 3.065 ;
     RECT  28.044 2.875 30.51 3.065 ;
     RECT  33.444 2.861 35.298 3.065 ;
     RECT  36.684 2.861 38.862 3.065 ;
     RECT  42.915 2.861 44.334 3.065 ;
     RECT  45.615 2.861 46.674 3.065 ;
     RECT  50.4 2.861 52.326 3.065 ;
     RECT  58.392 2.861 59.397 3.065 ;
     RECT  61.74 3.005 62.097 3.065 ;
     RECT  68.292 2.813 69.138 3.065 ;
     RECT  74.592 2.861 75.597 3.065 ;
     RECT  77.616 2.861 79.866 3.065 ;
     RECT  82.26 2.861 82.422 3.065 ;
     RECT  85.356 2.861 87.606 3.065 ;
     RECT  91.515 2.861 92.61 3.065 ;
     RECT  93.348 2.861 94.842 3.065 ;
     RECT  98.748 2.875 100.35 3.065 ;
     RECT  106.2 2.861 106.326 3.065 ;
     RECT  107.208 2.861 108.162 3.065 ;
     RECT  109.332 2.861 109.458 3.065 ;
     RECT  114.84 2.861 116.097 3.065 ;
     RECT  20.664 3.065 22.122 3.181 ;
     RECT  56.415 2.861 57.006 3.181 ;
     RECT  14.364 3.065 14.85 3.245 ;
     RECT  15.768 3.065 16.866 3.245 ;
     RECT  18.396 3.065 18.897 3.245 ;
     RECT  20.664 3.181 22.266 3.245 ;
     RECT  23.004 3.065 24.786 3.245 ;
     RECT  25.848 2.861 26.997 3.245 ;
     RECT  28.188 3.065 28.206 3.245 ;
     RECT  28.98 3.065 30.51 3.245 ;
     RECT  33.624 3.065 35.298 3.245 ;
     RECT  36.828 3.065 38.862 3.245 ;
     RECT  42.915 3.065 43.578 3.245 ;
     RECT  44.316 3.065 44.334 3.245 ;
     RECT  46.656 3.065 46.674 3.245 ;
     RECT  50.544 3.065 52.326 3.245 ;
     RECT  56.415 3.181 57.15 3.245 ;
     RECT  58.536 3.065 59.397 3.245 ;
     RECT  63.576 2.861 65.358 3.245 ;
     RECT  68.4 3.065 69.138 3.245 ;
     RECT  69.915 2.861 71.406 3.245 ;
     RECT  72.396 2.861 72.897 3.245 ;
     RECT  74.736 3.065 75.597 3.245 ;
     RECT  77.76 3.065 78.297 3.245 ;
     RECT  79.092 3.065 79.11 3.245 ;
     RECT  79.848 3.065 79.866 3.245 ;
     RECT  80.715 2.861 81.522 3.245 ;
     RECT  82.404 3.065 82.422 3.245 ;
     RECT  85.464 3.065 87.606 3.245 ;
     RECT  92.592 3.065 92.61 3.245 ;
     RECT  93.456 3.065 94.842 3.245 ;
     RECT  98.856 3.065 100.35 3.245 ;
     RECT  102.315 2.861 105.39 3.245 ;
     RECT  106.308 3.065 106.326 3.245 ;
     RECT  107.352 3.065 108.162 3.245 ;
     RECT  109.332 3.065 109.35 3.245 ;
     RECT  110.376 2.861 113.85 3.245 ;
     RECT  114.948 3.065 114.966 3.245 ;
     RECT  115.704 3.065 116.097 3.245 ;
     RECT  14.724 3.245 14.85 3.335 ;
     RECT  58.968 3.245 59.397 3.335 ;
     RECT  77.832 3.245 78.297 3.335 ;
     RECT  111.42 3.245 113.397 3.335 ;
     RECT  25.848 3.245 25.974 3.341 ;
     RECT  111.636 3.335 113.397 3.341 ;
     RECT  14.832 3.335 14.85 3.437 ;
     RECT  98.892 3.245 99.897 3.437 ;
     RECT  111.636 3.341 111.942 3.437 ;
     RECT  112.824 3.341 113.397 3.437 ;
     RECT  23.364 3.245 24.786 3.605 ;
     RECT  29.016 3.245 29.697 3.605 ;
     RECT  96.915 2.861 97.794 3.721 ;
     RECT  29.16 3.605 29.697 3.773 ;
     RECT  39.816 2.861 42.066 3.811 ;
     RECT  31.5 2.861 32.397 3.955 ;
     RECT  66.456 2.795 67.497 3.965 ;
     RECT  18.468 3.245 18.897 3.979 ;
     RECT  21.096 3.245 21.597 3.979 ;
     RECT  23.472 3.605 24.786 3.979 ;
     RECT  26.715 3.245 26.997 3.979 ;
     RECT  29.232 3.773 29.697 3.979 ;
     RECT  31.5 3.955 32.49 3.979 ;
     RECT  33.84 3.245 35.298 3.979 ;
     RECT  37.515 3.245 38.862 3.979 ;
     RECT  39.816 3.811 42.174 3.979 ;
     RECT  42.915 3.245 43.362 3.979 ;
     RECT  45.615 3.065 45.897 3.979 ;
     RECT  48.24 2.861 48.597 3.979 ;
     RECT  50.976 3.245 51.642 3.979 ;
     RECT  53.715 3.005 54.162 3.979 ;
     RECT  56.415 3.245 56.697 3.979 ;
     RECT  59.115 3.335 59.397 3.979 ;
     RECT  61.776 3.065 62.097 3.979 ;
     RECT  63.576 3.245 64.998 3.979 ;
     RECT  66.996 3.965 67.497 3.979 ;
     RECT  69.915 3.245 70.938 3.979 ;
     RECT  72.615 3.245 72.897 3.979 ;
     RECT  75.315 3.245 75.597 3.979 ;
     RECT  77.904 3.335 78.297 3.979 ;
     RECT  80.715 3.245 80.997 3.979 ;
     RECT  83.232 2.861 83.697 3.979 ;
     RECT  86.115 3.245 87.246 3.979 ;
     RECT  88.815 2.939 90.45 3.979 ;
     RECT  91.515 3.065 91.797 3.979 ;
     RECT  94.104 3.245 94.842 3.979 ;
     RECT  96.915 3.721 97.902 3.979 ;
     RECT  99.288 3.437 99.897 3.979 ;
     RECT  102.315 3.245 103.734 3.979 ;
     RECT  105.015 3.245 105.39 3.979 ;
     RECT  107.715 3.245 107.997 3.979 ;
     RECT  110.376 3.245 110.697 3.979 ;
     RECT  113.004 3.437 113.397 3.979 ;
     RECT  115.815 3.245 116.097 3.979 ;
     RECT  84.924 3.979 93.042 4.027 ;
     RECT  93.78 3.979 95.85 4.027 ;
     RECT  99.288 3.979 100.602 4.027 ;
     RECT  101.34 3.979 103.878 4.027 ;
     RECT  104.688 3.979 106.65 4.027 ;
     RECT  107.532 3.979 107.997 4.027 ;
     RECT  104.688 4.027 107.997 4.123 ;
     RECT  33.84 3.979 42.174 4.145 ;
     RECT  16.92 3.979 18.897 4.261 ;
     RECT  19.62 3.979 22.554 4.261 ;
     RECT  59.115 3.979 62.406 4.261 ;
     RECT  63.252 3.979 66.186 4.261 ;
     RECT  74.34 3.979 76.95 4.261 ;
     RECT  77.904 3.979 83.97 4.261 ;
     RECT  99.288 4.027 103.878 4.261 ;
     RECT  104.688 4.123 108.054 4.261 ;
     RECT  110.088 3.979 110.862 4.261 ;
     RECT  31.356 3.979 32.67 4.301 ;
     RECT  33.948 4.145 42.174 4.301 ;
     RECT  99.288 4.261 108.054 4.301 ;
     RECT  59.115 4.261 66.186 4.415 ;
     RECT  111.924 3.437 111.942 4.415 ;
     RECT  46.8 3.979 52.002 4.459 ;
     RECT  16.92 4.261 22.554 4.495 ;
     RECT  23.472 3.979 25.326 4.495 ;
     RECT  16.92 4.495 25.326 4.507 ;
     RECT  26.715 3.979 28.17 4.507 ;
     RECT  29.232 3.979 30.222 4.507 ;
     RECT  32.076 4.301 32.67 4.507 ;
     RECT  52.848 3.979 54.378 4.507 ;
     RECT  58.356 3.979 58.374 4.507 ;
     RECT  59.115 4.415 66.078 4.507 ;
     RECT  77.832 4.261 83.97 4.507 ;
     RECT  84.924 4.027 95.85 4.507 ;
     RECT  96.732 3.979 98.55 4.507 ;
     RECT  99.288 4.301 99.897 4.507 ;
     RECT  100.908 4.301 108.054 4.507 ;
     RECT  113.004 3.979 113.562 4.507 ;
     RECT  84.924 4.507 95.958 4.531 ;
     RECT  96.732 4.507 99.897 4.531 ;
     RECT  110.088 4.261 110.97 4.531 ;
     RECT  77.832 4.507 84.078 4.541 ;
     RECT  13.215 2.861 13.497 4.555 ;
     RECT  15.915 3.245 16.197 4.555 ;
     RECT  16.92 4.507 25.434 4.555 ;
     RECT  26.715 4.507 28.314 4.555 ;
     RECT  29.232 4.507 30.366 4.555 ;
     RECT  32.076 4.507 32.778 4.555 ;
     RECT  34.164 4.301 42.174 4.555 ;
     RECT  42.915 3.979 46.026 4.555 ;
     RECT  46.8 4.459 52.11 4.555 ;
     RECT  52.848 4.507 54.45 4.555 ;
     RECT  55.368 3.979 57.618 4.555 ;
     RECT  58.356 4.507 66.078 4.555 ;
     RECT  66.996 3.979 68.31 4.555 ;
     RECT  69.084 3.979 73.602 4.555 ;
     RECT  74.34 4.261 77.058 4.555 ;
     RECT  81.936 4.541 84.078 4.555 ;
     RECT  84.924 4.531 99.897 4.555 ;
     RECT  100.908 4.507 108.162 4.555 ;
     RECT  110.088 4.531 111.618 4.555 ;
     RECT  113.004 4.507 113.67 4.555 ;
     RECT  114.552 3.979 116.097 4.555 ;
     RECT  34.164 4.555 66.078 4.559 ;
     RECT  81.936 4.555 99.897 4.559 ;
     RECT  44.532 4.559 51.462 4.685 ;
     RECT  66.996 4.555 77.058 4.685 ;
     RECT  99.108 4.559 99.897 4.685 ;
     RECT  112.356 4.555 116.097 4.685 ;
     RECT  32.076 4.555 32.886 4.801 ;
     RECT  13.215 4.555 31.158 4.877 ;
     RECT  34.164 4.559 38.466 4.877 ;
     RECT  67.032 4.685 77.058 4.877 ;
     RECT  81.936 4.559 98.046 4.877 ;
     RECT  100.908 4.555 111.618 4.877 ;
     RECT  23.292 4.877 24.426 4.955 ;
     RECT  26.604 4.877 31.158 4.973 ;
     RECT  29.415 4.973 31.158 5.071 ;
     RECT  32.076 4.801 32.994 5.071 ;
     RECT  112.464 4.685 116.097 5.071 ;
     RECT  13.215 4.877 22.05 5.117 ;
     RECT  26.604 4.973 28.674 5.117 ;
     RECT  37.188 4.877 37.998 5.117 ;
     RECT  44.532 4.685 51.297 5.117 ;
     RECT  71.784 4.877 77.058 5.117 ;
     RECT  77.832 4.541 80.997 5.117 ;
     RECT  85.248 4.877 93.222 5.117 ;
     RECT  100.908 4.877 102.69 5.117 ;
     RECT  112.464 5.071 116.19 5.117 ;
     RECT  29.415 5.071 31.23 5.131 ;
     RECT  32.076 5.071 33.102 5.131 ;
     RECT  34.164 4.877 36.27 5.131 ;
     RECT  77.832 5.117 78.894 5.131 ;
     RECT  99.144 4.685 99.897 5.131 ;
     RECT  100.908 5.117 101.538 5.131 ;
     RECT  25.668 4.877 25.83 5.225 ;
     RECT  77.184 5.131 78.894 5.225 ;
     RECT  94.215 4.877 98.046 5.225 ;
     RECT  15.084 5.117 18.897 5.261 ;
     RECT  29.415 5.131 33.102 5.341 ;
     RECT  39.348 4.559 41.346 5.341 ;
     RECT  42.12 4.559 43.722 5.341 ;
     RECT  52.452 4.559 66.078 5.341 ;
     RECT  25.812 5.225 25.83 5.405 ;
     RECT  97.956 5.225 98.046 5.405 ;
     RECT  99.144 5.131 101.538 5.405 ;
     RECT  104.832 4.877 111.618 5.405 ;
     RECT  15.084 5.261 16.722 5.495 ;
     RECT  20.016 5.117 22.05 5.495 ;
     RECT  39.348 5.341 43.722 5.495 ;
     RECT  71.784 5.117 76.41 5.495 ;
     RECT  91.368 5.117 93.222 5.495 ;
     RECT  99.144 5.405 100.782 5.495 ;
     RECT  34.056 5.131 36.27 5.605 ;
     RECT  29.415 5.341 33.21 5.611 ;
     RECT  34.056 5.605 36.414 5.611 ;
     RECT  39.456 5.495 43.722 5.611 ;
     RECT  44.532 5.117 46.71 5.611 ;
     RECT  81.936 4.877 84.438 5.611 ;
     RECT  85.248 5.117 90.594 5.611 ;
     RECT  94.215 5.225 97.197 5.611 ;
     RECT  102.312 5.117 102.69 5.611 ;
     RECT  103.464 4.877 104.094 5.611 ;
     RECT  112.572 5.117 116.097 5.645 ;
     RECT  15.3 5.495 16.722 5.693 ;
     RECT  20.16 5.495 22.05 5.693 ;
     RECT  23.292 4.955 24.39 5.693 ;
     RECT  29.415 5.611 36.414 5.693 ;
     RECT  39.456 5.611 46.71 5.693 ;
     RECT  76.392 5.495 76.41 5.693 ;
     RECT  77.4 5.225 78.894 5.693 ;
     RECT  81.936 5.611 90.594 5.693 ;
     RECT  106.956 5.405 111.618 5.693 ;
     RECT  112.572 5.645 113.886 5.693 ;
     RECT  20.448 5.693 22.05 5.707 ;
     RECT  23.796 5.693 24.39 5.707 ;
     RECT  26.604 5.117 27.954 5.707 ;
     RECT  29.415 5.693 30.402 5.707 ;
     RECT  35.928 5.693 36.414 5.707 ;
     RECT  37.515 5.117 37.998 5.707 ;
     RECT  52.308 5.341 66.078 5.707 ;
     RECT  67.032 4.877 71.01 5.707 ;
     RECT  71.784 5.495 75.597 5.707 ;
     RECT  79.632 5.117 80.997 5.707 ;
     RECT  81.936 5.693 90.27 5.707 ;
     RECT  91.515 5.495 93.222 5.707 ;
     RECT  99.144 5.495 100.026 5.707 ;
     RECT  102.312 5.611 104.094 5.707 ;
     RECT  104.832 5.405 106.218 5.707 ;
     RECT  98.028 5.405 98.046 5.755 ;
     RECT  98.784 5.707 100.026 5.755 ;
     RECT  13.215 5.117 14.13 5.765 ;
     RECT  15.588 5.693 16.197 5.765 ;
     RECT  33.336 5.693 35.097 5.765 ;
     RECT  77.58 5.693 78.894 5.765 ;
     RECT  31.392 5.693 32.49 5.873 ;
     RECT  20.448 5.707 22.086 5.881 ;
     RECT  22.824 5.707 22.95 5.881 ;
     RECT  37.515 5.707 38.286 5.881 ;
     RECT  77.652 5.765 78.894 5.881 ;
     RECT  79.632 5.707 90.27 5.881 ;
     RECT  91.515 5.707 93.258 5.881 ;
     RECT  101.52 5.405 101.538 5.881 ;
     RECT  102.312 5.707 106.218 5.881 ;
     RECT  14.256 5.881 14.274 5.933 ;
     RECT  77.652 5.881 90.27 6.035 ;
     RECT  23.796 5.707 24.606 6.151 ;
     RECT  26.208 5.707 27.954 6.151 ;
     RECT  28.764 5.707 30.402 6.151 ;
     RECT  35.928 5.707 36.594 6.151 ;
     RECT  37.515 5.881 38.358 6.151 ;
     RECT  47.52 5.117 51.297 6.151 ;
     RECT  52.02 5.707 66.078 6.151 ;
     RECT  67.032 5.707 75.597 6.151 ;
     RECT  100.764 5.495 100.782 6.232 ;
     RECT  101.52 5.881 106.218 6.232 ;
     RECT  106.956 5.693 109.278 6.232 ;
     RECT  17.532 5.261 18.897 6.235 ;
     RECT  26.208 6.151 30.402 6.235 ;
     RECT  39.456 5.693 44.802 6.235 ;
     RECT  98.028 5.755 100.026 6.235 ;
     RECT  100.764 6.232 109.278 6.235 ;
     RECT  14.652 6.232 14.85 6.269 ;
     RECT  25.812 6.235 30.402 6.269 ;
     RECT  35.928 6.151 38.358 6.269 ;
     RECT  91.515 5.881 93.366 6.269 ;
     RECT  25.812 6.269 27.45 6.277 ;
     RECT  39.348 6.235 44.802 6.277 ;
     RECT  47.52 6.151 66.078 6.277 ;
     RECT  66.996 6.151 75.597 6.277 ;
     RECT  23.796 6.151 24.822 6.283 ;
     RECT  25.668 6.277 27.45 6.283 ;
     RECT  36.864 6.269 38.358 6.283 ;
     RECT  39.168 6.277 44.802 6.283 ;
     RECT  94.176 5.611 97.197 6.283 ;
     RECT  98.028 6.235 109.278 6.283 ;
     RECT  110.196 5.693 111.618 6.283 ;
     RECT  112.572 5.693 113.814 6.283 ;
     RECT  14.652 6.269 14.67 6.317 ;
     RECT  36.864 6.283 44.802 6.317 ;
     RECT  94.176 6.283 109.278 6.317 ;
     RECT  20.448 5.881 22.95 6.575 ;
     RECT  110.196 6.283 113.814 6.575 ;
     RECT  15.696 5.765 16.197 6.691 ;
     RECT  79.74 6.035 90.27 6.691 ;
     RECT  20.448 6.575 22.086 6.715 ;
     RECT  22.824 6.575 22.95 6.749 ;
     RECT  23.796 6.283 27.45 6.749 ;
     RECT  35.928 6.269 36.09 6.749 ;
     RECT  36.864 6.317 38.754 6.749 ;
     RECT  23.796 6.749 27.234 6.781 ;
     RECT  20.088 6.715 22.086 6.808 ;
     RECT  31.392 5.873 32.454 6.808 ;
     RECT  33.552 5.765 35.097 6.808 ;
     RECT  31.392 6.808 35.097 6.817 ;
     RECT  19.944 6.808 22.086 6.845 ;
     RECT  23.292 6.781 27.234 6.845 ;
     RECT  28.224 6.269 29.862 6.845 ;
     RECT  91.515 6.269 92.07 6.845 ;
     RECT  94.176 6.317 98.046 6.853 ;
     RECT  13.215 5.765 13.497 6.859 ;
     RECT  15.696 6.691 16.398 6.859 ;
     RECT  17.244 6.235 18.897 6.859 ;
     RECT  19.944 6.845 21.978 6.859 ;
     RECT  31.392 6.817 35.19 6.859 ;
     RECT  35.928 6.749 36.018 6.859 ;
     RECT  110.268 6.575 113.814 6.859 ;
     RECT  114.624 5.645 116.097 6.859 ;
     RECT  94.104 6.853 98.046 6.881 ;
     RECT  36.864 6.749 38.502 7.115 ;
     RECT  110.268 6.859 116.097 7.115 ;
     RECT  28.332 6.845 29.862 7.231 ;
     RECT  15.516 6.859 21.978 7.277 ;
     RECT  36.972 7.115 38.502 7.277 ;
     RECT  106.956 6.317 109.278 7.277 ;
     RECT  110.268 7.115 114.246 7.277 ;
     RECT  13.215 6.859 14.022 7.321 ;
     RECT  15.516 7.277 19.278 7.385 ;
     RECT  13.215 7.321 14.166 7.435 ;
     RECT  28.332 7.231 29.97 7.435 ;
     RECT  31.14 6.859 36.018 7.435 ;
     RECT  45.615 5.693 46.71 7.435 ;
     RECT  47.52 6.277 75.597 7.435 ;
     RECT  77.652 6.035 78.966 7.435 ;
     RECT  79.74 6.691 90.486 7.435 ;
     RECT  93.348 6.269 93.366 7.435 ;
     RECT  98.82 6.317 99.897 7.435 ;
     RECT  100.764 6.317 106.218 7.435 ;
     RECT  106.956 7.277 107.997 7.435 ;
     RECT  108.72 7.277 109.278 7.435 ;
     RECT  110.268 7.277 112.194 7.435 ;
     RECT  13.215 7.435 15.174 7.655 ;
     RECT  37.08 7.277 38.358 7.655 ;
     RECT  13.215 7.655 13.842 7.661 ;
     RECT  92.736 7.435 93.366 7.723 ;
     RECT  94.104 6.881 95.418 7.723 ;
     RECT  115.128 7.115 116.097 7.765 ;
     RECT  77.652 7.435 90.486 7.771 ;
     RECT  96.156 6.881 98.046 7.771 ;
     RECT  98.82 7.435 107.997 7.771 ;
     RECT  14.688 7.655 15.174 7.805 ;
     RECT  28.332 7.435 36.018 7.805 ;
     RECT  115.128 7.765 116.226 7.805 ;
     RECT  20.016 7.277 21.978 7.861 ;
     RECT  45.615 7.435 76.734 7.861 ;
     RECT  77.544 7.771 90.486 7.861 ;
     RECT  91.515 6.845 91.998 7.861 ;
     RECT  92.736 7.723 95.418 7.861 ;
     RECT  96.156 7.771 107.997 7.861 ;
     RECT  113.04 7.277 114.246 7.861 ;
     RECT  115.128 7.805 116.097 7.861 ;
     RECT  31.284 7.805 36.018 7.925 ;
     RECT  108.72 7.435 112.194 7.925 ;
     RECT  20.016 7.861 22.086 7.963 ;
     RECT  23.508 6.845 27.234 7.963 ;
     RECT  28.332 7.805 30.186 7.963 ;
     RECT  33.732 7.925 36.018 7.963 ;
     RECT  39.636 6.317 43.614 7.963 ;
     RECT  44.352 6.317 44.802 7.963 ;
     RECT  45.615 7.861 91.998 7.963 ;
     RECT  92.736 7.861 107.997 7.963 ;
     RECT  39.384 7.963 107.997 8.005 ;
     RECT  108.72 7.925 109.278 8.005 ;
     RECT  37.188 7.655 38.358 8.011 ;
     RECT  39.384 8.005 109.278 8.011 ;
     RECT  15.915 7.385 19.278 8.239 ;
     RECT  20.016 7.963 22.518 8.239 ;
     RECT  33.732 7.963 36.342 8.311 ;
     RECT  110.196 7.925 112.194 8.347 ;
     RECT  113.04 7.861 116.097 8.347 ;
     RECT  14.94 7.805 15.174 8.401 ;
     RECT  15.915 8.239 22.518 8.401 ;
     RECT  33.732 8.311 36.45 8.509 ;
     RECT  37.188 8.011 109.278 8.509 ;
     RECT  13.215 7.661 13.77 8.539 ;
     RECT  14.94 8.401 22.518 8.539 ;
     RECT  23.4 7.963 30.186 8.539 ;
     RECT  31.284 7.925 32.994 8.539 ;
     RECT  14.94 8.539 32.994 8.815 ;
     RECT  33.732 8.509 109.278 8.815 ;
     RECT  13.215 8.539 14.202 8.851 ;
     RECT  14.94 8.815 109.278 8.851 ;
     RECT  110.196 8.347 116.097 8.851 ;
     RECT  13.215 8.851 109.278 8.941 ;
     RECT  110.196 8.851 116.298 9.067 ;
     RECT  13.215 8.941 109.386 9.115 ;
     RECT  110.124 9.067 116.298 9.115 ;
     RECT  13.215 9.115 116.298 9.293 ;
     RECT  23.148 9.293 116.298 10.085 ;
     RECT  13.215 9.293 22.014 10.165 ;
     RECT  23.148 10.085 116.262 10.165 ;
     RECT  13.215 10.165 116.262 10.315 ;
     RECT  13.212 10.315 116.262 11.011 ;
     RECT  13.104 11.011 116.37 11.129 ;
     RECT  13.104 11.129 116.298 11.281 ;
     RECT  12.96 11.281 116.298 11.453 ;
     RECT  13.215 11.453 116.298 12.217 ;
     RECT  13.215 12.217 116.334 12.749 ;
     RECT  13.215 12.749 116.262 13.199 ;
     RECT  13.215 13.199 116.19 16.501 ;
     RECT  2.415 2.413 2.697 19.187 ;
     RECT  5.115 2.413 5.397 19.187 ;
     RECT  7.815 2.413 8.097 19.187 ;
     RECT  10.515 2.413 10.797 19.187 ;
     RECT  118.515 2.413 118.797 19.187 ;
     RECT  121.215 2.413 121.497 19.187 ;
     RECT  123.915 2.413 124.197 19.187 ;
     RECT  126.615 2.413 126.897 19.187 ;
     RECT  13.215 16.501 116.226 19.373 ;
     RECT  25.452 19.373 30.15 19.409 ;
     RECT  83.196 19.373 98.55 19.409 ;
     RECT  2.415 19.187 2.505 19.457 ;
     RECT  5.115 19.187 5.205 19.457 ;
     RECT  7.815 19.187 7.905 19.457 ;
     RECT  10.515 19.187 10.605 19.457 ;
     RECT  13.215 19.373 20.25 19.457 ;
     RECT  107.715 19.373 116.226 19.457 ;
     RECT  118.515 19.187 118.605 19.457 ;
     RECT  121.215 19.187 121.305 19.457 ;
     RECT  123.915 19.187 124.005 19.457 ;
     RECT  126.615 19.187 126.705 19.457 ;
     RECT  20.988 19.373 24.498 19.565 ;
     RECT  28.908 19.409 30.15 19.565 ;
     RECT  39.168 19.373 40.374 19.565 ;
     RECT  52.884 19.373 64.962 19.565 ;
     RECT  101.916 19.373 102.582 19.565 ;
     RECT  107.856 19.457 116.226 19.565 ;
     RECT  25.452 19.409 27.702 19.613 ;
     RECT  41.436 19.373 43.326 19.613 ;
     RECT  44.208 19.373 50.094 19.613 ;
     RECT  77.94 19.373 81.81 19.613 ;
     RECT  108.612 19.565 115.974 19.613 ;
     RECT  83.196 19.409 98.334 19.661 ;
     RECT  41.436 19.613 43.29 19.709 ;
     RECT  78.48 19.613 81.81 19.709 ;
     RECT  44.208 19.613 48.654 19.949 ;
     RECT  52.884 19.565 61.794 19.949 ;
     RECT  69.408 19.373 70.398 19.949 ;
     RECT  72.216 19.373 77.166 19.949 ;
     RECT  78.48 19.709 80.19 19.949 ;
     RECT  81.252 19.709 81.81 19.949 ;
     RECT  83.196 19.661 83.214 19.949 ;
     RECT  84.204 19.661 98.334 19.949 ;
     RECT  103.644 19.373 106.974 19.949 ;
     RECT  99.504 19.373 101.178 19.997 ;
     RECT  39.168 19.565 40.086 20.045 ;
     RECT  52.884 19.949 60.858 20.429 ;
     RECT  13.644 19.457 20.25 20.477 ;
     RECT  52.884 20.429 57.006 20.477 ;
     RECT  13.644 20.477 17.982 20.525 ;
     RECT  18.756 20.477 20.25 20.525 ;
     RECT  20.988 19.565 24.354 20.525 ;
     RECT  27.108 19.613 27.702 20.525 ;
     RECT  28.908 19.565 29.394 20.525 ;
     RECT  30.132 19.565 30.15 20.525 ;
     RECT  31.716 19.373 38.394 20.525 ;
     RECT  39.168 20.045 39.834 20.525 ;
     RECT  41.436 19.709 43.254 20.525 ;
     RECT  44.208 19.949 48.294 20.525 ;
     RECT  49.464 19.613 50.094 20.525 ;
     RECT  50.976 19.373 52.11 20.525 ;
     RECT  52.884 20.477 53.55 20.525 ;
     RECT  54.504 20.477 57.006 20.525 ;
     RECT  57.888 20.429 60.858 20.525 ;
     RECT  61.776 19.949 61.794 20.525 ;
     RECT  62.676 19.565 64.962 20.525 ;
     RECT  65.88 19.373 68.634 20.525 ;
     RECT  72.216 19.949 76.194 20.525 ;
     RECT  78.552 19.949 80.19 20.525 ;
     RECT  81.252 19.949 81.27 20.525 ;
     RECT  84.816 19.949 92.214 20.525 ;
     RECT  93.276 19.949 98.334 20.525 ;
     RECT  100.152 19.997 101.178 20.525 ;
     RECT  101.916 19.565 102.474 20.525 ;
     RECT  103.644 19.949 104.814 20.525 ;
     RECT  105.66 19.949 106.758 20.525 ;
     RECT  107.856 19.565 107.874 20.525 ;
     RECT  108.612 19.613 112.626 20.525 ;
     RECT  113.796 19.613 115.974 20.525 ;
     RECT  65.88 20.525 66.006 20.573 ;
     RECT  58.464 20.525 60.858 21.437 ;
     RECT  35.64 20.525 35.802 21.485 ;
     RECT  52.956 20.525 53.226 21.485 ;
     RECT  69.48 19.949 70.398 21.485 ;
     RECT  94.356 20.525 94.59 21.485 ;
     RECT  110.376 20.525 112.482 21.485 ;
     RECT  13.644 20.525 14.13 21.533 ;
     RECT  14.904 20.525 15.606 21.533 ;
     RECT  16.884 20.525 16.902 21.533 ;
     RECT  18.756 20.525 18.774 21.533 ;
     RECT  21.456 20.525 23.166 21.533 ;
     RECT  24.336 20.525 24.354 21.533 ;
     RECT  25.452 19.613 26.082 21.533 ;
     RECT  28.908 20.525 28.926 21.533 ;
     RECT  31.824 20.525 31.842 21.533 ;
     RECT  32.94 20.525 33.498 21.533 ;
     RECT  35.64 21.485 35.658 21.533 ;
     RECT  36.756 20.525 36.774 21.533 ;
     RECT  37.836 20.525 37.854 21.533 ;
     RECT  39.564 20.525 39.582 21.533 ;
     RECT  41.436 20.525 42.102 21.533 ;
     RECT  44.208 20.525 44.766 21.533 ;
     RECT  46.404 20.525 46.422 21.533 ;
     RECT  47.7 20.525 47.718 21.533 ;
     RECT  52.956 21.485 52.974 21.533 ;
     RECT  55.116 20.525 55.134 21.533 ;
     RECT  56.736 20.525 56.754 21.533 ;
     RECT  58.464 21.437 60.822 21.533 ;
     RECT  63.144 20.525 63.162 21.533 ;
     RECT  64.26 20.525 64.962 21.533 ;
     RECT  65.988 20.573 66.006 21.533 ;
     RECT  67.104 20.525 68.202 21.533 ;
     RECT  69.48 21.485 69.498 21.533 ;
     RECT  70.38 21.485 70.398 21.533 ;
     RECT  73.26 20.525 73.278 21.533 ;
     RECT  74.052 20.525 74.07 21.533 ;
     RECT  75.672 20.525 75.69 21.533 ;
     RECT  77.148 19.949 77.166 21.533 ;
     RECT  78.984 20.525 79.002 21.533 ;
     RECT  79.884 20.525 79.902 21.533 ;
     RECT  84.816 20.525 84.834 21.533 ;
     RECT  87.696 20.525 88.254 21.533 ;
     RECT  90.936 20.525 90.954 21.533 ;
     RECT  92.16 20.525 92.178 21.533 ;
     RECT  93.456 20.525 93.474 21.533 ;
     RECT  94.356 21.485 94.374 21.533 ;
     RECT  97.272 20.525 97.29 21.533 ;
     RECT  101.16 20.525 101.178 21.533 ;
     RECT  104.076 20.525 104.094 21.533 ;
     RECT  105.876 20.525 105.894 21.533 ;
     RECT  108.828 20.525 109.35 21.533 ;
     RECT  110.376 21.485 112.158 21.533 ;
     RECT  114.516 20.525 114.534 21.533 ;
     RECT  115.956 20.525 115.974 21.533 ;
    LAYER M4 ;
     RECT  0.181 13.392 2.408 13.416 ;
     RECT  2.408 2.148 2.512 19.452 ;
     RECT  2.512 2.418 2.704 19.182 ;
     RECT  2.704 13.392 5.108 13.416 ;
     RECT  5.108 2.148 5.212 19.452 ;
     RECT  5.212 2.418 5.404 19.182 ;
     RECT  5.404 13.392 7.808 13.416 ;
     RECT  7.808 2.148 7.912 19.452 ;
     RECT  7.912 2.418 8.104 19.182 ;
     RECT  8.104 13.392 10.508 13.416 ;
     RECT  10.508 2.148 10.612 19.452 ;
     RECT  10.612 2.418 10.804 19.182 ;
     RECT  13.093 7.968 13.208 7.992 ;
     RECT  13.093 10.32 13.208 10.344 ;
     RECT  12.949 11.424 13.208 11.448 ;
     RECT  10.804 13.392 13.208 13.416 ;
     RECT  13.208 2.148 13.312 19.452 ;
     RECT  13.312 2.148 13.345 19.368 ;
     RECT  13.345 2.016 13.504 19.368 ;
     RECT  13.504 2.016 13.523 3.24 ;
     RECT  13.477 21.504 13.669 21.528 ;
     RECT  13.669 21.456 14.033 21.528 ;
     RECT  13.504 4.56 14.099 11.976 ;
     RECT  14.099 7.344 14.188 11.976 ;
     RECT  14.188 7.44 14.249 11.976 ;
     RECT  14.099 4.56 14.285 6.312 ;
     RECT  13.504 18.24 14.501 18.36 ;
     RECT  14.249 11.952 14.641 11.976 ;
     RECT  13.523 2.304 14.677 3.24 ;
     RECT  14.437 20.496 14.789 20.52 ;
     RECT  14.641 11.952 14.819 12.024 ;
     RECT  14.677 2.304 14.861 3.432 ;
     RECT  13.504 13.392 14.965 13.416 ;
     RECT  14.965 13.104 15.181 13.416 ;
     RECT  14.501 18.336 15.205 18.36 ;
     RECT  13.504 19.344 15.205 19.368 ;
     RECT  14.285 4.56 15.289 5.16 ;
     RECT  14.285 6.24 15.289 6.312 ;
     RECT  14.249 7.44 15.289 10.872 ;
     RECT  14.819 11.952 15.289 11.976 ;
     RECT  15.289 7.44 15.349 11.976 ;
     RECT  15.289 4.56 15.505 6.312 ;
     RECT  15.349 7.344 15.505 11.976 ;
     RECT  14.821 17.136 15.613 17.16 ;
     RECT  15.205 18.336 15.613 19.368 ;
     RECT  14.033 21.504 15.617 21.528 ;
     RECT  15.613 17.136 15.713 19.368 ;
     RECT  15.505 4.56 15.781 11.976 ;
     RECT  14.861 2.304 15.908 3.24 ;
     RECT  15.781 4.512 15.908 11.976 ;
     RECT  15.181 13.104 15.908 13.656 ;
     RECT  15.713 17.088 15.908 19.368 ;
     RECT  15.908 2.148 16.012 19.452 ;
     RECT  16.012 2.148 16.153 19.368 ;
     RECT  15.973 20.496 16.156 20.52 ;
     RECT  16.153 1.728 16.204 19.368 ;
     RECT  16.204 1.728 16.237 13.416 ;
     RECT  15.637 0.144 16.355 0.168 ;
     RECT  16.237 2.208 16.547 13.416 ;
     RECT  16.204 16.56 16.697 17.688 ;
     RECT  16.697 16.56 16.849 16.584 ;
     RECT  16.547 2.208 16.877 10.632 ;
     RECT  16.741 21.504 16.913 21.528 ;
     RECT  16.877 2.208 17.305 2.856 ;
     RECT  16.156 20.448 17.317 20.52 ;
     RECT  16.877 3.984 17.989 10.632 ;
     RECT  16.547 12.192 17.989 13.416 ;
     RECT  17.305 1.728 18.181 2.856 ;
     RECT  17.989 3.984 18.181 13.416 ;
     RECT  16.697 17.664 18.277 17.688 ;
     RECT  18.181 1.728 18.421 13.416 ;
     RECT  16.204 19.344 18.529 19.368 ;
     RECT  17.317 20.4 18.529 20.52 ;
     RECT  18.421 1.728 18.608 13.704 ;
     RECT  18.277 17.664 18.608 18.264 ;
     RECT  18.529 19.344 18.608 20.52 ;
     RECT  18.421 0.144 18.707 0.168 ;
     RECT  18.608 1.728 18.707 20.52 ;
     RECT  18.707 1.728 18.712 19.452 ;
     RECT  18.469 21.504 18.785 21.528 ;
     RECT  18.707 20.448 18.853 20.52 ;
     RECT  18.712 1.728 18.904 19.368 ;
     RECT  18.904 8.544 18.929 11.976 ;
     RECT  18.904 6.288 19.043 7.272 ;
     RECT  18.853 20.448 19.043 21.432 ;
     RECT  18.929 8.544 19.073 11.448 ;
     RECT  18.904 17.088 19.289 19.368 ;
     RECT  18.904 1.728 19.369 2.856 ;
     RECT  19.289 17.088 19.715 17.112 ;
     RECT  18.904 13.008 19.721 13.656 ;
     RECT  19.073 8.544 19.897 11.016 ;
     RECT  19.289 18.144 19.937 19.368 ;
     RECT  19.043 20.448 19.937 20.52 ;
     RECT  19.897 8.256 19.955 11.016 ;
     RECT  18.904 14.784 19.955 14.808 ;
     RECT  18.904 3.984 20.005 5.112 ;
     RECT  19.043 6.72 20.005 7.272 ;
     RECT  19.955 8.256 20.005 9.576 ;
     RECT  19.721 13.008 20.081 13.416 ;
     RECT  20.005 3.984 20.149 5.16 ;
     RECT  19.955 10.848 20.221 11.016 ;
     RECT  19.369 1.728 20.365 2.808 ;
     RECT  20.365 1.728 20.437 2.856 ;
     RECT  20.149 3.984 20.437 5.688 ;
     RECT  20.005 6.72 20.437 9.576 ;
     RECT  19.937 19.248 21.229 19.368 ;
     RECT  19.937 20.496 21.229 20.52 ;
     RECT  20.437 1.728 21.308 9.576 ;
     RECT  20.221 10.848 21.308 11.448 ;
     RECT  20.081 13.392 21.308 13.416 ;
     RECT  19.909 15.84 21.308 15.864 ;
     RECT  19.937 18.144 21.308 18.264 ;
     RECT  21.229 19.248 21.308 20.52 ;
     RECT  21.308 1.728 21.604 20.52 ;
     RECT  21.604 19.248 21.665 20.52 ;
     RECT  21.665 20.496 21.917 20.52 ;
     RECT  21.604 1.728 22.033 9.72 ;
     RECT  22.033 7.872 22.108 9.72 ;
     RECT  22.033 1.728 22.141 6.84 ;
     RECT  21.604 13.392 22.597 13.416 ;
     RECT  22.597 13.104 22.661 13.416 ;
     RECT  21.604 15.84 22.7 15.864 ;
     RECT  21.604 17.088 22.7 17.112 ;
     RECT  22.7 15.84 22.741 17.112 ;
     RECT  21.604 18.144 22.741 18.168 ;
     RECT  22.141 1.728 22.745 6.744 ;
     RECT  22.741 14.928 22.787 18.168 ;
     RECT  22.108 7.968 22.789 9.72 ;
     RECT  21.604 10.704 22.789 11.976 ;
     RECT  21.665 19.248 22.817 19.368 ;
     RECT  22.745 2.256 22.853 6.744 ;
     RECT  22.853 2.304 23.269 6.744 ;
     RECT  23.269 2.304 23.497 6.84 ;
     RECT  22.789 7.968 23.497 11.976 ;
     RECT  22.817 19.344 23.813 19.368 ;
     RECT  23.077 20.496 23.861 20.52 ;
     RECT  23.497 2.304 23.893 11.976 ;
     RECT  23.893 2.064 23.965 11.976 ;
     RECT  23.965 1.728 24.008 11.976 ;
     RECT  22.661 13.104 24.008 13.656 ;
     RECT  22.787 14.928 24.008 14.952 ;
     RECT  22.787 17.376 24.008 17.592 ;
     RECT  23.813 19.248 24.008 19.368 ;
     RECT  24.008 1.728 24.229 19.452 ;
     RECT  24.229 1.728 24.304 19.56 ;
     RECT  24.304 1.728 24.365 13.416 ;
     RECT  24.365 1.728 24.481 10.296 ;
     RECT  24.304 19.008 24.509 19.56 ;
     RECT  24.304 14.928 24.545 14.952 ;
     RECT  24.481 1.728 24.755 7.272 ;
     RECT  24.755 1.728 24.797 5.208 ;
     RECT  24.509 19.008 25.085 19.368 ;
     RECT  24.304 17.376 25.333 17.4 ;
     RECT  24.797 1.728 25.445 2.856 ;
     RECT  25.333 16.8 25.469 17.4 ;
     RECT  24.755 6.24 25.477 7.272 ;
     RECT  24.481 8.352 25.477 10.296 ;
     RECT  25.469 16.56 25.553 17.4 ;
     RECT  24.797 3.984 25.571 5.208 ;
     RECT  25.445 2.208 25.597 2.856 ;
     RECT  25.571 4.56 25.765 5.208 ;
     RECT  25.477 6.24 25.765 10.296 ;
     RECT  25.597 2.304 25.837 2.856 ;
     RECT  25.837 2.304 25.909 2.904 ;
     RECT  25.765 4.56 26.089 10.296 ;
     RECT  24.365 11.424 26.089 13.416 ;
     RECT  21.157 21.504 26.093 21.528 ;
     RECT  25.553 16.8 26.581 17.4 ;
     RECT  25.085 19.248 26.593 19.368 ;
     RECT  25.909 2.304 26.708 3.336 ;
     RECT  26.089 4.56 26.708 13.416 ;
     RECT  26.581 15.984 26.708 17.4 ;
     RECT  26.593 19.248 26.708 19.608 ;
     RECT  26.708 2.148 26.725 19.608 ;
     RECT  26.725 2.016 26.771 19.608 ;
     RECT  26.771 2.016 26.812 19.452 ;
     RECT  26.812 2.016 26.917 19.368 ;
     RECT  26.917 1.728 27.004 19.368 ;
     RECT  27.004 15.984 27.065 18.168 ;
     RECT  27.004 3.984 27.251 9.816 ;
     RECT  27.065 16.56 27.683 18.168 ;
     RECT  27.004 11.424 27.713 13.656 ;
     RECT  26.917 20.496 27.713 20.52 ;
     RECT  27.683 16.56 27.757 17.112 ;
     RECT  27.757 16.56 27.827 16.584 ;
     RECT  27.713 11.424 27.901 13.512 ;
     RECT  27.901 11.472 27.923 13.512 ;
     RECT  27.004 1.728 28.033 2.856 ;
     RECT  27.683 18.144 28.069 18.168 ;
     RECT  28.033 1.728 28.165 2.904 ;
     RECT  27.251 3.984 28.165 6.744 ;
     RECT  28.165 1.728 28.277 6.744 ;
     RECT  28.277 1.728 28.321 6.84 ;
     RECT  27.251 7.968 28.321 9.816 ;
     RECT  28.069 18.144 28.412 18.264 ;
     RECT  27.004 19.296 28.412 19.368 ;
     RECT  28.321 1.728 28.429 9.816 ;
     RECT  27.923 13.392 28.897 13.512 ;
     RECT  27.923 11.472 28.93 12.36 ;
     RECT  28.429 1.728 28.933 9.864 ;
     RECT  28.93 11.424 28.933 12.36 ;
     RECT  28.645 21.504 28.937 21.528 ;
     RECT  28.933 1.728 29.269 12.36 ;
     RECT  28.897 13.392 29.269 13.704 ;
     RECT  28.412 18.144 29.269 19.368 ;
     RECT  29.221 20.496 29.269 20.52 ;
     RECT  29.269 1.728 29.408 14.136 ;
     RECT  29.077 16.56 29.408 16.584 ;
     RECT  29.269 18.144 29.408 20.52 ;
     RECT  29.408 1.728 29.651 20.52 ;
     RECT  29.651 2.064 29.704 19.368 ;
     RECT  29.704 2.064 29.729 13.656 ;
     RECT  29.729 2.304 29.917 13.656 ;
     RECT  29.917 7.248 29.981 13.656 ;
     RECT  29.704 15.984 30.131 16.584 ;
     RECT  29.651 20.496 30.161 20.52 ;
     RECT  30.131 16.56 30.179 16.584 ;
     RECT  29.917 2.304 30.233 6.264 ;
     RECT  29.981 7.44 30.449 13.656 ;
     RECT  30.449 7.44 30.521 13.416 ;
     RECT  30.233 2.304 30.556 3.24 ;
     RECT  30.521 7.44 30.611 9.72 ;
     RECT  30.757 0.096 30.899 0.12 ;
     RECT  29.704 18.144 30.953 19.368 ;
     RECT  30.233 4.512 31.129 6.264 ;
     RECT  30.611 7.44 31.129 9.672 ;
     RECT  30.556 2.304 31.333 2.904 ;
     RECT  31.129 4.512 31.345 9.672 ;
     RECT  31.333 1.728 31.669 2.904 ;
     RECT  31.345 3.984 31.669 9.672 ;
     RECT  30.953 19.248 31.877 19.368 ;
     RECT  31.333 20.496 31.877 20.52 ;
     RECT  31.669 1.728 31.957 9.672 ;
     RECT  30.521 10.848 31.957 13.416 ;
     RECT  30.953 18.144 31.993 18.168 ;
     RECT  31.957 1.728 32.108 13.416 ;
     RECT  31.993 17.616 32.108 18.168 ;
     RECT  31.877 19.248 32.108 20.52 ;
     RECT  31.957 0.144 32.147 0.168 ;
     RECT  32.108 1.728 32.404 20.52 ;
     RECT  32.404 19.344 32.681 20.52 ;
     RECT  32.404 3.984 32.867 5.736 ;
     RECT  32.404 6.816 33.011 9.72 ;
     RECT  32.404 12.288 33.077 13.416 ;
     RECT  33.011 6.816 33.113 9.624 ;
     RECT  32.404 1.728 33.433 2.856 ;
     RECT  30.757 21.504 33.509 21.528 ;
     RECT  32.867 4.56 33.541 5.736 ;
     RECT  33.433 1.728 33.589 2.904 ;
     RECT  33.113 7.344 33.761 9.624 ;
     RECT  33.589 1.728 33.829 3.24 ;
     RECT  33.541 4.56 33.829 6.312 ;
     RECT  32.681 20.496 33.829 20.52 ;
     RECT  33.829 1.728 34.117 6.312 ;
     RECT  33.761 7.344 34.117 9.288 ;
     RECT  32.404 10.848 34.153 10.92 ;
     RECT  34.153 10.848 34.297 10.968 ;
     RECT  32.681 19.344 34.597 19.368 ;
     RECT  33.077 12.48 34.657 13.416 ;
     RECT  34.297 10.272 34.693 10.968 ;
     RECT  34.657 11.952 34.693 13.416 ;
     RECT  34.117 1.728 34.808 9.288 ;
     RECT  34.693 10.272 34.808 13.416 ;
     RECT  32.404 17.616 34.808 17.64 ;
     RECT  34.597 19.248 34.808 19.368 ;
     RECT  34.808 1.728 34.849 19.452 ;
     RECT  34.849 2.016 34.912 19.452 ;
     RECT  33.829 20.448 35.057 20.52 ;
     RECT  34.912 2.016 35.104 19.368 ;
     RECT  35.104 10.8 35.219 13.656 ;
     RECT  35.057 20.448 35.309 20.472 ;
     RECT  35.104 2.016 35.315 3 ;
     RECT  35.315 2.016 35.353 2.904 ;
     RECT  35.365 21.504 35.557 21.528 ;
     RECT  35.557 21.456 35.813 21.528 ;
     RECT  35.353 2.016 35.917 2.856 ;
     RECT  35.104 3.984 36.133 9.672 ;
     RECT  35.219 10.8 36.133 12.024 ;
     RECT  35.219 13.104 36.275 13.656 ;
     RECT  36.133 3.984 36.353 12.024 ;
     RECT  35.917 1.728 36.673 2.856 ;
     RECT  36.673 1.728 36.709 2.904 ;
     RECT  36.709 1.728 36.805 3 ;
     RECT  36.353 3.984 36.805 11.448 ;
     RECT  35.104 18.768 37.429 19.368 ;
     RECT  36.133 20.496 37.429 20.52 ;
     RECT  36.805 1.728 37.508 11.448 ;
     RECT  36.275 13.392 37.508 13.656 ;
     RECT  35.104 17.616 37.508 17.64 ;
     RECT  37.429 18.768 37.508 20.52 ;
     RECT  37.508 1.728 37.804 20.52 ;
     RECT  35.813 21.504 37.865 21.528 ;
     RECT  37.804 17.088 38.044 18.264 ;
     RECT  37.804 19.248 38.189 20.52 ;
     RECT  38.044 17.616 38.333 18.264 ;
     RECT  37.804 1.728 38.387 10.728 ;
     RECT  38.387 6.24 38.524 10.728 ;
     RECT  38.189 19.248 38.729 19.368 ;
     RECT  38.524 6.24 38.771 6.744 ;
     RECT  38.524 7.968 38.801 10.728 ;
     RECT  38.801 10.704 39.089 10.728 ;
     RECT  39.193 16.608 39.301 16.632 ;
     RECT  37.804 12.528 39.397 13.656 ;
     RECT  39.229 10.848 39.409 10.872 ;
     RECT  38.387 1.728 39.445 5.16 ;
     RECT  38.771 6.24 39.445 6.312 ;
     RECT  38.333 18.24 39.445 18.264 ;
     RECT  39.445 1.728 39.761 6.312 ;
     RECT  39.761 1.728 39.781 6.888 ;
     RECT  38.801 7.968 39.781 9.096 ;
     RECT  38.189 20.496 39.845 20.52 ;
     RECT  38.729 19.344 39.932 19.368 ;
     RECT  39.445 18.144 39.985 18.264 ;
     RECT  39.932 19.344 39.985 20.04 ;
     RECT  39.409 10.848 40.021 11.256 ;
     RECT  39.397 12.528 40.021 14.28 ;
     RECT  39.781 1.728 40.069 9.096 ;
     RECT  40.069 1.728 40.208 9.432 ;
     RECT  40.021 10.848 40.208 14.28 ;
     RECT  39.301 16.512 40.208 16.632 ;
     RECT  39.985 18.144 40.208 20.04 ;
     RECT  40.208 1.728 40.211 20.04 ;
     RECT  40.211 1.728 40.403 19.56 ;
     RECT  40.403 1.728 40.504 19.368 ;
     RECT  40.549 0.096 40.691 0.12 ;
     RECT  40.504 1.728 40.753 6.312 ;
     RECT  40.504 11.232 40.817 13.416 ;
     RECT  40.504 18.144 40.853 19.368 ;
     RECT  40.504 7.44 40.889 9.72 ;
     RECT  40.889 7.776 40.979 9.72 ;
     RECT  40.853 19.248 40.997 19.368 ;
     RECT  40.979 7.776 41.02 9.144 ;
     RECT  40.817 11.376 41.041 13.416 ;
     RECT  41.02 8.304 41.164 9.144 ;
     RECT  41.041 11.376 41.501 11.4 ;
     RECT  40.753 1.728 41.857 5.16 ;
     RECT  40.753 6.24 41.857 6.312 ;
     RECT  41.857 1.728 41.929 6.312 ;
     RECT  41.821 10.848 42.001 10.872 ;
     RECT  41.041 12.432 42.029 13.416 ;
     RECT  41.929 1.728 42.037 6.888 ;
     RECT  41.965 17.088 42.037 17.112 ;
     RECT  39.397 21.504 42.113 21.528 ;
     RECT  42.037 1.728 42.157 7.416 ;
     RECT  42.001 10.704 42.181 10.872 ;
     RECT  41.164 8.448 42.577 9.144 ;
     RECT  42.181 10.272 42.577 10.872 ;
     RECT  40.997 19.344 42.661 19.368 ;
     RECT  42.577 8.448 42.757 10.872 ;
     RECT  42.029 12 42.757 13.416 ;
     RECT  42.157 2.016 42.908 7.416 ;
     RECT  42.757 8.448 42.908 13.416 ;
     RECT  42.037 16.56 42.908 17.112 ;
     RECT  40.853 18.144 42.908 18.168 ;
     RECT  42.661 19.248 42.908 19.368 ;
     RECT  42.908 2.016 43.045 19.452 ;
     RECT  41.701 20.496 43.045 20.52 ;
     RECT  43.045 2.016 43.204 20.52 ;
     RECT  43.204 18.144 43.265 20.52 ;
     RECT  43.265 18.144 43.301 19.704 ;
     RECT  43.301 18.144 43.337 19.608 ;
     RECT  43.204 2.016 43.585 6.312 ;
     RECT  43.585 1.728 43.741 6.312 ;
     RECT  43.741 1.728 44.339 6.264 ;
     RECT  44.339 1.728 44.38 5.16 ;
     RECT  44.339 6.24 44.425 6.264 ;
     RECT  44.005 21.504 44.777 21.528 ;
     RECT  43.337 18.144 45.356 19.368 ;
     RECT  44.38 3.984 45.493 5.16 ;
     RECT  45.356 17.616 45.5 19.368 ;
     RECT  45.157 20.496 45.5 20.52 ;
     RECT  45.5 17.616 45.587 20.52 ;
     RECT  44.38 1.728 45.608 2.856 ;
     RECT  45.493 3.984 45.608 5.688 ;
     RECT  43.204 7.968 45.608 13.416 ;
     RECT  45.205 16.56 45.608 16.584 ;
     RECT  45.587 17.616 45.608 19.452 ;
     RECT  45.608 1.728 45.712 19.452 ;
     RECT  45.712 1.728 45.904 19.368 ;
     RECT  45.733 0.144 46.019 0.168 ;
     RECT  45.904 7.632 46.019 9.336 ;
     RECT  45.587 20.448 46.145 20.52 ;
     RECT  46.309 21.504 46.433 21.528 ;
     RECT  45.904 1.728 46.613 5.208 ;
     RECT  46.613 1.728 46.643 5.16 ;
     RECT  46.643 1.728 46.685 5.112 ;
     RECT  45.904 16.56 46.739 19.368 ;
     RECT  46.019 7.776 46.757 9.336 ;
     RECT  46.739 16.56 46.933 18.264 ;
     RECT  46.933 16.512 46.979 18.264 ;
     RECT  46.757 7.776 47.365 9.096 ;
     RECT  46.685 3.984 47.653 5.112 ;
     RECT  47.461 21.504 47.729 21.528 ;
     RECT  46.979 18.24 47.761 18.264 ;
     RECT  46.739 19.296 47.761 19.368 ;
     RECT  47.365 7.44 47.869 9.096 ;
     RECT  45.904 12.048 47.893 13.416 ;
     RECT  47.893 12.048 47.989 14.808 ;
     RECT  47.869 7.44 48.013 9.144 ;
     RECT  47.653 3.984 48.085 5.16 ;
     RECT  46.979 16.512 48.121 17.112 ;
     RECT  45.904 10.608 48.133 10.92 ;
     RECT  47.989 11.952 48.133 14.808 ;
     RECT  46.685 1.728 48.181 2.856 ;
     RECT  48.085 3.84 48.181 5.16 ;
     RECT  47.761 18.24 48.229 19.368 ;
     RECT  46.145 20.496 48.229 20.52 ;
     RECT  48.013 6.864 48.265 9.144 ;
     RECT  47.941 0.096 48.275 0.12 ;
     RECT  48.181 1.728 48.308 5.16 ;
     RECT  48.265 6.864 48.308 9.288 ;
     RECT  48.133 10.608 48.308 14.808 ;
     RECT  48.121 16.512 48.308 17.16 ;
     RECT  48.229 18.24 48.308 20.52 ;
     RECT  48.308 1.728 48.604 20.52 ;
     RECT  48.604 7.968 48.755 10.92 ;
     RECT  48.604 19.344 48.773 20.52 ;
     RECT  48.755 7.968 48.899 9.288 ;
     RECT  48.604 17.088 49.025 17.16 ;
     RECT  48.604 1.728 49.097 2.856 ;
     RECT  48.604 12.288 49.673 13.944 ;
     RECT  48.755 10.896 49.741 10.92 ;
     RECT  49.673 12.288 49.741 13.416 ;
     RECT  48.773 20.448 49.961 20.52 ;
     RECT  48.604 3.984 50.005 4.632 ;
     RECT  48.899 8.544 50.029 9.288 ;
     RECT  49.741 10.896 50.029 13.416 ;
     RECT  50.005 3.984 50.053 5.16 ;
     RECT  49.765 6.192 50.053 6.216 ;
     RECT  49.025 17.088 50.101 17.112 ;
     RECT  50.101 17.088 50.149 17.688 ;
     RECT  49.097 1.728 50.389 2.76 ;
     RECT  50.389 1.728 50.393 2.904 ;
     RECT  50.393 2.016 50.437 2.904 ;
     RECT  50.053 3.984 50.437 6.216 ;
     RECT  50.029 7.968 50.533 9.288 ;
     RECT  50.029 10.272 50.533 13.416 ;
     RECT  48.773 19.344 50.533 19.368 ;
     RECT  50.533 7.968 50.773 13.416 ;
     RECT  50.497 15.984 50.773 16.008 ;
     RECT  50.149 17.088 50.773 18.264 ;
     RECT  50.773 15.984 50.821 18.264 ;
     RECT  50.533 19.248 50.821 19.368 ;
     RECT  50.821 0.096 50.869 0.12 ;
     RECT  50.869 0.096 50.963 0.216 ;
     RECT  50.821 21.504 50.963 21.528 ;
     RECT  50.437 2.016 51.008 6.216 ;
     RECT  50.773 7.44 51.008 13.416 ;
     RECT  50.821 15.984 51.008 19.368 ;
     RECT  51.008 2.016 51.101 19.452 ;
     RECT  49.961 20.496 51.101 20.52 ;
     RECT  50.963 0.192 51.155 0.216 ;
     RECT  51.101 2.016 51.185 20.52 ;
     RECT  51.185 2.016 51.304 19.368 ;
     RECT  51.304 2.016 51.469 4.584 ;
     RECT  51.185 20.448 51.689 20.52 ;
     RECT  51.304 7.968 51.877 9.624 ;
     RECT  51.304 11.904 52.019 13.416 ;
     RECT  51.469 1.728 52.229 4.584 ;
     RECT  51.304 5.712 52.307 5.736 ;
     RECT  52.229 2.256 52.348 4.584 ;
     RECT  51.304 19.248 52.409 19.368 ;
     RECT  52.348 3.984 52.441 4.584 ;
     RECT  52.453 16.512 52.54 16.536 ;
     RECT  51.304 18.144 52.621 18.168 ;
     RECT  51.877 8.16 52.981 9.624 ;
     RECT  52.453 21.504 52.985 21.528 ;
     RECT  51.689 20.496 53.029 20.52 ;
     RECT  52.348 2.256 53.197 2.856 ;
     RECT  53.029 20.496 53.237 21.48 ;
     RECT  52.621 17.088 53.549 18.168 ;
     RECT  51.304 10.896 53.593 10.92 ;
     RECT  52.019 12.288 53.593 13.416 ;
     RECT  53.237 20.496 53.605 20.52 ;
     RECT  53.197 1.728 53.708 2.856 ;
     RECT  52.441 3.984 53.708 5.16 ;
     RECT  52.981 7.968 53.708 9.624 ;
     RECT  53.593 10.896 53.708 13.416 ;
     RECT  53.549 16.56 53.708 18.168 ;
     RECT  52.409 19.344 53.708 19.368 ;
     RECT  53.708 1.728 53.797 19.452 ;
     RECT  53.605 20.448 53.797 20.52 ;
     RECT  53.797 1.728 54.004 20.52 ;
     RECT  54.004 16.176 54.065 20.52 ;
     RECT  53.989 0.096 54.131 0.12 ;
     RECT  54.004 3.984 54.131 6.216 ;
     RECT  54.065 16.176 54.131 17.928 ;
     RECT  54.065 19.008 54.137 20.52 ;
     RECT  54.004 11.28 54.145 14.232 ;
     RECT  54.131 6.192 54.173 6.216 ;
     RECT  54.131 17.616 54.173 17.928 ;
     RECT  54.004 8.16 54.209 10.248 ;
     RECT  54.004 1.728 54.253 3 ;
     RECT  54.253 2.304 54.281 3 ;
     RECT  54.209 8.16 54.389 9.096 ;
     RECT  54.389 8.16 54.605 8.712 ;
     RECT  54.137 19.008 54.713 19.368 ;
     RECT  54.131 16.176 55.036 16.2 ;
     RECT  53.989 21.504 55.145 21.528 ;
     RECT  54.131 3.984 55.189 5.16 ;
     RECT  55.105 15.984 55.189 16.008 ;
     RECT  54.281 2.304 55.313 2.856 ;
     RECT  54.605 8.16 55.321 8.472 ;
     RECT  55.321 8.064 55.357 8.472 ;
     RECT  54.137 20.496 55.525 20.52 ;
     RECT  54.209 10.224 55.669 10.248 ;
     RECT  54.145 11.28 55.669 13.416 ;
     RECT  54.173 17.904 55.676 17.928 ;
     RECT  54.713 19.248 55.676 19.368 ;
     RECT  55.525 20.4 55.685 20.52 ;
     RECT  55.313 1.728 55.793 2.856 ;
     RECT  55.357 7.44 56.221 8.472 ;
     RECT  55.669 10.224 56.221 13.416 ;
     RECT  55.793 2.016 56.245 2.856 ;
     RECT  55.189 3.984 56.245 4.584 ;
     RECT  56.197 6.24 56.245 6.264 ;
     RECT  56.245 2.016 56.285 4.584 ;
     RECT  56.221 7.44 56.293 8.568 ;
     RECT  56.221 9.888 56.293 13.416 ;
     RECT  56.285 2.016 56.408 5.112 ;
     RECT  56.245 6.24 56.408 6.36 ;
     RECT  56.293 7.44 56.408 13.416 ;
     RECT  55.609 14.928 56.408 14.952 ;
     RECT  56.293 16.56 56.408 16.584 ;
     RECT  55.676 17.904 56.408 19.368 ;
     RECT  56.408 2.016 56.704 19.452 ;
     RECT  56.485 21.504 56.765 21.528 ;
     RECT  56.704 2.016 56.833 5.736 ;
     RECT  56.833 1.728 56.963 5.736 ;
     RECT  56.704 19.344 57.061 19.452 ;
     RECT  55.685 20.496 57.061 20.52 ;
     RECT  56.963 1.728 57.161 5.112 ;
     RECT  57.061 19.344 57.413 20.52 ;
     RECT  57.413 20.4 57.449 20.52 ;
     RECT  56.704 17.088 57.539 17.928 ;
     RECT  56.704 12 57.877 13.56 ;
     RECT  57.877 11.952 57.913 13.56 ;
     RECT  57.449 20.496 57.917 20.52 ;
     RECT  57.913 11.424 57.973 13.56 ;
     RECT  57.413 19.344 58.013 19.368 ;
     RECT  57.161 3.984 58.021 5.112 ;
     RECT  56.704 7.92 58.021 9.912 ;
     RECT  57.973 11.376 58.021 13.56 ;
     RECT  58.021 7.92 58.117 13.56 ;
     RECT  58.021 3.984 58.273 5.16 ;
     RECT  57.161 1.728 58.381 2.856 ;
     RECT  58.381 1.728 58.501 2.904 ;
     RECT  58.273 3.984 58.501 5.736 ;
     RECT  58.501 1.728 58.643 5.736 ;
     RECT  58.643 2.016 58.885 5.736 ;
     RECT  58.013 19.248 59.065 19.368 ;
     RECT  58.981 20.496 59.065 20.52 ;
     RECT  58.885 2.016 59.108 6.312 ;
     RECT  58.117 7.872 59.108 13.56 ;
     RECT  56.704 14.928 59.108 14.952 ;
     RECT  57.539 17.904 59.108 17.928 ;
     RECT  59.065 19.248 59.108 20.52 ;
     RECT  58.933 0.144 59.219 0.168 ;
     RECT  59.108 2.016 59.219 20.52 ;
     RECT  59.219 20.496 59.285 20.52 ;
     RECT  59.219 2.016 59.404 19.368 ;
     RECT  59.404 3.984 59.699 5.208 ;
     RECT  59.404 17.088 59.725 17.88 ;
     RECT  59.404 7.776 59.933 11.304 ;
     RECT  59.933 9.648 59.969 11.304 ;
     RECT  59.404 19.2 59.969 19.368 ;
     RECT  59.404 2.016 60.325 2.856 ;
     RECT  59.933 7.776 60.419 8.568 ;
     RECT  59.699 3.984 60.437 5.16 ;
     RECT  58.213 21.504 60.709 21.528 ;
     RECT  59.969 10.272 60.725 11.304 ;
     RECT  60.709 21.408 60.833 21.528 ;
     RECT  60.437 5.136 60.853 5.16 ;
     RECT  59.725 17.856 61.093 17.88 ;
     RECT  59.969 19.248 61.093 19.368 ;
     RECT  61.093 17.856 61.285 19.368 ;
     RECT  60.325 1.728 61.337 2.856 ;
     RECT  61.285 17.856 61.397 19.944 ;
     RECT  60.419 8.256 61.429 8.568 ;
     RECT  60.437 3.984 61.477 4.104 ;
     RECT  60.853 5.136 61.477 5.64 ;
     RECT  61.477 3.984 61.513 5.64 ;
     RECT  61.337 2.016 61.525 2.856 ;
     RECT  61.513 3.984 61.525 5.736 ;
     RECT  61.397 17.088 61.669 19.944 ;
     RECT  60.833 21.408 61.669 21.432 ;
     RECT  61.525 2.016 61.808 5.736 ;
     RECT  61.429 8.256 61.808 9.096 ;
     RECT  60.725 10.272 61.808 10.344 ;
     RECT  60.757 11.328 61.808 11.448 ;
     RECT  59.404 13.104 61.808 14.952 ;
     RECT  61.669 17.088 61.808 21.432 ;
     RECT  61.621 0.144 61.907 0.168 ;
     RECT  61.808 2.016 61.907 21.432 ;
     RECT  61.907 2.016 62.099 20.52 ;
     RECT  62.099 2.016 62.104 19.368 ;
     RECT  62.104 7.968 62.165 10.2 ;
     RECT  62.104 2.016 62.557 2.856 ;
     RECT  62.165 7.968 62.627 7.992 ;
     RECT  62.104 6.24 62.633 6.312 ;
     RECT  62.165 9.12 62.849 10.2 ;
     RECT  62.104 11.424 63.068 12.072 ;
     RECT  62.104 13.104 63.068 14.136 ;
     RECT  63.068 11.424 63.155 14.136 ;
     RECT  62.104 3.984 63.203 4.632 ;
     RECT  62.849 10.176 63.205 10.2 ;
     RECT  63.155 12 63.251 12.072 ;
     RECT  63.205 10.176 63.353 10.248 ;
     RECT  62.557 1.728 63.565 2.856 ;
     RECT  63.565 1.728 63.685 2.904 ;
     RECT  63.203 3.984 63.685 4.008 ;
     RECT  62.104 17.856 64.285 19.368 ;
     RECT  63.685 1.728 64.309 4.008 ;
     RECT  63.205 5.136 64.309 5.16 ;
     RECT  64.277 7.968 64.309 7.992 ;
     RECT  63.205 8.976 64.309 9 ;
     RECT  63.353 10.176 64.465 10.2 ;
     RECT  64.309 1.728 64.508 5.16 ;
     RECT  62.633 6.288 64.508 6.312 ;
     RECT  64.309 7.968 64.508 9 ;
     RECT  64.465 10.176 64.508 11.016 ;
     RECT  63.251 12 64.508 12.024 ;
     RECT  63.155 13.584 64.508 14.136 ;
     RECT  64.285 17.088 64.508 19.368 ;
     RECT  64.508 1.728 64.595 19.452 ;
     RECT  64.595 2.016 64.612 19.452 ;
     RECT  64.612 2.016 64.804 19.368 ;
     RECT  62.099 20.496 64.865 20.52 ;
     RECT  64.804 12 64.937 14.136 ;
     RECT  64.804 9.648 64.972 9.672 ;
     RECT  64.804 18.144 64.979 19.368 ;
     RECT  64.804 2.016 65.363 5.736 ;
     RECT  65.363 2.016 65.404 5.16 ;
     RECT  65.404 3.984 65.513 5.16 ;
     RECT  64.804 8.544 65.557 8.568 ;
     RECT  65.404 2.016 65.689 2.856 ;
     RECT  65.513 3.984 65.693 4.536 ;
     RECT  62.821 21.504 65.852 21.528 ;
     RECT  65.852 20.544 65.939 21.528 ;
     RECT  64.979 18.144 66.044 18.168 ;
     RECT  64.979 19.248 66.044 19.368 ;
     RECT  66.044 18.144 66.131 19.368 ;
     RECT  65.689 1.728 66.349 2.856 ;
     RECT  66.349 2.016 66.421 2.856 ;
     RECT  66.131 18.144 66.428 18.168 ;
     RECT  64.937 12.528 66.469 14.136 ;
     RECT  66.421 2.016 66.517 3 ;
     RECT  65.693 3.984 66.517 4.008 ;
     RECT  66.265 6.288 66.572 6.312 ;
     RECT  66.469 12.528 66.733 14.712 ;
     RECT  65.977 8.976 66.949 9 ;
     RECT  66.517 2.016 66.985 4.008 ;
     RECT  66.572 6.288 67.085 6.84 ;
     RECT  66.985 2.016 67.208 4.584 ;
     RECT  67.085 5.712 67.208 6.84 ;
     RECT  66.949 8.544 67.208 9 ;
     RECT  66.812 9.984 67.208 10.008 ;
     RECT  64.804 10.992 67.208 11.016 ;
     RECT  66.733 12.288 67.208 14.712 ;
     RECT  66.428 17.616 67.208 18.168 ;
     RECT  66.131 19.344 67.208 19.368 ;
     RECT  67.208 2.016 67.312 19.452 ;
     RECT  67.312 2.016 67.345 19.368 ;
     RECT  67.345 1.728 67.504 19.368 ;
     RECT  66.277 20.496 67.78 20.52 ;
     RECT  67.78 20.448 68.105 20.52 ;
     RECT  65.939 21.504 68.213 21.528 ;
     RECT  67.504 1.728 68.533 4.104 ;
     RECT  67.504 5.136 68.533 5.736 ;
     RECT  67.504 10.56 68.641 11.016 ;
     RECT  67.504 12.288 68.641 12.312 ;
     RECT  68.105 20.496 68.645 20.52 ;
     RECT  67.504 19.344 68.773 19.368 ;
     RECT  67.504 7.92 68.821 8.856 ;
     RECT  68.821 7.92 68.917 9.144 ;
     RECT  68.773 19.248 68.933 19.368 ;
     RECT  68.533 1.728 68.941 5.736 ;
     RECT  67.504 18.144 68.965 18.168 ;
     RECT  68.933 19.344 69.157 19.368 ;
     RECT  69.157 19.344 69.437 19.944 ;
     RECT  69.349 21.504 69.508 21.528 ;
     RECT  68.941 1.728 69.908 5.16 ;
     RECT  68.917 7.872 69.908 9.144 ;
     RECT  68.641 10.56 69.908 12.312 ;
     RECT  67.504 13.344 69.908 13.608 ;
     RECT  67.504 14.64 69.908 14.664 ;
     RECT  68.965 18.144 69.908 18.264 ;
     RECT  69.437 19.344 69.908 19.608 ;
     RECT  69.908 1.728 69.971 19.608 ;
     RECT  69.971 1.728 70.012 19.452 ;
     RECT  69.508 21.456 70.085 21.528 ;
     RECT  70.012 1.728 70.204 19.368 ;
     RECT  70.204 17.664 70.355 19.368 ;
     RECT  70.204 14.784 70.381 14.808 ;
     RECT  70.085 21.504 70.409 21.528 ;
     RECT  70.204 10.608 70.517 10.728 ;
     RECT  70.204 6.288 70.697 6.84 ;
     RECT  70.204 8.256 70.769 9.192 ;
     RECT  70.204 12.288 70.913 13.608 ;
     RECT  70.204 1.728 71.197 5.16 ;
     RECT  70.697 6.816 71.267 6.84 ;
     RECT  70.769 8.256 71.267 9.144 ;
     RECT  71.197 1.728 71.417 5.736 ;
     RECT  70.355 18.144 71.453 19.368 ;
     RECT  72.061 17.088 72.092 17.112 ;
     RECT  71.453 18.144 72.092 18.264 ;
     RECT  70.913 12.768 72.181 13.608 ;
     RECT  70.517 10.608 72.205 10.632 ;
     RECT  72.181 11.952 72.205 13.608 ;
     RECT  71.417 5.712 72.277 5.736 ;
     RECT  71.417 1.728 72.317 4.68 ;
     RECT  71.267 9.12 72.349 9.144 ;
     RECT  72.317 2.016 72.421 4.68 ;
     RECT  72.277 5.712 72.421 6.264 ;
     RECT  72.205 10.608 72.469 13.608 ;
     RECT  72.421 2.016 72.608 6.264 ;
     RECT  72.349 8.496 72.608 9.144 ;
     RECT  72.469 10.176 72.608 13.608 ;
     RECT  72.092 17.088 72.608 18.264 ;
     RECT  71.453 19.296 72.608 19.368 ;
     RECT  72.608 2.016 72.613 19.452 ;
     RECT  71.845 20.496 72.613 20.52 ;
     RECT  72.469 0.144 72.659 0.168 ;
     RECT  72.613 2.016 72.904 20.52 ;
     RECT  72.904 19.248 73.073 20.52 ;
     RECT  72.904 8.496 73.225 9.144 ;
     RECT  72.904 12.528 73.433 13.608 ;
     RECT  72.904 16.56 73.505 16.584 ;
     RECT  73.073 19.248 73.541 19.368 ;
     RECT  72.904 2.016 73.565 2.856 ;
     RECT  73.565 1.728 73.649 2.856 ;
     RECT  72.904 3.984 73.909 5.16 ;
     RECT  72.904 10.176 73.933 10.2 ;
     RECT  72.904 11.424 73.933 11.448 ;
     RECT  72.997 21.504 74.081 21.528 ;
     RECT  73.909 3.984 74.099 4.584 ;
     RECT  73.225 8.496 74.101 8.568 ;
     RECT  74.101 8.448 74.113 8.568 ;
     RECT  74.041 5.664 74.125 5.688 ;
     RECT  74.221 15.984 74.305 16.008 ;
     RECT  73.649 2.208 74.533 2.856 ;
     RECT  74.533 2.208 74.629 2.904 ;
     RECT  74.099 3.984 74.629 4.536 ;
     RECT  74.113 8.16 74.653 8.568 ;
     RECT  74.629 2.208 74.689 4.536 ;
     RECT  73.541 19.296 74.725 19.368 ;
     RECT  73.073 20.448 74.725 20.52 ;
     RECT  74.689 1.728 74.773 4.536 ;
     RECT  74.773 2.016 75.077 4.536 ;
     RECT  75.077 2.016 75.109 4.68 ;
     RECT  74.581 5.712 75.109 5.928 ;
     RECT  74.653 8.16 75.229 9.144 ;
     RECT  73.933 10.176 75.229 11.448 ;
     RECT  75.109 2.016 75.308 5.928 ;
     RECT  75.229 8.16 75.308 11.448 ;
     RECT  73.433 12.768 75.308 13.608 ;
     RECT  72.904 18.144 75.308 18.168 ;
     RECT  74.725 19.296 75.308 20.52 ;
     RECT  75.308 2.016 75.604 20.52 ;
     RECT  75.301 21.504 75.701 21.528 ;
     RECT  75.604 12.528 75.827 13.8 ;
     RECT  75.604 2.016 75.985 2.856 ;
     RECT  75.604 18.144 76.205 20.52 ;
     RECT  76.205 18.144 76.313 19.944 ;
     RECT  75.604 3.984 76.421 5.688 ;
     RECT  75.827 13.296 76.643 13.8 ;
     RECT  75.604 7.44 76.681 11.016 ;
     RECT  75.604 16.56 76.781 16.584 ;
     RECT  76.681 9.696 76.789 11.016 ;
     RECT  76.643 13.296 76.835 13.704 ;
     RECT  76.789 9.696 76.837 11.16 ;
     RECT  76.835 13.296 76.877 13.608 ;
     RECT  76.313 19.248 76.889 19.944 ;
     RECT  76.889 19.248 76.925 19.368 ;
     RECT  76.681 7.44 76.931 8.52 ;
     RECT  76.837 9.696 76.997 11.448 ;
     RECT  77.029 21.504 77.177 21.528 ;
     RECT  76.421 3.984 77.389 5.64 ;
     RECT  77.389 3.984 77.569 5.688 ;
     RECT  75.985 1.728 77.605 2.856 ;
     RECT  76.313 18.144 77.605 18.168 ;
     RECT  77.605 1.728 77.653 2.904 ;
     RECT  77.569 3.984 77.653 5.736 ;
     RECT  77.653 1.728 77.713 5.736 ;
     RECT  76.877 12.528 77.797 13.608 ;
     RECT  77.605 18.144 77.821 18.264 ;
     RECT  77.713 1.728 77.845 6.312 ;
     RECT  77.797 12.528 77.852 13.704 ;
     RECT  77.852 12.528 77.893 13.8 ;
     RECT  76.925 19.296 77.929 19.368 ;
     RECT  77.845 1.728 78.008 6.744 ;
     RECT  76.931 7.968 78.008 8.52 ;
     RECT  76.997 9.696 78.008 10.872 ;
     RECT  77.893 11.952 78.008 13.8 ;
     RECT  77.821 17.664 78.008 18.264 ;
     RECT  77.929 19.296 78.008 19.608 ;
     RECT  78.008 1.728 78.181 19.608 ;
     RECT  78.181 1.728 78.304 19.944 ;
     RECT  78.304 19.248 78.373 19.944 ;
     RECT  78.373 19.248 78.509 20.52 ;
     RECT  78.304 7.44 78.545 10.728 ;
     RECT  78.545 7.44 78.625 10.392 ;
     RECT  78.625 8.448 78.659 10.392 ;
     RECT  78.659 8.448 78.899 9.336 ;
     RECT  78.625 7.44 79.273 7.464 ;
     RECT  78.304 1.728 79.669 5.736 ;
     RECT  78.304 17.952 79.676 18.168 ;
     RECT  78.509 19.248 79.676 19.368 ;
     RECT  78.899 8.448 79.765 8.808 ;
     RECT  78.757 21.504 79.913 21.528 ;
     RECT  78.659 10.368 79.945 10.392 ;
     RECT  79.765 7.968 80.485 8.808 ;
     RECT  79.945 10.368 80.485 10.632 ;
     RECT  78.304 11.952 80.485 11.976 ;
     RECT  80.485 7.968 80.581 11.976 ;
     RECT  78.304 13.44 80.593 13.608 ;
     RECT  79.676 17.952 80.629 19.368 ;
     RECT  78.509 20.496 80.629 20.52 ;
     RECT  79.669 1.728 80.708 5.832 ;
     RECT  80.581 7.92 80.708 11.976 ;
     RECT  80.593 13.344 80.708 13.608 ;
     RECT  80.629 17.952 80.708 20.52 ;
     RECT  80.708 1.728 81.004 20.52 ;
     RECT  81.004 7.44 81.065 9.624 ;
     RECT  81.004 15.984 81.217 16.584 ;
     RECT  81.004 17.952 81.281 20.52 ;
     RECT  81.217 16.56 81.491 16.584 ;
     RECT  81.004 10.608 81.539 14.376 ;
     RECT  81.539 10.608 81.818 14.328 ;
     RECT  81.281 17.952 81.821 19.944 ;
     RECT  81.818 10.608 81.965 14.28 ;
     RECT  81.965 12.576 82.067 14.28 ;
     RECT  81.065 7.44 82.165 9.528 ;
     RECT  81.965 10.608 82.165 11.256 ;
     RECT  82.165 7.44 82.225 11.256 ;
     RECT  81.004 5.712 82.277 5.736 ;
     RECT  82.225 7.872 82.297 11.256 ;
     RECT  82.297 10.848 82.355 11.256 ;
     RECT  82.277 5.712 82.361 6.264 ;
     RECT  82.361 5.712 82.403 5.736 ;
     RECT  81.004 1.728 82.444 4.536 ;
     RECT  82.444 3.984 82.556 4.536 ;
     RECT  81.821 17.952 82.789 19.368 ;
     RECT  82.355 11.136 82.94 11.256 ;
     RECT  82.067 12.576 82.94 13.608 ;
     RECT  82.94 11.136 83.125 13.608 ;
     RECT  83.125 11.136 83.221 13.704 ;
     RECT  82.444 1.728 83.408 2.856 ;
     RECT  82.556 3.984 83.408 5.592 ;
     RECT  82.297 7.872 83.408 9.72 ;
     RECT  83.221 11.136 83.408 14.424 ;
     RECT  82.789 17.952 83.408 19.944 ;
     RECT  83.269 21.504 83.411 21.528 ;
     RECT  83.408 1.728 83.704 19.944 ;
     RECT  83.704 3.984 83.837 5.592 ;
     RECT  83.704 9.504 83.837 9.672 ;
     RECT  83.704 11.232 84.053 13.32 ;
     RECT  83.704 17.952 84.233 19.944 ;
     RECT  83.704 7.968 84.697 8.52 ;
     RECT  83.704 14.928 84.773 14.952 ;
     RECT  84.517 21.504 84.845 21.528 ;
     RECT  84.697 7.968 84.889 8.568 ;
     RECT  84.233 17.952 84.947 19.368 ;
     RECT  84.889 8.208 85.021 8.568 ;
     RECT  83.837 9.648 85.021 9.672 ;
     RECT  85.021 8.208 85.061 9.672 ;
     RECT  84.053 11.232 85.165 11.448 ;
     RECT  84.053 12.48 85.165 13.32 ;
     RECT  83.837 3.984 85.273 5.16 ;
     RECT  83.704 1.728 85.285 2.856 ;
     RECT  85.273 3.984 85.285 5.736 ;
     RECT  84.947 17.952 85.285 17.976 ;
     RECT  85.285 1.728 85.429 2.904 ;
     RECT  85.285 3.984 85.429 5.928 ;
     RECT  85.429 1.728 85.529 5.928 ;
     RECT  85.093 20.496 85.669 20.52 ;
     RECT  85.669 20.448 86.053 20.52 ;
     RECT  85.529 2.016 86.108 5.928 ;
     RECT  85.061 8.208 86.108 9.288 ;
     RECT  85.165 11.232 86.108 13.32 ;
     RECT  84.913 14.832 86.108 14.856 ;
     RECT  85.285 16.992 86.108 17.976 ;
     RECT  84.947 19.344 86.108 19.368 ;
     RECT  86.108 2.016 86.404 19.452 ;
     RECT  86.404 18.768 86.417 19.452 ;
     RECT  86.053 20.448 86.417 21.432 ;
     RECT  86.245 0.144 86.437 0.168 ;
     RECT  86.417 18.768 86.501 21.432 ;
     RECT  86.437 0.144 86.531 0.264 ;
     RECT  86.404 2.016 86.531 6.84 ;
     RECT  86.404 11.424 86.531 13.32 ;
     RECT  86.501 20.448 86.531 21.432 ;
     RECT  86.501 18.768 86.537 19.368 ;
     RECT  86.531 5.088 86.545 6.84 ;
     RECT  86.404 8.208 86.545 9.672 ;
     RECT  86.531 0.24 86.579 0.264 ;
     RECT  86.531 2.016 86.629 4.008 ;
     RECT  86.545 9.264 86.681 9.672 ;
     RECT  86.404 17.136 86.753 17.64 ;
     RECT  86.545 5.712 87.049 6.84 ;
     RECT  87.049 5.712 87.107 6.312 ;
     RECT  86.531 20.448 87.149 20.52 ;
     RECT  86.753 17.136 87.155 17.544 ;
     RECT  87.107 5.712 87.587 5.736 ;
     RECT  86.531 13.296 87.613 13.32 ;
     RECT  86.629 1.728 87.628 4.008 ;
     RECT  87.613 13.296 87.713 13.704 ;
     RECT  86.531 11.424 87.733 11.976 ;
     RECT  86.681 9.648 87.781 9.672 ;
     RECT  87.713 13.296 87.797 13.8 ;
     RECT  87.781 9.648 87.827 10.2 ;
     RECT  87.628 3.984 87.829 4.008 ;
     RECT  86.545 8.208 87.829 8.232 ;
     RECT  87.827 10.176 87.937 10.2 ;
     RECT  87.733 11.328 87.937 11.976 ;
     RECT  86.537 19.344 87.973 19.368 ;
     RECT  87.829 7.44 87.98 8.232 ;
     RECT  87.155 17.52 88.117 17.544 ;
     RECT  87.149 20.496 88.549 20.52 ;
     RECT  87.973 18.768 88.721 19.368 ;
     RECT  88.549 20.448 88.721 20.52 ;
     RECT  88.721 18.768 88.805 20.52 ;
     RECT  87.628 1.728 88.808 2.856 ;
     RECT  87.829 3.984 88.808 5.16 ;
     RECT  87.98 7.44 88.808 9.192 ;
     RECT  87.937 10.176 88.808 11.976 ;
     RECT  87.797 13.296 88.808 13.704 ;
     RECT  88.117 17.52 88.808 17.688 ;
     RECT  88.805 18.768 88.808 19.452 ;
     RECT  88.808 1.728 88.912 19.452 ;
     RECT  88.912 1.728 89.104 19.368 ;
     RECT  89.125 0.096 89.267 0.12 ;
     RECT  87.397 21.504 89.267 21.528 ;
     RECT  89.104 17.664 89.273 17.688 ;
     RECT  89.104 5.712 89.281 5.736 ;
     RECT  89.104 1.728 89.308 4.584 ;
     RECT  89.104 18.768 89.345 19.368 ;
     RECT  89.104 9.696 90.205 10.2 ;
     RECT  89.104 11.232 90.205 11.256 ;
     RECT  88.805 20.496 90.244 20.52 ;
     RECT  89.308 1.728 90.269 2.856 ;
     RECT  90.269 1.728 90.325 2.904 ;
     RECT  89.308 3.984 90.325 4.584 ;
     RECT  90.241 6.288 90.371 6.312 ;
     RECT  90.325 1.728 90.421 4.584 ;
     RECT  90.421 1.728 90.461 5.16 ;
     RECT  90.461 3.984 90.524 5.16 ;
     RECT  89.104 7.92 90.524 8.712 ;
     RECT  90.205 9.696 90.524 11.256 ;
     RECT  90.524 7.92 90.901 11.256 ;
     RECT  90.661 21.504 90.965 21.528 ;
     RECT  89.345 19.344 91.393 19.368 ;
     RECT  90.244 20.448 91.393 20.52 ;
     RECT  90.461 1.728 91.508 2.856 ;
     RECT  90.524 3.984 91.508 5.688 ;
     RECT  91.333 6.816 91.508 6.84 ;
     RECT  90.901 7.872 91.508 11.256 ;
     RECT  89.104 13.104 91.508 13.704 ;
     RECT  91.321 15.984 91.508 16.008 ;
     RECT  91.393 19.344 91.508 20.52 ;
     RECT  91.508 1.728 91.804 20.52 ;
     RECT  91.804 1.728 92.081 9.672 ;
     RECT  91.804 11.136 92.092 13.704 ;
     RECT  92.005 21.504 92.189 21.528 ;
     RECT  91.804 17.952 92.621 20.52 ;
     RECT  92.081 1.728 92.665 6.264 ;
     RECT  92.665 2.256 92.701 6.264 ;
     RECT  91.804 15.408 92.729 15.432 ;
     RECT  92.701 2.256 92.754 5.736 ;
     RECT  92.081 7.44 92.869 9.672 ;
     RECT  92.092 11.136 92.869 11.976 ;
     RECT  92.869 7.44 93.155 11.976 ;
     RECT  93.155 7.44 93.205 9.864 ;
     RECT  93.155 11.136 93.445 11.976 ;
     RECT  92.092 13.104 93.445 13.704 ;
     RECT  92.754 2.304 93.725 5.736 ;
     RECT  93.725 1.728 94.208 5.736 ;
     RECT  93.205 7.728 94.208 9.864 ;
     RECT  93.445 11.136 94.208 13.704 ;
     RECT  92.621 17.952 94.208 17.976 ;
     RECT  92.621 19.344 94.208 20.52 ;
     RECT  94.208 1.728 94.309 20.52 ;
     RECT  93.157 21.504 94.309 21.528 ;
     RECT  94.309 1.728 94.385 21.528 ;
     RECT  94.385 1.728 94.504 21.48 ;
     RECT  94.504 19.296 94.601 21.48 ;
     RECT  94.601 19.296 94.637 20.52 ;
     RECT  94.504 3.936 94.673 6.312 ;
     RECT  94.504 10.848 94.673 11.16 ;
     RECT  94.504 7.728 94.781 9.528 ;
     RECT  94.673 10.848 95.075 10.872 ;
     RECT  94.637 19.296 95.177 19.368 ;
     RECT  94.504 1.728 95.357 2.856 ;
     RECT  94.673 3.984 95.411 6.312 ;
     RECT  94.504 17.904 95.429 17.928 ;
     RECT  95.411 3.984 95.501 6.264 ;
     RECT  94.781 7.968 95.605 9.528 ;
     RECT  95.569 10.704 95.605 10.728 ;
     RECT  94.637 20.448 95.609 20.52 ;
     RECT  95.357 2.256 95.617 2.856 ;
     RECT  95.177 19.344 96.209 19.368 ;
     RECT  95.605 7.968 96.277 10.728 ;
     RECT  96.277 7.872 96.361 10.728 ;
     RECT  95.609 20.496 96.613 20.52 ;
     RECT  95.617 2.304 96.757 2.856 ;
     RECT  96.209 19.248 96.764 19.368 ;
     RECT  96.613 20.448 96.764 20.52 ;
     RECT  96.757 2.256 96.793 2.856 ;
     RECT  96.793 1.728 96.908 2.856 ;
     RECT  95.501 3.984 96.908 5.688 ;
     RECT  96.361 7.44 96.908 10.728 ;
     RECT  94.504 12.192 96.908 13.704 ;
     RECT  96.505 16.56 96.908 16.584 ;
     RECT  96.109 17.664 96.908 17.688 ;
     RECT  96.764 19.248 96.908 20.52 ;
     RECT  96.908 1.728 97.204 20.52 ;
     RECT  97.204 1.728 97.237 10.728 ;
     RECT  97.204 19.248 97.273 20.52 ;
     RECT  96.997 21.504 97.301 21.528 ;
     RECT  97.204 11.904 97.331 13.704 ;
     RECT  97.237 2.304 97.589 10.728 ;
     RECT  97.589 2.304 97.715 10.632 ;
     RECT  97.715 2.304 97.849 6.312 ;
     RECT  97.715 7.44 97.957 10.632 ;
     RECT  97.849 3.936 97.996 6.312 ;
     RECT  97.957 7.488 98.003 10.632 ;
     RECT  97.204 16.512 98.051 18.264 ;
     RECT  98.003 7.488 98.065 9.144 ;
     RECT  98.051 16.512 98.165 17.496 ;
     RECT  97.996 5.712 98.209 6.312 ;
     RECT  97.331 11.904 98.293 12.024 ;
     RECT  97.331 13.104 98.293 13.704 ;
     RECT  97.849 2.304 98.305 2.904 ;
     RECT  97.273 20.496 98.345 20.52 ;
     RECT  98.293 11.904 98.38 13.704 ;
     RECT  98.305 1.728 98.389 2.904 ;
     RECT  98.389 2.256 98.453 2.904 ;
     RECT  97.273 19.248 98.725 19.368 ;
     RECT  98.453 2.304 98.821 2.904 ;
     RECT  97.996 3.936 98.821 4.536 ;
     RECT  98.065 7.968 99.061 9.144 ;
     RECT  98.003 10.608 99.061 10.632 ;
     RECT  98.821 2.304 99.097 4.536 ;
     RECT  99.061 10.32 99.125 10.632 ;
     RECT  98.38 11.904 99.125 11.976 ;
     RECT  98.209 5.712 99.277 6.264 ;
     RECT  98.165 17.088 99.301 17.496 ;
     RECT  98.725 18.624 99.301 19.368 ;
     RECT  99.097 2.304 99.421 4.584 ;
     RECT  99.301 17.088 99.452 19.368 ;
     RECT  99.277 5.712 99.485 6.312 ;
     RECT  99.061 7.44 99.485 9.144 ;
     RECT  99.421 1.728 99.493 4.584 ;
     RECT  99.485 5.712 99.493 9.144 ;
     RECT  99.493 1.728 99.608 9.144 ;
     RECT  99.125 10.32 99.608 11.976 ;
     RECT  98.38 13.104 99.608 13.704 ;
     RECT  99.452 17.088 99.608 19.992 ;
     RECT  99.608 1.728 99.731 19.992 ;
     RECT  99.731 1.728 99.904 19.368 ;
     RECT  99.904 18.816 100.307 19.368 ;
     RECT  99.904 1.728 100.361 10.344 ;
     RECT  100.361 3.984 100.883 10.344 ;
     RECT  100.645 21.504 101.189 21.528 ;
     RECT  100.883 9.696 101.219 10.344 ;
     RECT  99.904 17.616 101.329 17.64 ;
     RECT  101.329 17.616 101.413 18.264 ;
     RECT  100.307 19.296 101.413 19.368 ;
     RECT  99.904 11.904 101.761 11.976 ;
     RECT  100.361 1.728 101.843 3 ;
     RECT  102.085 0.24 102.133 0.264 ;
     RECT  101.843 2.148 102.181 3 ;
     RECT  100.883 3.984 102.181 8.664 ;
     RECT  101.219 10.32 102.181 10.344 ;
     RECT  101.761 11.76 102.181 11.976 ;
     RECT  101.413 17.616 102.181 19.368 ;
     RECT  99.877 20.496 102.181 20.52 ;
     RECT  102.181 2.148 102.308 8.664 ;
     RECT  102.181 10.32 102.308 11.976 ;
     RECT  99.904 13.68 102.308 13.704 ;
     RECT  102.181 17.616 102.308 20.52 ;
     RECT  102.133 0.144 102.419 0.264 ;
     RECT  102.308 2.148 102.604 20.52 ;
     RECT  102.419 0.24 102.611 0.264 ;
     RECT  102.604 18.768 102.611 20.52 ;
     RECT  102.604 2.148 102.947 9.816 ;
     RECT  102.947 2.148 102.961 7.272 ;
     RECT  102.961 2.148 102.995 5.16 ;
     RECT  102.604 10.848 102.995 13.752 ;
     RECT  102.995 2.148 103.084 4.872 ;
     RECT  102.947 8.448 103.091 9.816 ;
     RECT  102.995 10.848 103.091 13.704 ;
     RECT  102.961 6.288 103.132 7.272 ;
     RECT  103.091 10.848 103.205 12.552 ;
     RECT  103.084 2.148 103.309 4.584 ;
     RECT  103.205 10.848 103.313 10.968 ;
     RECT  103.313 10.848 103.385 10.872 ;
     RECT  103.091 8.448 103.564 8.568 ;
     RECT  103.132 6.288 103.753 6.888 ;
     RECT  103.717 0.096 103.859 0.12 ;
     RECT  103.091 9.792 103.885 9.816 ;
     RECT  103.885 9.792 103.925 9.96 ;
     RECT  103.309 1.728 104.053 4.584 ;
     RECT  103.564 8.544 104.065 8.568 ;
     RECT  103.717 21.504 104.105 21.528 ;
     RECT  104.053 1.728 104.173 4.872 ;
     RECT  103.753 6.864 104.245 6.888 ;
     RECT  103.091 13.68 104.348 13.704 ;
     RECT  103.205 11.952 104.492 12.552 ;
     RECT  103.925 9.936 104.533 9.96 ;
     RECT  104.492 11.328 104.533 12.552 ;
     RECT  104.065 8.544 104.581 8.616 ;
     RECT  104.245 6.864 104.605 7.272 ;
     RECT  104.581 8.496 104.605 8.616 ;
     RECT  104.605 6.864 104.677 8.616 ;
     RECT  104.677 6.864 104.725 8.664 ;
     RECT  102.611 18.768 104.869 19.368 ;
     RECT  102.611 20.496 104.869 20.52 ;
     RECT  104.173 1.728 105.008 5.736 ;
     RECT  104.725 6.768 105.008 8.664 ;
     RECT  104.533 9.936 105.008 12.552 ;
     RECT  104.348 13.536 105.008 13.704 ;
     RECT  104.204 15.072 105.008 15.096 ;
     RECT  102.604 17.616 105.008 17.64 ;
     RECT  104.869 18.768 105.008 20.52 ;
     RECT  105.008 1.728 105.061 20.52 ;
     RECT  105.061 1.728 105.304 21.432 ;
     RECT  105.304 18.768 105.437 21.432 ;
     RECT  105.437 20.496 105.443 21.432 ;
     RECT  105.304 13.68 105.445 13.704 ;
     RECT  105.304 10.272 105.581 12.072 ;
     RECT  105.637 21.504 105.905 21.528 ;
     RECT  105.304 7.44 105.964 9 ;
     RECT  105.304 1.728 106.337 6.312 ;
     RECT  105.437 18.768 106.445 19.368 ;
     RECT  105.581 11.952 106.536 12.072 ;
     RECT  106.501 13.104 106.536 13.128 ;
     RECT  106.536 11.952 106.661 13.128 ;
     RECT  106.661 11.952 106.697 12.6 ;
     RECT  105.443 20.496 106.769 20.52 ;
     RECT  106.445 19.344 106.789 19.368 ;
     RECT  105.581 10.272 107.017 10.92 ;
     RECT  105.304 17.616 107.173 17.64 ;
     RECT  106.337 1.728 107.317 2.904 ;
     RECT  106.337 3.984 107.317 6.312 ;
     RECT  107.317 1.728 107.557 6.312 ;
     RECT  105.964 7.44 107.557 8.904 ;
     RECT  106.789 19.344 107.557 19.944 ;
     RECT  107.557 1.728 107.665 8.904 ;
     RECT  107.017 10.272 107.665 11.256 ;
     RECT  107.665 1.728 107.708 11.256 ;
     RECT  106.697 12.336 107.708 12.6 ;
     RECT  107.173 17.616 107.708 18.264 ;
     RECT  107.557 19.248 107.708 19.944 ;
     RECT  107.708 1.728 107.749 19.944 ;
     RECT  107.749 1.728 107.993 20.52 ;
     RECT  107.993 1.728 108.004 19.368 ;
     RECT  108.004 1.728 108.131 7.368 ;
     RECT  108.131 4.512 108.173 7.368 ;
     RECT  108.004 8.544 108.173 13.08 ;
     RECT  108.131 1.728 108.179 3.24 ;
     RECT  108.173 8.544 108.275 11.976 ;
     RECT  108.173 4.56 109.009 7.368 ;
     RECT  109.009 7.344 109.109 7.368 ;
     RECT  108.179 1.728 109.189 2.856 ;
     RECT  108.004 17.088 109.235 17.448 ;
     RECT  109.189 1.728 109.285 2.952 ;
     RECT  109.645 7.44 109.717 7.464 ;
     RECT  108.004 19.344 109.861 19.368 ;
     RECT  108.275 9.072 109.897 11.976 ;
     RECT  108.173 13.056 109.897 13.08 ;
     RECT  109.235 17.424 110.053 17.448 ;
     RECT  109.285 1.728 110.077 3.24 ;
     RECT  109.009 4.56 110.077 6.264 ;
     RECT  110.077 1.728 110.141 6.264 ;
     RECT  109.717 7.44 110.185 7.896 ;
     RECT  109.897 9.072 110.185 13.08 ;
     RECT  110.141 1.728 110.245 6.312 ;
     RECT  110.185 7.44 110.245 13.08 ;
     RECT  110.245 1.728 110.408 13.08 ;
     RECT  110.053 17.424 110.408 18.264 ;
     RECT  109.861 19.248 110.408 19.368 ;
     RECT  110.408 1.728 110.437 19.452 ;
     RECT  107.993 20.496 110.437 20.52 ;
     RECT  110.293 0.144 110.483 0.168 ;
     RECT  110.437 1.728 110.585 20.52 ;
     RECT  110.585 1.728 110.704 19.368 ;
     RECT  110.704 11.424 110.765 12.552 ;
     RECT  110.704 1.728 110.963 10.392 ;
     RECT  110.963 1.728 111.059 5.112 ;
     RECT  110.765 11.424 111.059 11.448 ;
     RECT  110.963 6.24 111.155 10.392 ;
     RECT  111.155 6.24 111.169 7.368 ;
     RECT  111.169 6.288 111.521 7.368 ;
     RECT  111.155 8.832 111.557 10.392 ;
     RECT  110.765 12.528 111.913 12.552 ;
     RECT  111.913 12.528 111.997 12.648 ;
     RECT  111.059 2.208 112.057 5.112 ;
     RECT  110.585 20.496 112.165 20.52 ;
     RECT  108.517 21.504 112.165 21.528 ;
     RECT  112.165 20.496 112.169 21.528 ;
     RECT  112.057 1.728 112.211 5.112 ;
     RECT  112.169 20.496 112.493 21.48 ;
     RECT  111.521 6.288 112.549 6.888 ;
     RECT  112.211 2.148 112.561 5.112 ;
     RECT  112.549 6.288 112.561 7.272 ;
     RECT  111.557 9.12 112.669 10.392 ;
     RECT  110.704 19.344 112.733 19.368 ;
     RECT  110.704 17.424 112.741 17.448 ;
     RECT  112.733 19.248 112.741 19.368 ;
     RECT  112.669 8.544 112.885 10.392 ;
     RECT  112.489 11.424 112.885 11.448 ;
     RECT  111.997 12.528 112.885 12.552 ;
     RECT  112.561 2.148 112.981 7.272 ;
     RECT  112.885 8.352 112.981 10.392 ;
     RECT  112.885 11.424 112.981 12.552 ;
     RECT  112.741 17.424 112.993 19.368 ;
     RECT  112.493 20.496 112.993 20.52 ;
     RECT  112.981 2.148 113.108 12.552 ;
     RECT  112.261 13.632 113.108 13.656 ;
     RECT  111.941 14.832 113.108 14.856 ;
     RECT  112.993 17.424 113.108 20.52 ;
     RECT  112.885 0.144 113.171 0.168 ;
     RECT  113.108 2.148 113.245 20.52 ;
     RECT  113.245 1.728 113.363 20.52 ;
     RECT  113.363 2.256 113.404 19.368 ;
     RECT  113.404 2.256 113.501 8.568 ;
     RECT  113.501 2.304 113.884 8.568 ;
     RECT  113.404 19.248 113.969 19.368 ;
     RECT  113.884 3.984 114.077 8.568 ;
     RECT  113.404 10.704 114.461 10.968 ;
     RECT  114.077 7.872 114.469 8.568 ;
     RECT  113.404 9.648 114.469 9.72 ;
     RECT  114.469 7.872 114.476 9.72 ;
     RECT  114.461 10.704 114.476 11.448 ;
     RECT  113.884 2.304 114.517 2.904 ;
     RECT  114.476 7.872 114.545 11.448 ;
     RECT  114.277 21.504 114.545 21.528 ;
     RECT  114.545 7.872 114.563 10.872 ;
     RECT  114.517 2.208 114.649 2.904 ;
     RECT  114.563 7.872 114.797 9.72 ;
     RECT  114.649 1.728 114.901 2.904 ;
     RECT  114.077 3.984 114.901 6.888 ;
     RECT  113.404 12.528 114.908 12.552 ;
     RECT  114.908 11.952 114.949 12.552 ;
     RECT  113.969 19.344 115.004 19.368 ;
     RECT  114.901 1.728 115.301 6.888 ;
     RECT  113.363 20.496 115.517 20.52 ;
     RECT  115.301 2.016 115.669 6.888 ;
     RECT  114.797 7.872 115.669 8.568 ;
     RECT  115.669 2.016 115.808 8.568 ;
     RECT  114.797 9.696 115.808 9.72 ;
     RECT  114.563 10.704 115.808 10.872 ;
     RECT  114.949 11.952 115.808 13.128 ;
     RECT  115.004 18.816 115.808 19.368 ;
     RECT  115.813 21.504 115.985 21.528 ;
     RECT  115.808 2.016 116.005 19.452 ;
     RECT  116.005 2.016 116.051 19.56 ;
     RECT  116.051 2.418 116.104 19.56 ;
     RECT  116.104 19.536 116.237 19.56 ;
     RECT  116.104 2.688 116.243 2.712 ;
     RECT  116.104 4.656 116.243 5.112 ;
     RECT  116.104 7.44 116.243 7.8 ;
     RECT  116.104 9.264 116.243 9.288 ;
     RECT  116.243 5.088 116.245 5.112 ;
     RECT  116.243 7.776 116.281 7.8 ;
     RECT  118.508 2.148 118.612 19.452 ;
     RECT  118.612 2.418 118.804 19.182 ;
     RECT  121.208 2.148 121.312 19.452 ;
     RECT  121.312 2.418 121.504 19.182 ;
     RECT  123.908 2.148 124.012 19.452 ;
     RECT  124.012 2.418 124.204 19.182 ;
     RECT  126.608 2.148 126.712 19.452 ;
     RECT  126.712 2.418 126.904 19.182 ;
    LAYER M5 ;
     RECT  13.488 0.016 116.04 2.137 ;
     RECT  2.4 2.137 2.52 2.151 ;
     RECT  5.1 2.137 5.22 2.151 ;
     RECT  7.8 2.137 7.92 2.151 ;
     RECT  10.5 2.137 10.62 2.151 ;
     RECT  13.2 2.137 116.04 2.151 ;
     RECT  118.5 2.137 118.62 2.151 ;
     RECT  121.2 2.137 121.32 2.151 ;
     RECT  123.9 2.137 124.02 2.151 ;
     RECT  126.6 2.137 126.72 2.151 ;
     RECT  13.2 2.151 116.112 2.677 ;
     RECT  13.2 2.677 116.232 4.019 ;
     RECT  13.2 4.019 65.544 4.595 ;
     RECT  66.528 4.019 116.232 4.595 ;
     RECT  13.2 4.595 60.264 5.171 ;
     RECT  61.344 4.595 65.544 5.171 ;
     RECT  66.528 4.595 71.256 5.171 ;
     RECT  61.344 5.171 62.52 5.605 ;
     RECT  13.2 5.171 54.504 5.747 ;
     RECT  66.528 5.171 68.904 5.747 ;
     RECT  69.9 5.171 71.256 5.747 ;
     RECT  60.864 5.605 62.52 6.229 ;
     RECT  72.336 4.595 116.232 6.229 ;
     RECT  55.536 5.171 59.784 6.323 ;
     RECT  63.696 5.171 65.544 6.323 ;
     RECT  66.528 5.747 67.512 6.323 ;
     RECT  72.288 6.229 116.232 6.323 ;
     RECT  69.9 5.747 71.112 6.805 ;
     RECT  66.624 6.323 67.512 6.851 ;
     RECT  104.064 6.323 116.232 6.899 ;
     RECT  72.288 6.323 103.08 7.475 ;
     RECT  58.992 6.323 59.784 7.765 ;
     RECT  60.864 6.229 62.616 7.765 ;
     RECT  55.536 6.323 58.008 7.861 ;
     RECT  58.992 7.765 62.616 7.861 ;
     RECT  69.9 6.805 71.256 7.861 ;
     RECT  67.2 6.851 67.512 7.909 ;
     RECT  68.928 7.861 71.256 7.909 ;
     RECT  13.2 5.747 51.864 7.957 ;
     RECT  13.104 7.957 51.864 8.003 ;
     RECT  55.536 7.861 62.616 8.003 ;
     RECT  104.256 6.899 111.144 8.003 ;
     RECT  13.104 8.003 51.576 8.099 ;
     RECT  55.536 8.003 62.112 8.099 ;
     RECT  52.848 5.747 54.504 8.149 ;
     RECT  67.2 7.909 71.256 8.291 ;
     RECT  87.984 7.475 103.08 8.437 ;
     RECT  104.256 8.003 111.096 8.437 ;
     RECT  13.104 8.099 51.528 8.579 ;
     RECT  64.32 6.323 65.544 8.579 ;
     RECT  67.2 8.291 71.064 8.579 ;
     RECT  87.984 8.437 111.096 8.627 ;
     RECT  87.984 8.627 103.512 8.675 ;
     RECT  52.848 8.149 54.552 8.723 ;
     RECT  87.984 8.675 101.208 8.723 ;
     RECT  52.848 8.723 54.12 8.819 ;
     RECT  72.288 7.475 87 8.819 ;
     RECT  67.2 8.579 70.212 8.867 ;
     RECT  67.2 8.867 67.512 8.965 ;
     RECT  104.592 8.627 111.096 9.011 ;
     RECT  55.584 8.099 62.112 9.109 ;
     RECT  13.104 8.579 45.912 9.155 ;
     RECT  68.928 8.867 70.212 9.155 ;
     RECT  72.288 8.819 78.888 9.155 ;
     RECT  90.24 8.723 101.208 9.155 ;
     RECT  112.176 6.899 116.232 9.299 ;
     RECT  74.064 9.155 78.888 9.347 ;
     RECT  13.104 9.155 41.016 9.635 ;
     RECT  64.32 8.579 64.812 9.637 ;
     RECT  80.496 8.819 87 9.637 ;
     RECT  87.984 8.723 89.112 9.637 ;
     RECT  55.584 9.109 62.808 9.683 ;
     RECT  13.104 9.635 33.528 9.731 ;
     RECT  90.24 9.155 97.992 9.731 ;
     RECT  99.408 9.155 101.208 9.731 ;
     RECT  102.192 8.675 103.512 9.827 ;
     RECT  13.104 9.731 32.412 9.875 ;
     RECT  90.24 9.731 97.32 9.875 ;
     RECT  104.592 9.011 105.432 9.925 ;
     RECT  106.56 9.011 111.096 9.925 ;
     RECT  112.176 9.299 116.112 9.925 ;
     RECT  66.864 8.965 67.512 10.019 ;
     RECT  80.496 9.637 89.112 10.211 ;
     RECT  13.104 9.875 27.912 10.307 ;
     RECT  34.608 9.635 41.016 10.307 ;
     RECT  42.048 9.155 45.912 10.307 ;
     RECT  74.064 9.347 78.648 10.307 ;
     RECT  90.24 9.875 93.144 10.307 ;
     RECT  94.2 9.875 97.32 10.307 ;
     RECT  104.544 9.925 105.432 10.307 ;
     RECT  106.56 9.925 116.112 10.307 ;
     RECT  99.408 9.731 99.912 10.309 ;
     RECT  13.104 10.307 17.016 10.355 ;
     RECT  55.584 9.683 62.112 10.355 ;
     RECT  90.24 10.307 92.712 10.595 ;
     RECT  80.496 10.211 87 10.835 ;
     RECT  13.2 10.355 17.016 10.883 ;
     RECT  18 10.307 27.912 10.883 ;
     RECT  33.504 9.731 33.528 10.883 ;
     RECT  45.504 10.307 45.912 10.883 ;
     RECT  55.584 10.355 59.784 10.883 ;
     RECT  94.2 10.307 95.064 10.883 ;
     RECT  107.7 10.307 116.112 10.883 ;
     RECT  47.04 8.579 51.528 10.885 ;
     RECT  52.944 8.819 54.12 10.885 ;
     RECT  102.192 9.827 102.612 10.931 ;
     RECT  87.984 10.211 89.112 10.979 ;
     RECT  107.7 10.883 114.504 10.979 ;
     RECT  64.32 9.637 64.92 11.027 ;
     RECT  80.544 10.835 87 11.027 ;
     RECT  80.7 11.027 87 11.317 ;
     RECT  104.544 10.307 105.312 11.363 ;
     RECT  34.8 10.307 41.016 11.365 ;
     RECT  42.048 10.307 44.376 11.365 ;
     RECT  63.216 10.213 63.24 11.413 ;
     RECT  18 10.883 25.56 11.459 ;
     RECT  34.8 11.365 44.376 11.459 ;
     RECT  47.04 10.885 54.12 11.459 ;
     RECT  60.768 10.355 62.112 11.459 ;
     RECT  74.064 10.307 78.312 11.459 ;
     RECT  80.7 11.317 87.768 11.459 ;
     RECT  107.7 10.979 113.412 11.459 ;
     RECT  114.48 10.979 114.504 11.459 ;
     RECT  18.192 11.459 19.752 11.507 ;
     RECT  28.896 9.875 32.412 11.507 ;
     RECT  111.936 11.459 113.412 11.555 ;
     RECT  112.944 11.555 113.412 11.651 ;
     RECT  44.208 11.459 44.376 11.797 ;
     RECT  102.3 10.931 102.612 11.797 ;
     RECT  104.592 11.363 105.312 11.845 ;
     RECT  99.168 10.309 99.912 11.893 ;
     RECT  21.3 11.459 25.56 11.939 ;
     RECT  50.112 11.459 54.012 11.939 ;
     RECT  72.288 9.155 72.912 11.941 ;
     RECT  85.2 11.459 87.768 11.941 ;
     RECT  91.344 10.595 92.712 11.941 ;
     RECT  94.2 10.883 94.512 11.941 ;
     RECT  115.8 10.883 116.112 11.941 ;
     RECT  55.584 10.883 59.688 11.989 ;
     RECT  14.784 10.883 17.016 12.035 ;
     RECT  18.336 11.507 19.752 12.035 ;
     RECT  55.296 11.989 59.688 12.035 ;
     RECT  47.04 11.459 48.984 12.083 ;
     RECT  63.12 11.413 63.24 12.083 ;
     RECT  91.344 11.941 94.512 12.179 ;
     RECT  69.9 9.155 70.212 12.277 ;
     RECT  22.608 11.939 25.56 12.325 ;
     RECT  26.592 10.883 27.912 12.325 ;
     RECT  106.512 11.941 106.536 12.325 ;
     RECT  107.7 11.459 109.224 12.325 ;
     RECT  55.296 12.035 58.056 12.373 ;
     RECT  34.8 11.459 35.208 12.515 ;
     RECT  96.9 10.307 97.32 12.515 ;
     RECT  44.208 11.797 44.472 12.517 ;
     RECT  45.6 10.883 45.912 12.517 ;
     RECT  72.192 11.941 72.912 12.517 ;
     RECT  74.112 11.459 78.312 12.517 ;
     RECT  96.9 12.515 97.212 12.517 ;
     RECT  102.3 11.797 102.984 12.517 ;
     RECT  104.592 11.845 105.432 12.517 ;
     RECT  111.936 11.555 111.96 12.517 ;
     RECT  15.072 12.035 17.016 12.563 ;
     RECT  37.5 11.459 43.212 12.563 ;
     RECT  44.208 12.517 45.912 12.563 ;
     RECT  50.112 11.939 51.528 12.563 ;
     RECT  55.152 12.373 58.056 12.563 ;
     RECT  72.192 12.517 78.312 12.563 ;
     RECT  106.512 12.325 109.224 12.611 ;
     RECT  111.936 12.517 112.008 12.659 ;
     RECT  63.12 12.083 63.144 12.755 ;
     RECT  98.304 11.893 99.912 12.755 ;
     RECT  44.448 12.563 45.912 12.899 ;
     RECT  22.608 12.325 27.912 12.995 ;
     RECT  25.344 12.995 27.912 13.091 ;
     RECT  88.8 10.979 89.112 13.093 ;
     RECT  90.24 10.595 90.264 13.093 ;
     RECT  15.072 12.563 16.824 13.139 ;
     RECT  18.432 12.035 19.752 13.139 ;
     RECT  22.608 12.995 24.312 13.139 ;
     RECT  26.592 13.091 27.912 13.139 ;
     RECT  28.944 11.507 32.412 13.139 ;
     RECT  36.24 11.459 36.264 13.139 ;
     RECT  37.5 12.563 40.512 13.139 ;
     RECT  72.192 12.563 76.824 13.139 ;
     RECT  88.8 13.093 90.264 13.139 ;
     RECT  106.512 12.611 106.536 13.139 ;
     RECT  114.96 11.941 116.112 13.139 ;
     RECT  56.304 12.563 58.056 13.235 ;
     RECT  102.3 12.517 103.08 13.283 ;
     RECT  31.152 13.139 32.412 13.331 ;
     RECT  56.304 13.235 58.008 13.331 ;
     RECT  69.9 12.277 70.344 13.331 ;
     RECT  80.7 11.459 83.712 13.331 ;
     RECT  88.8 13.139 90.072 13.331 ;
     RECT  0.192 10.789 0.216 13.427 ;
     RECT  104.4 12.517 105.432 13.571 ;
     RECT  111.984 12.659 112.008 13.621 ;
     RECT  112.992 11.651 113.412 13.621 ;
     RECT  18.432 13.139 19.704 13.715 ;
     RECT  28.944 13.139 30.168 13.715 ;
     RECT  75.3 13.139 76.824 13.715 ;
     RECT  77.808 12.563 78.312 13.715 ;
     RECT  83.136 13.331 83.712 13.715 ;
     RECT  85.2 11.941 87.816 13.715 ;
     RECT  105 13.571 105.432 13.715 ;
     RECT  102.3 13.283 102.984 13.763 ;
     RECT  75.3 13.715 76.632 13.811 ;
     RECT  85.2 13.715 87.768 13.811 ;
     RECT  61.44 11.459 62.112 14.101 ;
     RECT  52.944 11.939 54.012 14.197 ;
     RECT  80.7 13.331 82.056 14.291 ;
     RECT  80.7 14.291 81.768 14.339 ;
     RECT  80.7 14.339 81.528 14.387 ;
     RECT  83.232 13.715 83.712 14.435 ;
     RECT  67.2 10.019 67.512 14.677 ;
     RECT  18.6 13.715 19.704 14.773 ;
     RECT  69.9 13.331 70.212 14.773 ;
     RECT  85.2 13.811 87.144 14.867 ;
     RECT  111.984 13.621 113.412 14.867 ;
     RECT  60.816 14.101 62.112 14.963 ;
     RECT  105 13.715 105.312 15.061 ;
     RECT  91.344 12.179 92.616 15.443 ;
     RECT  18.6 14.773 19.944 15.875 ;
     RECT  26.592 13.139 27.816 16.019 ;
     RECT  55.152 12.563 55.176 16.019 ;
     RECT  72.192 13.139 74.28 16.019 ;
     RECT  91.344 15.443 91.812 16.019 ;
     RECT  52.944 14.197 54.12 16.165 ;
     RECT  47.232 12.083 48.984 16.501 ;
     RECT  52.944 16.165 54.984 16.501 ;
     RECT  96.528 12.517 97.212 16.501 ;
     RECT  15.216 13.139 16.824 16.595 ;
     RECT  25.344 13.091 25.512 16.595 ;
     RECT  26.7 16.019 27.816 16.595 ;
     RECT  29.28 13.715 30.168 16.595 ;
     RECT  42.048 12.563 43.212 16.595 ;
     RECT  45.36 12.899 45.912 16.595 ;
     RECT  56.304 13.331 57.528 16.595 ;
     RECT  72.192 16.019 73.416 16.595 ;
     RECT  75.3 13.811 76.584 16.595 ;
     RECT  80.7 14.387 81.48 16.595 ;
     RECT  96.528 16.501 98.04 16.595 ;
     RECT  39.264 13.139 40.512 16.643 ;
     RECT  25.344 16.595 25.368 16.835 ;
     RECT  86.1 14.867 87.144 16.981 ;
     RECT  37.5 13.139 37.944 17.077 ;
     RECT  46.992 16.501 48.984 17.077 ;
     RECT  18.6 15.875 19.704 17.123 ;
     RECT  22.704 13.139 24.312 17.123 ;
     RECT  26.7 16.595 27.72 17.123 ;
     RECT  42.144 16.595 43.212 17.123 ;
     RECT  56.4 16.595 57.528 17.123 ;
     RECT  59.1 12.035 59.688 17.123 ;
     RECT  61.44 14.963 62.112 17.123 ;
     RECT  64.32 11.027 64.812 17.123 ;
     RECT  99.12 12.755 99.912 17.123 ;
     RECT  107.7 12.611 109.224 17.123 ;
     RECT  15.216 16.595 16.212 17.171 ;
     RECT  46.944 17.077 48.984 17.171 ;
     RECT  85.296 16.981 87.144 17.171 ;
     RECT  26.7 17.123 27.672 17.219 ;
     RECT  52.464 16.501 54.984 17.219 ;
     RECT  56.4 17.123 57.192 17.219 ;
     RECT  112.992 14.867 113.412 17.413 ;
     RECT  22.752 17.123 24.312 17.603 ;
     RECT  45.6 16.595 45.912 17.605 ;
     RECT  72.192 16.595 72.912 17.605 ;
     RECT  37.5 17.077 37.992 17.651 ;
     RECT  104.256 15.061 105.312 17.651 ;
     RECT  15.792 17.171 16.212 17.699 ;
     RECT  50.112 12.563 51.312 17.699 ;
     RECT  69.9 14.773 70.344 17.699 ;
     RECT  53.7 17.219 54.984 17.939 ;
     RECT  85.296 17.171 86.412 17.987 ;
     RECT  22.752 17.603 22.776 18.179 ;
     RECT  52.464 17.219 52.488 18.179 ;
     RECT  66.48 14.677 67.512 18.179 ;
     RECT  72.144 17.605 72.912 18.179 ;
     RECT  13.2 10.883 13.512 18.229 ;
     RECT  18.6 17.123 18.912 18.229 ;
     RECT  21.3 11.939 21.612 18.229 ;
     RECT  42.9 17.123 43.212 18.229 ;
     RECT  69.9 17.699 70.212 18.229 ;
     RECT  77.856 13.715 78.312 18.229 ;
     RECT  83.4 14.435 83.712 18.229 ;
     RECT  99.6 17.123 99.912 18.229 ;
     RECT  107.7 17.123 108.012 18.229 ;
     RECT  110.4 11.459 110.712 18.229 ;
     RECT  39.312 16.643 40.512 18.275 ;
     RECT  46.944 17.171 48.612 18.275 ;
     RECT  96.9 16.595 98.04 18.275 ;
     RECT  99.312 18.229 99.912 18.613 ;
     RECT  13.2 18.229 14.28 18.757 ;
     RECT  15.9 17.699 16.212 18.757 ;
     RECT  29.4 16.595 29.712 18.757 ;
     RECT  34.8 12.515 35.112 18.757 ;
     RECT  37.5 17.651 37.812 18.757 ;
     RECT  40.08 18.275 40.512 18.757 ;
     RECT  42.9 18.229 43.464 18.757 ;
     RECT  61.8 17.123 62.112 18.757 ;
     RECT  68.976 18.229 70.212 18.757 ;
     RECT  71.472 18.229 71.496 18.757 ;
     RECT  75.3 16.595 75.612 18.757 ;
     RECT  86.1 17.987 86.412 18.757 ;
     RECT  88.8 13.331 89.112 18.757 ;
     RECT  91.5 16.019 91.812 18.757 ;
     RECT  102.3 13.763 102.612 18.757 ;
     RECT  105 17.651 105.312 18.757 ;
     RECT  107.184 18.229 108.012 18.757 ;
     RECT  28.08 18.229 28.104 18.805 ;
     RECT  29.4 18.757 30.792 18.805 ;
     RECT  42.9 18.757 44.232 18.805 ;
     RECT  45.408 17.605 45.912 18.805 ;
     RECT  56.4 17.219 56.712 18.805 ;
     RECT  61.104 18.757 62.28 18.805 ;
     RECT  64.5 17.123 64.812 18.805 ;
     RECT  80.7 16.595 81.012 18.805 ;
     RECT  82.224 18.757 82.248 18.805 ;
     RECT  83.28 18.229 83.712 18.805 ;
     RECT  98.736 18.613 99.912 18.805 ;
     RECT  101.808 18.757 102.792 18.805 ;
     RECT  103.92 18.757 108.012 18.805 ;
     RECT  115.8 13.139 116.112 18.805 ;
     RECT  28.08 18.805 30.792 18.853 ;
     RECT  18.288 18.229 18.912 18.997 ;
     RECT  20.592 18.229 21.612 18.997 ;
     RECT  24 17.603 24.312 18.997 ;
     RECT  53.7 17.939 54.12 18.997 ;
     RECT  59.1 17.123 59.412 19.189 ;
     RECT  101.808 18.805 108.012 19.189 ;
     RECT  18.288 18.997 21.612 19.237 ;
     RECT  24 18.997 25.032 19.237 ;
     RECT  26.7 17.219 27.012 19.237 ;
     RECT  28.08 18.853 30.888 19.237 ;
     RECT  32.1 13.331 32.412 19.237 ;
     RECT  34.8 18.757 37.812 19.237 ;
     RECT  40.08 18.757 40.68 19.237 ;
     RECT  42.9 18.805 46.728 19.237 ;
     RECT  50.16 17.699 51.312 19.237 ;
     RECT  53.7 18.997 54.6 19.237 ;
     RECT  55.728 18.805 56.712 19.237 ;
     RECT  59.1 19.189 59.784 19.237 ;
     RECT  61.104 18.805 64.968 19.237 ;
     RECT  66.096 18.805 66.12 19.237 ;
     RECT  68.976 18.757 71.496 19.237 ;
     RECT  72.6 18.179 72.912 19.237 ;
     RECT  75.3 18.757 76.104 19.237 ;
     RECT  77.616 18.229 78.312 19.237 ;
     RECT  79.728 18.805 84.936 19.237 ;
     RECT  96.9 18.275 97.212 19.237 ;
     RECT  98.736 18.805 100.296 19.237 ;
     RECT  110.064 18.229 110.712 19.237 ;
     RECT  112.848 17.413 113.412 19.237 ;
     RECT  23.856 19.237 27.012 19.285 ;
     RECT  28.08 19.237 32.412 19.285 ;
     RECT  42.672 19.237 46.728 19.285 ;
     RECT  47.856 18.275 48.612 19.285 ;
     RECT  68.784 19.237 71.496 19.285 ;
     RECT  72.6 19.237 73.416 19.285 ;
     RECT  75.3 19.237 84.936 19.285 ;
     RECT  94.2 12.179 94.512 19.285 ;
     RECT  96.24 19.237 100.296 19.285 ;
     RECT  101.424 19.189 108.012 19.285 ;
     RECT  13.2 18.757 16.212 19.333 ;
     RECT  18.288 19.237 22.536 19.333 ;
     RECT  23.856 19.285 32.412 19.333 ;
     RECT  34.608 19.237 38.664 19.333 ;
     RECT  40.08 19.237 40.968 19.333 ;
     RECT  42.672 19.285 48.612 19.333 ;
     RECT  50.16 19.237 52.296 19.333 ;
     RECT  53.7 19.237 56.712 19.333 ;
     RECT  58.032 19.237 66.12 19.333 ;
     RECT  67.2 18.179 67.512 19.333 ;
     RECT  68.784 19.285 73.416 19.333 ;
     RECT  74.544 19.285 84.936 19.333 ;
     RECT  86.1 18.757 86.52 19.333 ;
     RECT  87.984 18.757 89.256 19.333 ;
     RECT  91.5 18.757 92.424 19.333 ;
     RECT  94.2 19.285 95.112 19.333 ;
     RECT  96.24 19.285 108.012 19.333 ;
     RECT  109.872 19.237 110.712 19.333 ;
     RECT  112.752 19.237 113.928 19.333 ;
     RECT  115.056 18.805 116.112 19.333 ;
     RECT  2.4 2.151 2.712 19.449 ;
     RECT  5.1 2.151 5.412 19.449 ;
     RECT  7.8 2.151 8.112 19.449 ;
     RECT  10.5 2.151 10.812 19.449 ;
     RECT  13.2 19.333 116.112 19.449 ;
     RECT  118.5 2.151 118.812 19.449 ;
     RECT  121.2 2.151 121.512 19.449 ;
     RECT  123.9 2.151 124.212 19.449 ;
     RECT  126.6 2.151 126.912 19.449 ;
     RECT  2.4 19.449 2.52 19.463 ;
     RECT  5.1 19.449 5.22 19.463 ;
     RECT  7.8 19.449 7.92 19.463 ;
     RECT  10.5 19.449 10.62 19.463 ;
     RECT  13.2 19.449 116.04 19.463 ;
     RECT  118.5 19.449 118.62 19.463 ;
     RECT  121.2 19.449 121.32 19.463 ;
     RECT  123.9 19.449 124.02 19.463 ;
     RECT  126.6 19.449 126.72 19.463 ;
     RECT  14.064 19.463 116.04 21.445 ;
     RECT  13.68 21.445 116.04 21.493 ;
     RECT  13.488 21.493 116.04 21.584 ;
     RECT  65.544 4.019 66.528 6.323 ;
     RECT  60.264 4.595 61.344 5.171 ;
     RECT  71.256 4.595 72.336 5.747 ;
     RECT  54.504 5.171 55.536 8.099 ;
     RECT  59.784 5.171 61.344 5.605 ;
     RECT  62.52 5.171 63.696 6.229 ;
     RECT  68.904 5.171 69.9 5.747 ;
     RECT  59.784 5.605 60.864 7.765 ;
     RECT  51.864 5.747 52.848 8.003 ;
     RECT  71.112 5.747 72.336 6.229 ;
     RECT  62.616 6.229 63.696 6.323 ;
     RECT  71.112 6.229 72.288 6.805 ;
     RECT  58.008 6.323 58.992 7.861 ;
     RECT  65.544 6.323 66.624 6.851 ;
     RECT  103.08 6.323 104.064 6.899 ;
     RECT  71.256 6.805 72.288 8.291 ;
     RECT  103.08 6.899 104.256 8.437 ;
     RECT  111.144 6.899 112.176 8.003 ;
     RECT  87 7.475 87.984 9.637 ;
     RECT  67.512 7.861 68.928 7.909 ;
     RECT  51.576 8.003 52.848 8.099 ;
     RECT  62.112 8.003 62.616 9.109 ;
     RECT  111.096 8.003 112.176 9.925 ;
     RECT  51.528 8.099 52.848 8.819 ;
     RECT  54.504 8.099 55.584 8.149 ;
     RECT  54.552 8.149 55.584 8.723 ;
     RECT  71.064 8.291 72.288 8.579 ;
     RECT  45.912 8.579 47.04 12.083 ;
     RECT  64.812 8.579 64.92 9.637 ;
     RECT  103.512 8.627 104.592 9.827 ;
     RECT  101.208 8.675 102.192 9.731 ;
     RECT  54.12 8.723 55.584 11.459 ;
     RECT  89.112 8.723 90.24 13.093 ;
     RECT  51.528 8.819 52.944 10.885 ;
     RECT  67.512 8.867 68.928 9.155 ;
     RECT  105.432 9.011 106.56 10.307 ;
     RECT  62.808 9.109 64.32 9.683 ;
     RECT  41.016 9.155 42.048 11.365 ;
     RECT  72.912 9.155 74.064 11.459 ;
     RECT  97.992 9.155 99.408 9.731 ;
     RECT  33.528 9.635 34.608 10.307 ;
     RECT  62.112 9.683 64.32 10.213 ;
     RECT  32.412 9.731 33.504 10.883 ;
     RECT  99.168 9.731 99.408 10.309 ;
     RECT  104.544 9.827 104.592 9.925 ;
     RECT  27.912 9.875 28.896 11.507 ;
     RECT  93.144 9.875 94.2 10.307 ;
     RECT  87 10.211 87.984 10.979 ;
     RECT  62.112 10.213 63.216 11.413 ;
     RECT  63.24 10.213 64.32 12.083 ;
     RECT  17.016 10.307 18 11.459 ;
     RECT  33.528 10.307 34.8 10.883 ;
     RECT  44.376 10.307 45.504 10.883 ;
     RECT  92.712 10.307 94.2 11.941 ;
     RECT  59.784 10.355 60.768 10.883 ;
     RECT  90.264 10.595 91.344 13.139 ;
     RECT  13.512 10.883 14.784 12.035 ;
     RECT  25.56 10.883 26.592 12.325 ;
     RECT  44.376 10.883 45.6 11.797 ;
     RECT  59.688 10.883 60.768 11.459 ;
     RECT  114.504 10.883 115.8 11.459 ;
     RECT  87 10.979 88.8 11.317 ;
     RECT  113.412 10.979 114.48 11.459 ;
     RECT  87.768 11.317 88.8 11.941 ;
     RECT  104.544 11.363 104.592 12.517 ;
     RECT  62.112 11.413 63.12 12.755 ;
     RECT  17.016 11.459 18.192 11.507 ;
     RECT  35.208 11.459 36.24 12.515 ;
     RECT  36.264 11.459 37.5 13.139 ;
     RECT  43.212 11.459 44.208 12.563 ;
     RECT  48.984 11.459 50.112 17.171 ;
     RECT  54.012 11.459 55.584 11.989 ;
     RECT  72.912 11.459 74.112 12.517 ;
     RECT  83.712 11.459 85.2 14.867 ;
     RECT  109.224 11.459 110.4 17.123 ;
     RECT  110.712 11.459 111.936 12.659 ;
     RECT  114.96 11.459 115.8 11.941 ;
     RECT  17.016 11.507 18.336 12.035 ;
     RECT  27.912 11.507 28.944 13.139 ;
     RECT  111.96 11.555 112.944 11.651 ;
     RECT  111.96 11.651 112.992 12.517 ;
     RECT  44.472 11.797 45.6 12.517 ;
     RECT  97.32 11.893 98.304 12.515 ;
     RECT  21.612 11.939 22.608 13.139 ;
     RECT  51.528 11.939 52.944 12.563 ;
     RECT  87.816 11.941 88.8 13.715 ;
     RECT  105.432 11.941 106.512 13.139 ;
     RECT  106.536 11.941 107.7 12.325 ;
     RECT  54.012 11.989 55.296 12.373 ;
     RECT  17.016 12.035 18.432 12.563 ;
     RECT  58.056 12.035 59.1 13.235 ;
     RECT  45.912 12.083 47.232 16.501 ;
     RECT  63.144 12.083 64.32 12.755 ;
     RECT  54.012 12.373 55.152 14.197 ;
     RECT  35.112 12.515 36.24 13.139 ;
     RECT  97.212 12.515 98.304 12.755 ;
     RECT  103.08 12.517 104.4 13.283 ;
     RECT  112.008 12.517 112.992 13.621 ;
     RECT  43.212 12.563 44.448 12.899 ;
     RECT  55.176 12.563 56.304 16.019 ;
     RECT  76.824 12.563 77.808 13.715 ;
     RECT  106.536 12.611 107.7 13.139 ;
     RECT  110.712 12.659 111.984 14.867 ;
     RECT  24.312 12.995 25.344 16.835 ;
     RECT  25.512 13.091 26.592 16.019 ;
     RECT  21.612 13.139 22.704 17.123 ;
     RECT  27.816 13.139 28.944 13.715 ;
     RECT  30.168 13.139 31.152 13.331 ;
     RECT  37.944 13.139 39.264 16.643 ;
     RECT  74.28 13.139 75.3 16.019 ;
     RECT  90.072 13.139 91.344 13.331 ;
     RECT  58.008 13.235 59.1 13.331 ;
     RECT  102.984 13.283 104.4 13.571 ;
     RECT  70.212 13.331 70.344 14.773 ;
     RECT  82.056 13.331 83.136 13.715 ;
     RECT  102.984 13.571 105 13.763 ;
     RECT  27.816 13.715 29.28 16.595 ;
     RECT  76.632 13.715 77.856 13.811 ;
     RECT  82.056 13.715 83.232 14.291 ;
     RECT  87.768 13.715 88.8 13.811 ;
     RECT  104.256 13.763 105 15.061 ;
     RECT  76.584 13.811 77.856 16.595 ;
     RECT  59.688 14.101 60.816 14.963 ;
     RECT  54.12 14.197 55.152 16.019 ;
     RECT  81.768 14.291 83.232 14.339 ;
     RECT  19.944 14.773 21.3 15.875 ;
     RECT  25.512 16.019 26.7 16.595 ;
     RECT  54.12 16.019 56.304 16.165 ;
     RECT  54.984 16.165 56.304 16.595 ;
     RECT  45.912 16.501 46.992 17.077 ;
     RECT  51.312 16.501 52.464 18.179 ;
     RECT  98.04 16.501 99.12 17.123 ;
     RECT  25.368 16.595 26.7 16.835 ;
     RECT  45.408 16.595 45.6 17.605 ;
     RECT  54.984 16.595 56.4 17.939 ;
     RECT  37.944 16.643 39.312 17.077 ;
     RECT  37.992 17.077 39.312 17.651 ;
     RECT  45.912 17.077 46.944 18.275 ;
     RECT  21.612 17.123 22.752 18.179 ;
     RECT  27.672 17.123 27.72 17.219 ;
     RECT  98.04 17.123 99.6 18.229 ;
     RECT  110.064 17.123 110.4 18.229 ;
     RECT  15.216 17.171 15.792 17.699 ;
     RECT  48.612 17.171 50.112 17.699 ;
     RECT  27.012 17.219 27.72 18.229 ;
     RECT  52.488 17.219 53.7 18.179 ;
     RECT  22.776 17.603 24 18.179 ;
     RECT  37.812 17.651 39.312 18.275 ;
     RECT  104.256 17.651 105 18.757 ;
     RECT  15.216 17.699 15.9 18.229 ;
     RECT  70.212 17.699 70.344 18.229 ;
     RECT  54.12 17.939 56.4 18.805 ;
     RECT  85.296 17.987 86.1 18.805 ;
     RECT  21.612 18.179 24 19.237 ;
     RECT  51.312 18.179 53.7 19.237 ;
     RECT  66.48 18.179 67.2 18.805 ;
     RECT  72.144 18.179 72.6 18.229 ;
     RECT  14.28 18.229 15.9 18.757 ;
     RECT  27.012 18.229 28.08 19.285 ;
     RECT  28.104 18.229 29.4 18.805 ;
     RECT  67.512 18.229 68.976 19.237 ;
     RECT  70.212 18.229 71.472 18.757 ;
     RECT  71.496 18.229 72.6 19.285 ;
     RECT  98.04 18.229 99.312 18.275 ;
     RECT  37.812 18.275 40.08 19.237 ;
     RECT  45.912 18.275 47.856 18.805 ;
     RECT  97.212 18.275 99.312 18.613 ;
     RECT  97.212 18.613 98.736 19.237 ;
     RECT  30.792 18.757 32.1 18.853 ;
     RECT  44.232 18.757 45.408 18.805 ;
     RECT  76.104 18.757 77.616 19.237 ;
     RECT  81.012 18.757 82.224 18.805 ;
     RECT  82.248 18.757 83.28 18.805 ;
     RECT  86.52 18.757 87.984 19.333 ;
     RECT  102.792 18.757 103.92 18.805 ;
     RECT  46.728 18.805 47.856 19.285 ;
     RECT  54.12 18.805 55.728 18.997 ;
     RECT  64.968 18.805 66.096 19.237 ;
     RECT  66.12 18.805 67.2 19.333 ;
     RECT  78.312 18.805 79.728 19.237 ;
     RECT  84.936 18.805 86.1 19.333 ;
     RECT  100.296 18.805 101.808 19.189 ;
     RECT  30.888 18.853 32.1 19.237 ;
     RECT  54.6 18.997 55.728 19.237 ;
     RECT  59.784 19.189 61.104 19.237 ;
     RECT  100.296 19.189 101.424 19.285 ;
     RECT  22.536 19.237 23.856 19.333 ;
     RECT  38.664 19.237 40.08 19.333 ;
     RECT  52.296 19.237 53.7 19.333 ;
     RECT  56.712 19.237 58.032 19.333 ;
     RECT  67.512 19.237 68.784 19.333 ;
     RECT  113.928 19.237 115.056 19.333 ;
     RECT  73.416 19.285 74.544 19.333 ;
     RECT  95.112 19.285 96.24 19.333 ;
  END
END qkh_head_chunk_stage
END LIBRARY
